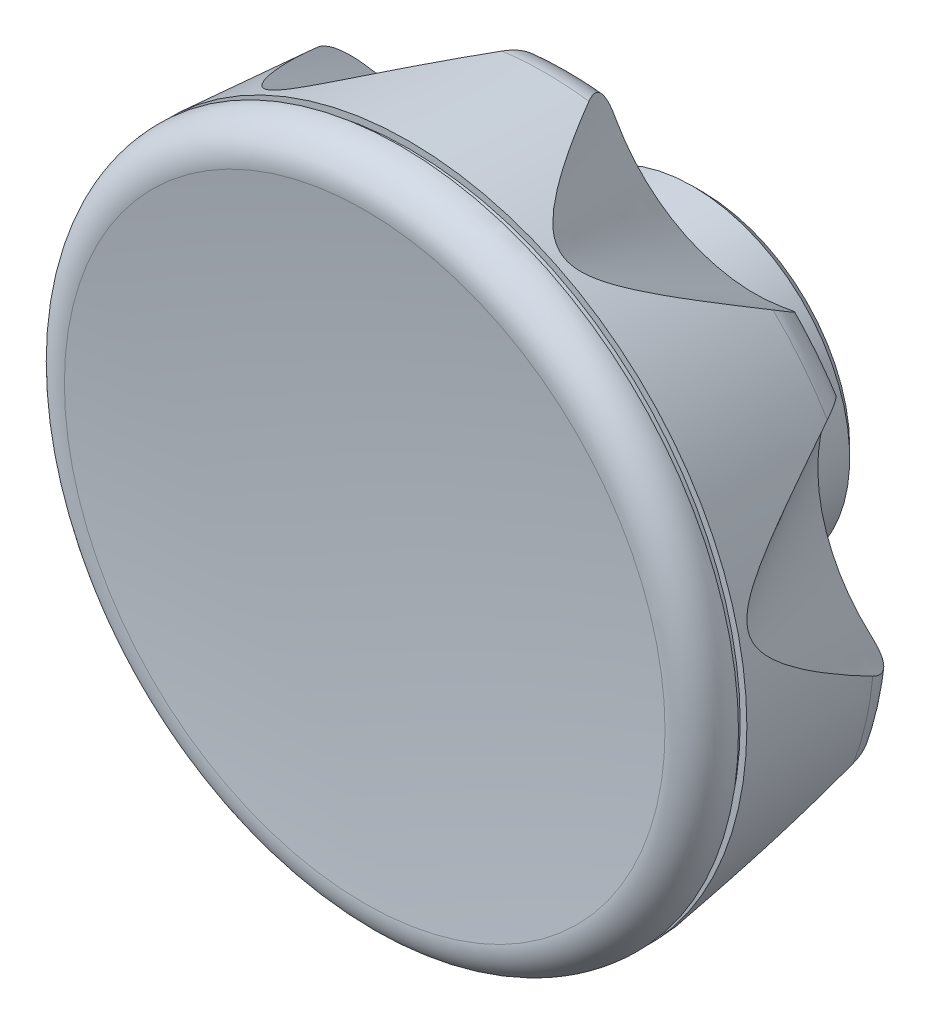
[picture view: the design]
ISO-10303-21;
HEADER;
FILE_DESCRIPTION(('STEP AP214'),'2;1');
FILE_NAME('part.step','',(''),(''),'','','');
FILE_SCHEMA(('AUTOMOTIVE_DESIGN { 1 0 10303 214 1 1 1 1 }'));
ENDSEC;
DATA;
#1=APPLICATION_CONTEXT('core data for automotive mechanical design processes');
#2=APPLICATION_PROTOCOL_DEFINITION('international standard','automotive_design',2000,#1);
#3=PRODUCT_CONTEXT('',#1,'mechanical');
#4=PRODUCT('Part','Part','',(#3));
#5=PRODUCT_RELATED_PRODUCT_CATEGORY('part','',(#4));
#6=PRODUCT_DEFINITION_FORMATION('','',#4);
#7=PRODUCT_DEFINITION_CONTEXT('part definition',#1,'design');
#8=PRODUCT_DEFINITION('design','',#6,#7);
#9=PRODUCT_DEFINITION_SHAPE('','',#8);
#10=(LENGTH_UNIT() NAMED_UNIT(*) SI_UNIT(.MILLI.,.METRE.));
#11=(NAMED_UNIT(*) PLANE_ANGLE_UNIT() SI_UNIT($,.RADIAN.));
#12=(NAMED_UNIT(*) SI_UNIT($,.STERADIAN.) SOLID_ANGLE_UNIT());
#13=UNCERTAINTY_MEASURE_WITH_UNIT(LENGTH_MEASURE(1.E-05),#10,'distance_accuracy_value','');
#14=(GEOMETRIC_REPRESENTATION_CONTEXT(3) GLOBAL_UNCERTAINTY_ASSIGNED_CONTEXT((#13)) GLOBAL_UNIT_ASSIGNED_CONTEXT((#10,
#11,#12)) REPRESENTATION_CONTEXT('',''));
#15=CARTESIAN_POINT('',(0.,0.,0.));
#16=DIRECTION('',(0.,0.,1.));
#17=DIRECTION('',(1.,0.,0.));
#18=AXIS2_PLACEMENT_3D('',#15,#16,#17);
#19=CARTESIAN_POINT('',(0.,0.,16.5));
#20=DIRECTION('',(0.,0.,1.));
#21=DIRECTION('',(0.,1.,0.));
#22=AXIS2_PLACEMENT_3D('',#19,#20,#21);
#23=TOROIDAL_SURFACE('',#22,30.5569827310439,3.49999999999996);
#24=CARTESIAN_POINT('',(-30.4277694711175,-2.80714065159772,12.9999999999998));
#25=CARTESIAN_POINT('',(-30.4922913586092,-2.86477433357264,12.9999995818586));
#26=CARTESIAN_POINT('',(-30.558064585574,-2.92106397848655,13.002073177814));
#27=CARTESIAN_POINT('',(-30.6919823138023,-3.03053883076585,13.010813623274));
#28=CARTESIAN_POINT('',(-30.7601296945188,-3.08372004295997,13.017486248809));
#29=CARTESIAN_POINT('',(-30.8991260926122,-3.18687819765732,13.0359552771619));
#30=CARTESIAN_POINT('',(-30.9699939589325,-3.23682184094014,13.0477974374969));
#31=CARTESIAN_POINT('',(-31.1134463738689,-3.33240092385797,13.0770311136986));
#32=CARTESIAN_POINT('',(-31.1860302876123,-3.378037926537,13.0944206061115));
#33=CARTESIAN_POINT('',(-31.3330374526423,-3.46480885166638,13.1352731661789));
#34=CARTESIAN_POINT('',(-31.4074708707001,-3.50590306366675,13.1587845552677));
#35=CARTESIAN_POINT('',(-31.5569302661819,-3.58258562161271,13.2120638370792));
#36=CARTESIAN_POINT('',(-31.6319561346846,-3.61817495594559,13.2418306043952));
#37=CARTESIAN_POINT('',(-31.7815087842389,-3.68321920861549,13.3075877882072));
#38=CARTESIAN_POINT('',(-31.856036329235,-3.71269963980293,13.34355112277));
#39=CARTESIAN_POINT('',(-32.0040438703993,-3.76533170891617,13.4217135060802));
#40=CARTESIAN_POINT('',(-32.077524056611,-3.78848450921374,13.4639114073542));
#41=CARTESIAN_POINT('',(-32.2127536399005,-3.82555260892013,13.5481801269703));
#42=CARTESIAN_POINT('',(-32.2747476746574,-3.84029295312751,13.5894992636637));
#43=CARTESIAN_POINT('',(-32.3967559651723,-3.8648324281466,13.6763591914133));
#44=CARTESIAN_POINT('',(-32.4567695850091,-3.87462998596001,13.7219013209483));
#45=CARTESIAN_POINT('',(-32.5743242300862,-3.88932568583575,13.8168914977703));
#46=CARTESIAN_POINT('',(-32.6318634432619,-3.89422029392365,13.8663423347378));
#47=CARTESIAN_POINT('',(-32.7439869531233,-3.89923372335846,13.9687276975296));
#48=CARTESIAN_POINT('',(-32.7985700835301,-3.89935067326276,14.0216635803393));
#49=CARTESIAN_POINT('',(-32.9523859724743,-3.89300950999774,14.1800128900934));
#50=CARTESIAN_POINT('',(-33.0472644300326,-3.88049800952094,14.289516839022));
#51=CARTESIAN_POINT('',(-33.2229626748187,-3.84059009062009,14.5165356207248));
#52=CARTESIAN_POINT('',(-33.3037858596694,-3.81319727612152,14.6340485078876));
#53=CARTESIAN_POINT('',(-33.4587694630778,-3.74182305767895,14.8877018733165));
#54=CARTESIAN_POINT('',(-33.5312118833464,-3.69634528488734,15.0244673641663));
#55=CARTESIAN_POINT('',(-33.6577169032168,-3.59210577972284,15.3014973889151));
#56=CARTESIAN_POINT('',(-33.7117580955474,-3.53332870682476,15.4417657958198));
#57=CARTESIAN_POINT('',(-33.7933589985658,-3.41681811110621,15.6966901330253));
#58=CARTESIAN_POINT('',(-33.8239786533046,-3.36093708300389,15.8112404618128));
#59=CARTESIAN_POINT('',(-33.8735900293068,-3.24311939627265,16.0391889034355));
#60=CARTESIAN_POINT('',(-33.8926252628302,-3.18120642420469,16.1525897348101));
#61=CARTESIAN_POINT('',(-33.906149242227,-3.11665429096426,16.2650726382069));
#62=B_SPLINE_CURVE_WITH_KNOTS('',3,(#24,#25,#26,#27,#28,#29,#30,#31,#32,#33,#34,#35,#36,#37,#38,
#39,#40,#41,#42,#43,#44,#45,#46,#47,#48,#49,#50,#51,#52,#53,#54,#55,#56,#57,#58,#59,#60,#61),
.UNSPECIFIED.,.F.,.F.,(4,2,2,2,2,2,2,2,2,2,2,2,2,2,2,2,2,2,4),(0.,0.259555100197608,
0.519436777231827,0.781666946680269,1.04380157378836,1.30807155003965,1.57229402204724,
1.83538972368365,2.09843706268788,2.32597812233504,2.55359154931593,2.78136891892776,
3.00923550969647,3.44356210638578,3.87778356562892,4.35989598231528,4.84256736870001,
5.23515773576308,5.6262642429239),.UNSPECIFIED.);
#63=CARTESIAN_POINT('',(-30.4277694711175,-2.8071406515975,12.9999999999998));
#64=VERTEX_POINT('',#63);
#65=CARTESIAN_POINT('',(-33.906149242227,-3.11665429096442,16.2650726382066));
#66=VERTEX_POINT('',#65);
#67=EDGE_CURVE('E116',#64,#66,#62,.T.);
#68=ORIENTED_EDGE('',*,*,#67,.F.);
#69=CARTESIAN_POINT('',(0.,0.,12.9999999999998));
#70=DIRECTION('',(0.,0.,1.));
#71=DIRECTION('',(0.,1.,0.));
#72=AXIS2_PLACEMENT_3D('',#69,#70,#71);
#73=CIRCLE('',#72,30.5569827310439);
#74=CARTESIAN_POINT('',(-28.632445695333,-10.6729680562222,12.9999999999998));
#75=VERTEX_POINT('',#74);
#76=EDGE_CURVE('E37',#64,#75,#73,.T.);
#77=ORIENTED_EDGE('',*,*,#76,.T.);
#78=CARTESIAN_POINT('',(-31.9006505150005,-11.9033183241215,16.2650726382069));
#79=CARTESIAN_POINT('',(-31.9127655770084,-11.8542285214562,16.1788472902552));
#80=CARTESIAN_POINT('',(-31.9213061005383,-11.8051794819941,16.092150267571));
#81=CARTESIAN_POINT('',(-31.9308592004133,-11.7073324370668,15.9181115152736));
#82=CARTESIAN_POINT('',(-31.9318654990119,-11.6585346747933,15.8307693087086));
#83=CARTESIAN_POINT('',(-31.9229383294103,-11.512015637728,15.5668553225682));
#84=CARTESIAN_POINT('',(-31.9008235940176,-11.4150672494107,15.389974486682));
#85=CARTESIAN_POINT('',(-31.8413429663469,-11.2738330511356,15.1279647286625));
#86=CARTESIAN_POINT('',(-31.8170085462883,-11.2273082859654,15.0409016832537));
#87=CARTESIAN_POINT('',(-31.7592310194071,-11.1363098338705,14.8687696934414));
#88=CARTESIAN_POINT('',(-31.7257939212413,-11.0918348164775,14.7836994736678));
#89=CARTESIAN_POINT('',(-31.6497513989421,-11.0057346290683,14.616681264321));
#90=CARTESIAN_POINT('',(-31.6071781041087,-10.9641001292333,14.53472348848));
#91=CARTESIAN_POINT('',(-31.5127571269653,-10.8842577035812,14.3745637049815));
#92=CARTESIAN_POINT('',(-31.4609118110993,-10.8460489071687,14.296360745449));
#93=CARTESIAN_POINT('',(-31.3560371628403,-10.7789272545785,14.1553613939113));
#94=CARTESIAN_POINT('',(-31.3041952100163,-10.7494623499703,14.0919431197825));
#95=CARTESIAN_POINT('',(-31.1940469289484,-10.6941766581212,13.9692748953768));
#96=CARTESIAN_POINT('',(-31.1357419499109,-10.6683551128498,13.9100240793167));
#97=CARTESIAN_POINT('',(-31.0131130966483,-10.6208593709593,13.7963342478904));
#98=CARTESIAN_POINT('',(-30.9487918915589,-10.599183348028,13.7418931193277));
#99=CARTESIAN_POINT('',(-30.8147052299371,-10.5604026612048,13.6383551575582));
#100=CARTESIAN_POINT('',(-30.7449405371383,-10.5432973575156,13.5892575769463));
#101=CARTESIAN_POINT('',(-30.6117866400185,-10.5162408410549,13.5039379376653));
#102=CARTESIAN_POINT('',(-30.5490604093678,-10.5055947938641,13.4668960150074));
#103=CARTESIAN_POINT('',(-30.4207373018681,-10.4879457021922,13.3971240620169));
#104=CARTESIAN_POINT('',(-30.3551395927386,-10.480943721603,13.3643952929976));
#105=CARTESIAN_POINT('',(-30.2216746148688,-10.4706537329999,13.3033769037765));
#106=CARTESIAN_POINT('',(-30.1538085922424,-10.467363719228,13.2750848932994));
#107=CARTESIAN_POINT('',(-30.0163143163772,-10.4644744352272,13.2229137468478));
#108=CARTESIAN_POINT('',(-29.9466854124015,-10.4648765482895,13.1990362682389));
#109=CARTESIAN_POINT('',(-29.735784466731,-10.4715361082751,13.1338837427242));
#110=CARTESIAN_POINT('',(-29.5926042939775,-10.4832546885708,13.0991362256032));
#111=CARTESIAN_POINT('',(-29.3050619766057,-10.5200545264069,13.0457059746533));
#112=CARTESIAN_POINT('',(-29.1606993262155,-10.5451418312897,13.0270305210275));
#113=CARTESIAN_POINT('',(-28.952520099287,-10.5899735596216,13.0100924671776));
#114=CARTESIAN_POINT('',(-28.8880614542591,-10.6050709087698,13.0062521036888));
#115=CARTESIAN_POINT('',(-28.7597887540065,-10.637430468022,13.0012106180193));
#116=CARTESIAN_POINT('',(-28.6959733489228,-10.6546860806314,13.0000016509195));
#117=CARTESIAN_POINT('',(-28.632445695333,-10.6729680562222,12.9999999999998));
#118=B_SPLINE_CURVE_WITH_KNOTS('',3,(#78,#79,#80,#81,#82,#83,#84,#85,#86,#87,#88,#89,#90,#91,
#92,#93,#94,#95,#96,#97,#98,#99,#100,#101,#102,#103,#104,#105,#106,#107,#108,#109,#110,#111,
#112,#113,#114,#115,#116,#117),.UNSPECIFIED.,.F.,.F.,(4,2,2,2,2,2,2,2,2,2,2,2,2,2,2,2,2,2,2,4),
(0.,0.299698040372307,0.599645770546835,1.20498031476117,1.50964069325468,1.81410045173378,
2.11750656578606,2.4208353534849,2.68159295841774,2.94229623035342,3.20288438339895,
3.46343604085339,3.68403118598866,3.90469069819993,4.12523092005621,4.34585377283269,
4.78744512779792,5.22923640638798,5.42810702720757,5.62638394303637),.UNSPECIFIED.);
#119=CARTESIAN_POINT('',(-31.9006505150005,-11.9033183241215,16.2650726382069));
#120=VERTEX_POINT('',#119);
#121=EDGE_CURVE('E340',#120,#75,#118,.T.);
#122=ORIENTED_EDGE('',*,*,#121,.F.);
#123=CARTESIAN_POINT('',(0.,0.,16.2650726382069));
#124=DIRECTION('',(0.,0.,1.));
#125=DIRECTION('',(0.,1.,0.));
#126=AXIS2_PLACEMENT_3D('',#123,#124,#125);
#127=CIRCLE('',#126,34.0490894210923);
#128=EDGE_CURVE('E123',#66,#120,#127,.T.);
#129=ORIENTED_EDGE('',*,*,#128,.F.);
#130=EDGE_LOOP('',(#68,#77,#122,#129));
#131=FACE_BOUND('',#130,.T.);
#132=ADVANCED_FACE('F14',(#131),#23,.T.);
#133=CARTESIAN_POINT('',(-16.7766930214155,-25.5396116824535,12.9999999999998));
#134=CARTESIAN_POINT('',(-16.7718619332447,-25.6259909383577,12.9999995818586));
#135=CARTESIAN_POINT('',(-16.7688618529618,-25.7125105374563,13.002073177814));
#136=CARTESIAN_POINT('',(-16.7667673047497,-25.8854680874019,13.010813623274));
#137=CARTESIAN_POINT('',(-16.7676777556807,-25.9719057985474,13.017486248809));
#138=CARTESIAN_POINT('',(-16.7736882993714,-26.1448956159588,13.0359552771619));
#139=CARTESIAN_POINT('',(-16.7788261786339,-26.2314416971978,13.0477974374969));
#140=CARTESIAN_POINT('',(-16.7935405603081,-26.4031898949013,13.0770311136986));
#141=CARTESIAN_POINT('',(-16.803115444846,-26.4883924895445,13.0944206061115));
#142=CARTESIAN_POINT('',(-16.8269326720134,-26.6574281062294,13.1352731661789));
#143=CARTESIAN_POINT('',(-16.8412124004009,-26.7412443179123,13.1587845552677));
#144=CARTESIAN_POINT('',(-16.8744459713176,-26.9059071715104,13.2120638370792));
#145=CARTESIAN_POINT('',(-16.893398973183,-26.9867543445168,13.2418306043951));
#146=CARTESIAN_POINT('',(-16.9357898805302,-27.1442337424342,13.3075877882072));
#147=CARTESIAN_POINT('',(-16.9592083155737,-27.220882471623,13.3435511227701));
#148=CARTESIAN_POINT('',(-17.0103400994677,-27.3694149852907,13.4217135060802));
#149=CARTESIAN_POINT('',(-17.0380526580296,-27.4412996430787,13.4639114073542));
#150=CARTESIAN_POINT('',(-17.0933859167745,-27.5701379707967,13.5481801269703));
#151=CARTESIAN_POINT('',(-17.1205141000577,-27.6277973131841,13.5894992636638));
#152=CARTESIAN_POINT('',(-17.1773992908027,-27.738487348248,13.6763591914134));
#153=CARTESIAN_POINT('',(-17.2071571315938,-27.7915165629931,13.7219013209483));
#154=CARTESIAN_POINT('',(-17.2689616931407,-27.8925871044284,13.8168914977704));
#155=CARTESIAN_POINT('',(-17.3010100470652,-27.9406248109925,13.8663423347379));
#156=CARTESIAN_POINT('',(-17.3669982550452,-28.0314123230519,13.9687276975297));
#157=CARTESIAN_POINT('',(-17.4009388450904,-28.0741600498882,14.0216635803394));
#158=CARTESIAN_POINT('',(-17.501799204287,-28.1904645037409,14.1800128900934));
#159=CARTESIAN_POINT('',(-17.5707368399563,-28.2568426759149,14.289516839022));
#160=CARTESIAN_POINT('',(-17.7114841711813,-28.3693269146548,14.5165356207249));
#161=CARTESIAN_POINT('',(-17.7832931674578,-28.4154378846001,14.6340485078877));
#162=CARTESIAN_POINT('',(-17.9357264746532,-28.4921078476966,14.8877018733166));
#163=CARTESIAN_POINT('',(-18.0164495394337,-28.5203906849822,15.0244673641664));
#164=CARTESIAN_POINT('',(-18.1768218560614,-28.5543040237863,15.3014973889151));
#165=CARTESIAN_POINT('',(-18.256469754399,-28.5599082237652,15.4417657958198));
#166=CARTESIAN_POINT('',(-18.3984387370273,-28.5510632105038,15.6966901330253));
#167=CARTESIAN_POINT('',(-18.4612193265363,-28.5401613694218,15.8112404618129));
#168=CARTESIAN_POINT('',(-18.5842650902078,-28.5054909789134,16.0391889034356));
#169=CARTESIAN_POINT('',(-18.6445388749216,-28.4817712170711,16.1525897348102));
#170=CARTESIAN_POINT('',(-18.703439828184,-28.4520970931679,16.2650726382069));
#171=B_SPLINE_CURVE_WITH_KNOTS('',3,(#133,#134,#135,#136,#137,#138,#139,#140,#141,#142,#143,
#144,#145,#146,#147,#148,#149,#150,#151,#152,#153,#154,#155,#156,#157,#158,#159,#160,#161,#162,
#163,#164,#165,#166,#167,#168,#169,#170),.UNSPECIFIED.,.F.,.F.,(4,2,2,2,2,2,2,2,2,2,2,2,2,2,2,2,
2,2,4),(0.,0.259555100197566,0.519436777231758,0.781666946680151,1.04380157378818,
1.30807155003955,1.57229402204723,1.83538972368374,2.09843706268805,2.32597812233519,
2.55359154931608,2.78136891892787,3.00923550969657,3.44356210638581,3.8777835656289,
4.35989598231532,4.84256736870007,5.23515773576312,5.62626424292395),.UNSPECIFIED.);
#172=CARTESIAN_POINT('',(-16.7766930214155,-25.5396116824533,12.9999999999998));
#173=VERTEX_POINT('',#172);
#174=CARTESIAN_POINT('',(-18.7034398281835,-28.4520970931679,16.2650726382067));
#175=VERTEX_POINT('',#174);
#176=EDGE_CURVE('E339',#173,#175,#171,.T.);
#177=ORIENTED_EDGE('',*,*,#176,.F.);
#178=CARTESIAN_POINT('',(-9.50757545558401,-29.040234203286,12.9999999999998));
#179=VERTEX_POINT('',#178);
#180=EDGE_CURVE('E132',#173,#179,#73,.T.);
#181=ORIENTED_EDGE('',*,*,#180,.T.);
#182=CARTESIAN_POINT('',(-10.5833412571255,-32.3625304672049,16.2650726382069));
#183=CARTESIAN_POINT('',(-10.6292748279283,-32.341395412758,16.1788472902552));
#184=CARTESIAN_POINT('',(-10.6729478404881,-32.3174910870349,16.092150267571));
#185=CARTESIAN_POINT('',(-10.755404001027,-32.2639533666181,15.9181115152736));
#186=CARTESIAN_POINT('',(-10.7941830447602,-32.2343152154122,15.8307693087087));
#187=CARTESIAN_POINT('',(-10.9031702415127,-32.1359825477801,15.5668553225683));
#188=CARTESIAN_POINT('',(-10.9651792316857,-32.0582462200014,15.389974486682));
#189=CARTESIAN_POINT('',(-11.0385150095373,-31.9236843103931,15.1279647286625));
#190=CARTESIAN_POINT('',(-11.0597172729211,-31.8756511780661,15.0409016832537));
#191=CARTESIAN_POINT('',(-11.0948390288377,-31.773742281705,14.8687696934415));
#192=CARTESIAN_POINT('',(-11.1087633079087,-31.7198703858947,14.7836994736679));
#193=CARTESIAN_POINT('',(-11.1286674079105,-31.6067353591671,14.616681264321));
#194=CARTESIAN_POINT('',(-11.1346745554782,-31.5474915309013,14.53472348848));
#195=CARTESIAN_POINT('',(-11.1382273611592,-31.4238893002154,14.3745637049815));
#196=CARTESIAN_POINT('',(-11.1357751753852,-31.3595322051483,14.2963607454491));
#197=CARTESIAN_POINT('',(-11.1228647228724,-31.2356882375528,14.1553613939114));
#198=CARTESIAN_POINT('',(-11.1135783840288,-31.1767854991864,14.0919431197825));
#199=CARTESIAN_POINT('',(-11.0881261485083,-31.0561980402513,13.9692748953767));
#200=CARTESIAN_POINT('',(-11.0719616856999,-30.9945139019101,13.9100240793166));
#201=CARTESIAN_POINT('',(-11.0326375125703,-30.86902569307,13.7963342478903));
#202=CARTESIAN_POINT('',(-11.0094808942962,-30.8052225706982,13.7418931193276));
#203=CARTESIAN_POINT('',(-10.9561991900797,-30.67621003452,13.6383551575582));
#204=CARTESIAN_POINT('',(-10.9260750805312,-30.6110008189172,13.5892575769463));
#205=CARTESIAN_POINT('',(-10.8642086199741,-30.4900274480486,13.5039379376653));
#206=CARTESIAN_POINT('',(-10.8334228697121,-30.4343484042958,13.4668960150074));
#207=CARTESIAN_POINT('',(-10.7672133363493,-30.3230173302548,13.3971240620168));
#208=CARTESIAN_POINT('',(-10.731788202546,-30.2673653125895,13.3643952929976));
#209=CARTESIAN_POINT('',(-10.6566191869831,-30.1566024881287,13.3033769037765));
#210=CARTESIAN_POINT('',(-10.6168776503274,-30.1014914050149,13.2750848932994));
#211=CARTESIAN_POINT('',(-10.5334103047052,-29.992192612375,13.2229137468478));
#212=CARTESIAN_POINT('',(-10.4896830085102,-29.9380052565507,13.1990362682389));
#213=CARTESIAN_POINT('',(-10.3529817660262,-29.777268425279,13.1338837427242));
#214=CARTESIAN_POINT('',(-10.2545484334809,-29.6726320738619,13.0991362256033));
#215=CARTESIAN_POINT('',(-10.0464974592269,-29.4707667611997,13.0457059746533));
#216=CARTESIAN_POINT('',(-9.93687477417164,-29.3735411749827,13.0270305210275));
#217=CARTESIAN_POINT('',(-9.77202629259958,-29.2387322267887,13.0100924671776));
#218=CARTESIAN_POINT('',(-9.72003340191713,-29.1977494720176,13.0062521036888));
#219=CARTESIAN_POINT('',(-9.61475695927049,-29.1176376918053,13.0012106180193));
#220=CARTESIAN_POINT('',(-9.56147772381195,-29.0785034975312,13.0000016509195));
#221=CARTESIAN_POINT('',(-9.50757545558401,-29.0402342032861,12.9999999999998));
#222=B_SPLINE_CURVE_WITH_KNOTS('',3,(#182,#183,#184,#185,#186,#187,#188,#189,#190,#191,#192,
#193,#194,#195,#196,#197,#198,#199,#200,#201,#202,#203,#204,#205,#206,#207,#208,#209,#210,#211,
#212,#213,#214,#215,#216,#217,#218,#219,#220,#221),.UNSPECIFIED.,.F.,.F.,(4,2,2,2,2,2,2,2,2,2,2,
2,2,2,2,2,2,2,2,4),(0.,0.299698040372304,0.599645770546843,1.20498031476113,1.50964069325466,
1.81410045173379,2.1175065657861,2.42083535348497,2.68159295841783,2.94229623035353,
3.20288438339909,3.46343604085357,3.6840311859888,3.90469069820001,4.12523092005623,
4.34585377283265,4.78744512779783,5.22923640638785,5.42810702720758,5.62638394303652),.UNSPECIFIED.);
#223=CARTESIAN_POINT('',(-10.5833412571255,-32.3625304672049,16.2650726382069));
#224=VERTEX_POINT('',#223);
#225=EDGE_CURVE('E385',#224,#179,#222,.T.);
#226=ORIENTED_EDGE('',*,*,#225,.F.);
#227=EDGE_CURVE('E654',#175,#224,#127,.T.);
#228=ORIENTED_EDGE('',*,*,#227,.F.);
#229=EDGE_LOOP('',(#177,#181,#226,#228));
#230=FACE_BOUND('',#229,.T.);
#231=ADVANCED_FACE('F172',(#230),#23,.T.);
#232=CARTESIAN_POINT('',(9.50757545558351,-29.0402342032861,12.9999999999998));
#233=CARTESIAN_POINT('',(9.5781216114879,-29.090313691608,12.9999995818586));
#234=CARTESIAN_POINT('',(9.64763587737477,-29.1419122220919,13.002073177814));
#235=CARTESIAN_POINT('',(9.78416546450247,-29.2481119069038,13.010813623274));
#236=CARTESIAN_POINT('',(9.85117753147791,-29.3027167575,13.017486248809));
#237=CARTESIAN_POINT('',(9.98267890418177,-29.4152733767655,13.0359552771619));
#238=CARTESIAN_POINT('',(10.0471399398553,-29.4732509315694,13.0477974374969));
#239=CARTESIAN_POINT('',(10.1722438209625,-29.5918383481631,13.0770311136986));
#240=CARTESIAN_POINT('',(10.2328880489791,-29.6524472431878,13.0944206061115));
#241=CARTESIAN_POINT('',(10.3501956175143,-29.7764602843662,13.1352731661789));
#242=CARTESIAN_POINT('',(10.4068225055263,-29.8398831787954,13.1587845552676));
#243=CARTESIAN_POINT('',(10.5148403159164,-29.9685318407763,13.2120638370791));
#244=CARTESIAN_POINT('',(10.5662321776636,-30.0337572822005,13.2418306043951));
#245=CARTESIAN_POINT('',(10.662924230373,-30.1650866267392,13.3075877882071));
#246=CARTESIAN_POINT('',(10.7082494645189,-30.231185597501,13.3435511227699));
#247=CARTESIAN_POINT('',(10.7924967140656,-30.3637705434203,13.4217135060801));
#248=CARTESIAN_POINT('',(10.8314199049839,-30.4302564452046,13.4639114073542));
#249=CARTESIAN_POINT('',(10.8976500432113,-30.5538471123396,13.5481801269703));
#250=CARTESIAN_POINT('',(10.9258157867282,-30.611006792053,13.5894992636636));
#251=CARTESIAN_POINT('',(10.9768894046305,-30.7244955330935,13.6763591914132));
#252=CARTESIAN_POINT('',(10.9997956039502,-30.7808243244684,13.7219013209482));
#253=CARTESIAN_POINT('',(11.0402812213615,-30.8921615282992,13.8168914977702));
#254=CARTESIAN_POINT('',(11.0578567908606,-30.9471689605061,13.8663423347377));
#255=CARTESIAN_POINT('',(11.0876943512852,-31.0553657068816,13.9687276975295));
#256=CARTESIAN_POINT('',(11.0999542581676,-31.1085543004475,14.0216635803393));
#257=CARTESIAN_POINT('',(11.12799933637,-31.2599247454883,14.1800128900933));
#258=CARTESIAN_POINT('',(11.1369139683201,-31.3552084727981,14.2895168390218));
#259=CARTESIAN_POINT('',(11.1371031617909,-31.5353819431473,14.5165356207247));
#260=CARTESIAN_POINT('',(11.1283819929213,-31.6202741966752,14.6340485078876));
#261=CARTESIAN_POINT('',(11.0932843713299,-31.7872542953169,14.8877018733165));
#262=CARTESIAN_POINT('',(11.0650667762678,-31.868000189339,15.0244673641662));
#263=CARTESIAN_POINT('',(10.9915907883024,-32.0145289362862,15.3014973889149));
#264=CARTESIAN_POINT('',(10.9463126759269,-32.0802943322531,15.4417657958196));
#265=CARTESIAN_POINT('',(10.8508811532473,-32.1857753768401,15.6966901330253));
#266=CARTESIAN_POINT('',(10.8032146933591,-32.2280620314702,15.8112404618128));
#267=CARTESIAN_POINT('',(10.6993905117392,-32.3026464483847,16.0391889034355));
#268=CARTESIAN_POINT('',(10.6432655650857,-32.3349813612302,16.1525897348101));
#269=CARTESIAN_POINT('',(10.5833412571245,-32.362530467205,16.2650726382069));
#270=B_SPLINE_CURVE_WITH_KNOTS('',3,(#232,#233,#234,#235,#236,#237,#238,#239,#240,#241,#242,
#243,#244,#245,#246,#247,#248,#249,#250,#251,#252,#253,#254,#255,#256,#257,#258,#259,#260,#261,
#262,#263,#264,#265,#266,#267,#268,#269),.UNSPECIFIED.,.F.,.F.,(4,2,2,2,2,2,2,2,2,2,2,2,2,2,2,2,
2,2,4),(0.,0.259555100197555,0.51943677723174,0.781666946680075,1.04380157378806,
1.30807155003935,1.57229402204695,1.83538972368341,2.09843706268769,2.32597812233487,
2.55359154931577,2.78136891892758,3.00923550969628,3.44356210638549,3.87778356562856,
4.35989598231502,4.84256736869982,5.23515773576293,5.62626424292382),.UNSPECIFIED.);
#271=CARTESIAN_POINT('',(9.50757545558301,-29.0402342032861,12.9999999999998));
#272=VERTEX_POINT('',#271);
#273=CARTESIAN_POINT('',(10.583341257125,-32.3625304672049,16.2650726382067));
#274=VERTEX_POINT('',#273);
#275=EDGE_CURVE('E390',#272,#274,#270,.T.);
#276=ORIENTED_EDGE('',*,*,#275,.F.);
#277=CARTESIAN_POINT('',(16.7766930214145,-25.5396116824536,12.9999999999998));
#278=VERTEX_POINT('',#277);
#279=EDGE_CURVE('E136',#272,#278,#73,.T.);
#280=ORIENTED_EDGE('',*,*,#279,.T.);
#281=CARTESIAN_POINT('',(18.703439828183,-28.4520970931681,16.2650726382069));
#282=CARTESIAN_POINT('',(18.6582766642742,-28.4748319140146,16.1788472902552));
#283=CARTESIAN_POINT('',(18.6123578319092,-28.4940727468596,16.0921502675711));
#284=CARTESIAN_POINT('',(18.5190897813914,-28.5251593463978,15.9181115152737));
#285=CARTESIAN_POINT('',(18.4717394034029,-28.5369989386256,15.8307693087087));
#286=CARTESIAN_POINT('',(18.3269074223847,-28.5608991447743,15.5668553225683));
#287=CARTESIAN_POINT('',(18.2274687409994,-28.5609119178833,15.3899744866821));
#288=CARTESIAN_POINT('',(18.0765398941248,-28.5343501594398,15.1279647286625));
#289=CARTESIAN_POINT('',(18.0257666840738,-28.5209785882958,15.0409016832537));
#290=CARTESIAN_POINT('',(17.9241930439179,-28.4848987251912,14.8687696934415));
#291=CARTESIAN_POINT('',(17.8733926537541,-28.462196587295,14.7836994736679));
#292=CARTESIAN_POINT('',(17.7725301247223,-28.407219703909,14.616681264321));
#293=CARTESIAN_POINT('',(17.7224660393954,-28.3749783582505,14.53472348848));
#294=CARTESIAN_POINT('',(17.6236147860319,-28.3006913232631,14.3745637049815));
#295=CARTESIAN_POINT('',(17.5748272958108,-28.2586481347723,14.2963607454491));
#296=CARTESIAN_POINT('',(17.4860517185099,-28.1713388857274,14.1553613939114));
#297=CARTESIAN_POINT('',(17.4457896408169,-28.1273532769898,14.0919431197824));
#298=CARTESIAN_POINT('',(17.3673797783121,-28.0322688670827,13.9692748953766));
#299=CARTESIAN_POINT('',(17.3292315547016,-27.9811715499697,13.9100240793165));
#300=CARTESIAN_POINT('',(17.2556391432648,-27.8721860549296,13.7963342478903));
#301=CARTESIAN_POINT('',(17.2201937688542,-27.8143008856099,13.7418931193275));
#302=CARTESIAN_POINT('',(17.1525483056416,-27.6922055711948,13.6383551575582));
#303=CARTESIAN_POINT('',(17.12034776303,-27.6279963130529,13.5892575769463));
#304=CARTESIAN_POINT('',(17.064340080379,-27.5042015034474,13.5039379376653));
#305=CARTESIAN_POINT('',(17.0400030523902,-27.4454169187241,13.4668960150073));
#306=CARTESIAN_POINT('',(16.9942418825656,-27.3242384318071,13.3971240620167));
#307=CARTESIAN_POINT('',(16.9728185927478,-27.2618434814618,13.3643952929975));
#308=CARTESIAN_POINT('',(16.9330878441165,-27.1340144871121,13.3033769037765));
#309=CARTESIAN_POINT('',(16.9147787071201,-27.0685821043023,13.2750848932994));
#310=CARTESIAN_POINT('',(16.8813665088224,-26.9351780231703,13.2229137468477));
#311=CARTESIAN_POINT('',(16.8662646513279,-26.8672053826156,13.1990362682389));
#312=CARTESIAN_POINT('',(16.825827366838,-26.660110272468,13.1338837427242));
#313=CARTESIAN_POINT('',(16.805391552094,-26.5179122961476,13.0991362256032));
#314=CARTESIAN_POINT('',(16.7772845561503,-26.2293905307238,13.0457059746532));
#315=CARTESIAN_POINT('',(16.7696191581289,-26.0830649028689,13.0270305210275));
#316=CARTESIAN_POINT('',(16.7670026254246,-25.8701291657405,13.0100924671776));
#317=CARTESIAN_POINT('',(16.7673780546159,-25.8039271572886,13.0062521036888));
#318=CARTESIAN_POINT('',(16.7703829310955,-25.6716698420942,13.0012106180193));
#319=CARTESIAN_POINT('',(16.7730056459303,-25.605614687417,13.0000016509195));
#320=CARTESIAN_POINT('',(16.776693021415,-25.5396116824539,12.9999999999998));
#321=B_SPLINE_CURVE_WITH_KNOTS('',3,(#281,#282,#283,#284,#285,#286,#287,#288,#289,#290,#291,
#292,#293,#294,#295,#296,#297,#298,#299,#300,#301,#302,#303,#304,#305,#306,#307,#308,#309,#310,
#311,#312,#313,#314,#315,#316,#317,#318,#319,#320),.UNSPECIFIED.,.F.,.F.,(4,2,2,2,2,2,2,2,2,2,2,
2,2,2,2,2,2,2,2,4),(0.,0.299698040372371,0.599645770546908,1.20498031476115,1.50964069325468,
1.81410045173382,2.11750656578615,2.42083535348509,2.68159295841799,2.9422962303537,
3.20288438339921,3.46343604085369,3.68403118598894,3.90469069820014,4.12523092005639,
4.34585377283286,4.7874451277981,5.22923640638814,5.4281070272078,5.62638394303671),.UNSPECIFIED.);
#322=CARTESIAN_POINT('',(18.703439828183,-28.4520970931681,16.2650726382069));
#323=VERTEX_POINT('',#322);
#324=EDGE_CURVE('E397',#323,#278,#321,.T.);
#325=ORIENTED_EDGE('',*,*,#324,.F.);
#326=EDGE_CURVE('E657',#274,#323,#127,.T.);
#327=ORIENTED_EDGE('',*,*,#326,.F.);
#328=EDGE_LOOP('',(#276,#280,#325,#327));
#329=FACE_BOUND('',#328,.T.);
#330=ADVANCED_FACE('F178',(#329),#23,.T.);
#331=CARTESIAN_POINT('',(28.6324456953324,-10.6729680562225,12.9999999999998));
#332=CARTESIAN_POINT('',(28.7155842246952,-10.6490369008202,12.9999995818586));
#333=CARTESIAN_POINT('',(28.7992670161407,-10.6268596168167,13.002073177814));
#334=CARTESIAN_POINT('',(28.9674220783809,-10.5863309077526,13.010813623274));
#335=CARTESIAN_POINT('',(29.0518952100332,-10.5679843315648,13.017486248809));
#336=CARTESIAN_POINT('',(29.2218852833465,-10.5353503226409,13.0359552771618));
#337=CARTESIAN_POINT('',(29.3074047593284,-10.5211010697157,13.0477974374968));
#338=CARTESIAN_POINT('',(29.4781211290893,-10.4972289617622,13.0770311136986));
#339=CARTESIAN_POINT('',(29.5633181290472,-10.4876044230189,13.0944206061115));
#340=CARTESIAN_POINT('',(29.7334155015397,-10.4732105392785,13.1352731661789));
#341=CARTESIAN_POINT('',(29.8183078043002,-10.4684813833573,13.1587845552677));
#342=CARTESIAN_POINT('',(29.9862373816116,-10.4642407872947,13.2120638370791));
#343=CARTESIAN_POINT('',(30.0692749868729,-10.4647284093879,13.2418306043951));
#344=CARTESIAN_POINT('',(30.2322389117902,-10.4710140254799,13.3075877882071));
#345=CARTESIAN_POINT('',(30.3121769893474,-10.4767893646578,13.34355112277));
#346=CARTESIAN_POINT('',(30.4683633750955,-10.4935875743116,13.4217135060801));
#347=CARTESIAN_POINT('',(30.5446123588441,-10.5046094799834,13.4639114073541));
#348=CARTESIAN_POINT('',(30.68253324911,-10.5298861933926,13.5481801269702));
#349=CARTESIAN_POINT('',(30.7447835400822,-10.5435038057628,13.5894992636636));
#350=CARTESIAN_POINT('',(30.8653564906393,-10.5743319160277,13.6763591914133));
#351=CARTESIAN_POINT('',(30.9236778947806,-10.5915435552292,13.7219013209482));
#352=CARTESIAN_POINT('',(31.0359671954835,-10.6293082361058,13.8168914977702));
#353=CARTESIAN_POINT('',(31.0899319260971,-10.6498636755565,13.8663423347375));
#354=CARTESIAN_POINT('',(31.193126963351,-10.6939952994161,13.9687276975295));
#355=CARTESIAN_POINT('',(31.2423554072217,-10.717572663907,14.0216635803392));
#356=CARTESIAN_POINT('',(31.3781874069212,-10.790024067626,14.1800128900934));
#357=CARTESIAN_POINT('',(31.4582414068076,-10.8424627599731,14.2895168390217));
#358=CARTESIAN_POINT('',(31.5992246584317,-10.9546511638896,14.5165356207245));
#359=CARTESIAN_POINT('',(31.6601585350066,-11.0143991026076,14.6340485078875));
#360=CARTESIAN_POINT('',(31.7688258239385,-11.1459499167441,14.8877018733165));
#361=CARTESIAN_POINT('',(31.8143621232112,-11.2183555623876,15.0244673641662));
#362=CARTESIAN_POINT('',(31.8831113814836,-11.3671605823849,15.3014973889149));
#363=CARTESIAN_POINT('',(31.906298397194,-11.4435644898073,15.4417657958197));
#364=CARTESIAN_POINT('',(31.9292662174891,-11.5839422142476,15.6966901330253));
#365=CARTESIAN_POINT('',(31.932607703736,-11.6475746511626,15.8112404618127));
#366=CARTESIAN_POINT('',(31.9261868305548,-11.7752502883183,16.0391889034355));
#367=CARTESIAN_POINT('',(31.9164739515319,-11.839291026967,16.1525897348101));
#368=CARTESIAN_POINT('',(31.9006505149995,-11.9033183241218,16.2650726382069));
#369=B_SPLINE_CURVE_WITH_KNOTS('',3,(#331,#332,#333,#334,#335,#336,#337,#338,#339,#340,#341,
#342,#343,#344,#345,#346,#347,#348,#349,#350,#351,#352,#353,#354,#355,#356,#357,#358,#359,#360,
#361,#362,#363,#364,#365,#366,#367,#368),.UNSPECIFIED.,.F.,.F.,(4,2,2,2,2,2,2,2,2,2,2,2,2,2,2,2,
2,2,4),(0.,0.25955510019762,0.519436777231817,0.781666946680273,1.0438015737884,
1.30807155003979,1.57229402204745,1.83538972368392,2.09843706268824,2.32597812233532,
2.5535915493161,2.78136891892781,3.00923550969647,3.44356210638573,3.87778356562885,
4.35989598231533,4.8425673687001,5.2351577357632,5.62626424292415),.UNSPECIFIED.);
#370=CARTESIAN_POINT('',(28.6324456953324,-10.6729680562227,12.9999999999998));
#371=VERTEX_POINT('',#370);
#372=CARTESIAN_POINT('',(31.9006505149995,-11.9033183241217,16.2650726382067));
#373=VERTEX_POINT('',#372);
#374=EDGE_CURVE('E407',#371,#373,#369,.T.);
#375=ORIENTED_EDGE('',*,*,#374,.F.);
#376=CARTESIAN_POINT('',(30.4277694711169,-2.80714065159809,12.9999999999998));
#377=VERTEX_POINT('',#376);
#378=EDGE_CURVE('E220',#371,#377,#73,.T.);
#379=ORIENTED_EDGE('',*,*,#378,.T.);
#380=CARTESIAN_POINT('',(33.9061492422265,-3.11665429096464,16.2650726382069));
#381=CARTESIAN_POINT('',(33.8957652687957,-3.16613920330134,16.1788472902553));
#382=CARTESIAN_POINT('',(33.88217843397,-3.21403645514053,16.0921502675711));
#383=CARTESIAN_POINT('',(33.8483312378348,-3.30633853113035,15.9181115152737));
#384=CARTESIAN_POINT('',(33.8280653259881,-3.35074041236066,15.8307693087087));
#385=CARTESIAN_POINT('',(33.7564499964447,-3.47887614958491,15.5668553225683));
#386=CARTESIAN_POINT('',(33.6944609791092,-3.55662840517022,15.3899744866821));
#387=CARTESIAN_POINT('',(33.5795915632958,-3.65806834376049,15.1279647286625));
#388=CARTESIAN_POINT('',(33.5374806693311,-3.6894273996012,15.0409016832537));
#389=CARTESIAN_POINT('',(33.445942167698,-3.74634544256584,14.8687696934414));
#390=CARTESIAN_POINT('',(33.3965193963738,-3.77190823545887,14.7836994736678));
#391=CARTESIAN_POINT('',(33.2906499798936,-3.81648820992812,14.616681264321));
#392=CARTESIAN_POINT('',(33.23422823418,-3.83552773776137,14.53472348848));
#393=CARTESIAN_POINT('',(33.1145155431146,-3.86649555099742,14.3745637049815));
#394=CARTESIAN_POINT('',(33.0512263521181,-3.87842564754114,14.2963607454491));
#395=CARTESIAN_POINT('',(32.9276145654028,-3.89339676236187,14.1553613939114));
#396=CARTESIAN_POINT('',(32.8681222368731,-3.89745034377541,14.0919431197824));
#397=CARTESIAN_POINT('',(32.7448945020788,-3.89946948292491,13.9692748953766));
#398=CARTESIAN_POINT('',(32.6811599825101,-3.8974363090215,13.9100240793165));
#399=CARTESIAN_POINT('',(32.5500675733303,-3.88702182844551,13.7963342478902));
#400=CARTESIAN_POINT('',(32.4827112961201,-3.87864332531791,13.7418931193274));
#401=CARTESIAN_POINT('',(32.3450770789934,-3.85540549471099,13.6383551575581));
#402=CARTESIAN_POINT('',(32.2747995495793,-3.84054707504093,13.5892575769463));
#403=CARTESIAN_POINT('',(32.143092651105,-3.80715084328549,13.5039379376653));
#404=CARTESIAN_POINT('',(32.081959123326,-3.78952670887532,13.4668960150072));
#405=CARTESIAN_POINT('',(31.9586863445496,-3.74975068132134,13.3971240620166));
#406=CARTESIAN_POINT('',(31.896546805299,-3.72759746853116,13.3643952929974));
#407=CARTESIAN_POINT('',(31.7718343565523,-3.67896014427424,13.3033769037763));
#408=CARTESIAN_POINT('',(31.7092616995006,-3.65247838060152,13.2750848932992));
#409=CARTESIAN_POINT('',(31.5841300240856,-3.59542500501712,13.2229137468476));
#410=CARTESIAN_POINT('',(31.5215710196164,-3.56485186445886,13.1990362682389));
#411=CARTESIAN_POINT('',(31.3344453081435,-3.46734531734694,13.1338837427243));
#412=CARTESIAN_POINT('',(31.2105289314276,-3.39466369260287,13.0991362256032));
#413=CARTESIAN_POINT('',(30.9674291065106,-3.23674824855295,13.0457059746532));
#414=CARTESIAN_POINT('',(30.8482478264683,-3.15150876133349,13.0270305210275));
#415=CARTESIAN_POINT('',(30.6801365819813,-3.02079118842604,13.0100924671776));
#416=CARTESIAN_POINT('',(30.628611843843,-2.97922138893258,13.0062521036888));
#417=CARTESIAN_POINT('',(30.5270824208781,-2.89441099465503,13.0012106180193));
#418=CARTESIAN_POINT('',(30.4770736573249,-2.85117575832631,13.0000016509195));
#419=CARTESIAN_POINT('',(30.4277694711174,-2.80714065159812,12.9999999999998));
#420=B_SPLINE_CURVE_WITH_KNOTS('',3,(#380,#381,#382,#383,#384,#385,#386,#387,#388,#389,#390,
#391,#392,#393,#394,#395,#396,#397,#398,#399,#400,#401,#402,#403,#404,#405,#406,#407,#408,#409,
#410,#411,#412,#413,#414,#415,#416,#417,#418,#419),.UNSPECIFIED.,.F.,.F.,(4,2,2,2,2,2,2,2,2,2,2,
2,2,2,2,2,2,2,2,4),(0.,0.299698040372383,0.59964577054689,1.20498031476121,1.50964069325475,
1.81410045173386,2.11750656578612,2.42083535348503,2.68159295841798,2.94229623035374,
3.20288438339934,3.46343604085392,3.6840311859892,3.90469069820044,4.1252309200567,
4.34585377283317,4.78744512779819,5.22923640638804,5.42810702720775,5.62638394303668),.UNSPECIFIED.);
#421=CARTESIAN_POINT('',(33.9061492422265,-3.11665429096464,16.2650726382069));
#422=VERTEX_POINT('',#421);
#423=EDGE_CURVE('E411',#422,#377,#420,.T.);
#424=ORIENTED_EDGE('',*,*,#423,.F.);
#425=EDGE_CURVE('E452',#373,#422,#127,.T.);
#426=ORIENTED_EDGE('',*,*,#425,.F.);
#427=EDGE_LOOP('',(#375,#379,#424,#426));
#428=FACE_BOUND('',#427,.T.);
#429=ADVANCED_FACE('F201',(#428),#23,.T.);
#430=CARTESIAN_POINT('',(26.196500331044,15.7312607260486,12.9999999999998));
#431=CARTESIAN_POINT('',(26.2296262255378,15.8111818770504,12.9999995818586));
#432=CARTESIAN_POINT('',(26.2644626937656,15.8904350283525,13.002073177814));
#433=CARTESIAN_POINT('',(26.3376190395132,16.0471731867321,13.010813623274));
#434=CARTESIAN_POINT('',(26.3759432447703,16.1246558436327,13.017486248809));
#435=CARTESIAN_POINT('',(26.4564160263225,16.2779064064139,13.0359552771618));
#436=CARTESIAN_POINT('',(26.4985960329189,16.3536524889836,13.0477974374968));
#437=CARTESIAN_POINT('',(26.5863719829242,16.5020079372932,13.0770311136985));
#438=CARTESIAN_POINT('',(26.631966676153,16.5746184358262,13.0944206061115));
#439=CARTESIAN_POINT('',(26.7267670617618,16.7165803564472,13.1352731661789));
#440=CARTESIAN_POINT('',(26.7759991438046,16.7859004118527,13.1587845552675));
#441=CARTESIAN_POINT('',(26.8773860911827,16.9198370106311,13.212063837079));
#442=CARTESIAN_POINT('',(26.9295404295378,16.9844543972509,13.2418306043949));
#443=CARTESIAN_POINT('',(27.0360610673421,17.1079457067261,13.307587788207));
#444=CARTESIAN_POINT('',(27.0904169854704,17.1668429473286,13.3435511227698));
#445=CARTESIAN_POINT('',(27.2009309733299,17.2784808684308,13.42171350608));
#446=CARTESIAN_POINT('',(27.2570887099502,17.3312226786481,13.4639114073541));
#447=CARTESIAN_POINT('',(27.3628431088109,17.4232937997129,13.5481801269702));
#448=CARTESIAN_POINT('',(27.412302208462,17.4634725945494,13.5894992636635));
#449=CARTESIAN_POINT('',(27.5115806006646,17.5385193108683,13.6763591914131));
#450=CARTESIAN_POINT('',(27.5614000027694,17.5733855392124,13.7219013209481));
#451=CARTESIAN_POINT('',(27.6609368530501,17.6376309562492,13.8168914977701));
#452=CARTESIAN_POINT('',(27.7106542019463,17.6670061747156,13.8663423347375));
#453=CARTESIAN_POINT('',(27.8094987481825,17.7201716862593,13.9687276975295));
#454=CARTESIAN_POINT('',(27.8586257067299,17.7439597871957,14.0216635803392));
#455=CARTESIAN_POINT('',(27.9999603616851,17.8049848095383,14.1800128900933));
#456=CARTESIAN_POINT('',(28.0908714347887,17.8348785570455,14.2895168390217));
#457=CARTESIAN_POINT('',(28.266485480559,17.8751553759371,14.5165356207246));
#458=CARTESIAN_POINT('',(28.3511899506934,17.8855431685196,14.6340485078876));
#459=CARTESIAN_POINT('',(28.5217934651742,17.8884820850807,14.8877018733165));
#460=CARTESIAN_POINT('',(28.6067938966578,17.8789396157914,15.0244673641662));
#461=CARTESIAN_POINT('',(28.7659988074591,17.8399115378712,15.3014973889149));
#462=CARTESIAN_POINT('',(28.8401906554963,17.8104028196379,15.4417657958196));
#463=CARTESIAN_POINT('',(28.9642625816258,17.7408357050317,15.6966901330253));
#464=CARTESIAN_POINT('',(29.0160958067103,17.703774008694,15.8112404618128));
#465=CARTESIAN_POINT('',(29.1119132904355,17.6191495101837,16.0391889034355));
#466=CARTESIAN_POINT('',(29.1559264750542,17.5716269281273,16.15258973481));
#467=CARTESIAN_POINT('',(29.196119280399,17.5193353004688,16.2650726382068));
#468=B_SPLINE_CURVE_WITH_KNOTS('',3,(#430,#431,#432,#433,#434,#435,#436,#437,#438,#439,#440,
#441,#442,#443,#444,#445,#446,#447,#448,#449,#450,#451,#452,#453,#454,#455,#456,#457,#458,#459,
#460,#461,#462,#463,#464,#465,#466,#467),.UNSPECIFIED.,.F.,.F.,(4,2,2,2,2,2,2,2,2,2,2,2,2,2,2,2,
2,2,4),(0.,0.259555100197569,0.519436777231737,0.781666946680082,1.0438015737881,
1.30807155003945,1.57229402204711,1.83538972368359,2.09843706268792,2.32597812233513,
2.55359154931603,2.78136891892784,3.00923550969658,3.44356210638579,3.87778356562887,
4.35989598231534,4.84256736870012,5.23515773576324,5.62626424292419),.UNSPECIFIED.);
#469=CARTESIAN_POINT('',(26.196500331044,15.7312607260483,12.9999999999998));
#470=VERTEX_POINT('',#469);
#471=CARTESIAN_POINT('',(29.1961192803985,17.5193353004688,16.2650726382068));
#472=VERTEX_POINT('',#471);
#473=EDGE_CURVE('E435',#470,#472,#468,.T.);
#474=ORIENTED_EDGE('',*,*,#473,.F.);
#475=CARTESIAN_POINT('',(21.166114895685,22.0391645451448,12.9999999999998));
#476=VERTEX_POINT('',#475);
#477=EDGE_CURVE('E219',#470,#476,#73,.T.);
#478=ORIENTED_EDGE('',*,*,#477,.T.);
#479=CARTESIAN_POINT('',(23.5768367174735,24.5656927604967,16.2650726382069));
#480=CARTESIAN_POINT('',(23.6090512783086,24.5267209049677,16.1788472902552));
#481=CARTESIAN_POINT('',(23.6380276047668,24.486234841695,16.092150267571));
#482=CARTESIAN_POINT('',(23.6890888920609,24.4022226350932,15.9181115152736));
#483=CARTESIAN_POINT('',(23.7111680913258,24.3586939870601,15.8307693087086));
#484=CARTESIAN_POINT('',(23.7666972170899,24.2228115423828,15.5668553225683));
#485=CARTESIAN_POINT('',(23.7888368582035,24.1258688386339,15.389974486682));
#486=CARTESIAN_POINT('',(23.7965258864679,23.9728135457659,15.1279647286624));
#487=CARTESIAN_POINT('',(23.7947876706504,23.9203378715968,15.0409016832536));
#488=CARTESIAN_POINT('',(23.782214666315,23.8132823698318,14.8687696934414));
#489=CARTESIAN_POINT('',(23.7713858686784,23.7587039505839,14.7836994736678));
#490=CARTESIAN_POINT('',(23.7402313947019,23.6481367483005,14.616681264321));
#491=CARTESIAN_POINT('',(23.7199387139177,23.5921534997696,14.5347234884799));
#492=CARTESIAN_POINT('',(23.6695106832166,23.4792502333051,14.3745637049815));
#493=CARTESIAN_POINT('',(23.6393778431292,23.4223304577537,14.2963607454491));
#494=CARTESIAN_POINT('',(23.5740120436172,23.3163525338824,14.1553613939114));
#495=CARTESIAN_POINT('',(23.5400884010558,23.2673121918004,14.0919431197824));
#496=CARTESIAN_POINT('',(23.46483579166,23.1697099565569,13.9692748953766));
#497=CARTESIAN_POINT('',(23.4235083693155,23.1211479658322,13.9100240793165));
#498=CARTESIAN_POINT('',(23.333631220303,23.0251491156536,13.7963342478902));
#499=CARTESIAN_POINT('',(23.2850846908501,22.9777117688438,13.7418931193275));
#500=CARTESIAN_POINT('',(23.1811030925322,22.88459355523,13.6383551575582));
#501=CARTESIAN_POINT('',(23.125668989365,22.83891244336,13.5892575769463));
#502=CARTESIAN_POINT('',(23.0174408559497,22.7567620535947,13.5039379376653));
#503=CARTESIAN_POINT('',(22.9655456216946,22.719954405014,13.4668960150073));
#504=CARTESIAN_POINT('',(22.8575881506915,22.6483758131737,13.3971240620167));
#505=CARTESIAN_POINT('',(22.8015247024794,22.6136054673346,13.3643952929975));
#506=CARTESIAN_POINT('',(22.685741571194,22.5464262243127,13.3033769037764));
#507=CARTESIAN_POINT('',(22.6260238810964,22.5140160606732,13.2750848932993));
#508=CARTESIAN_POINT('',(22.5033994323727,22.4517563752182,13.2229137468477));
#509=CARTESIAN_POINT('',(22.4404914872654,22.4219078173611,13.1990362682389));
#510=CARTESIAN_POINT('',(22.2475868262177,22.3364013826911,13.1338837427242));
#511=CARTESIAN_POINT('',(22.11350144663,22.2848359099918,13.0991362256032));
#512=CARTESIAN_POINT('',(21.8384679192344,22.1932314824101,13.0457059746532));
#513=CARTESIAN_POINT('',(21.697516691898,22.153197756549,13.0270305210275));
#514=CARTESIAN_POINT('',(21.4905019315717,22.1032641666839,13.0100924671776));
#515=CARTESIAN_POINT('',(21.4258762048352,22.088898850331,13.0062521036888));
#516=CARTESIAN_POINT('',(21.2962662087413,22.062398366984,13.0012106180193));
#517=CARTESIAN_POINT('',(21.2312835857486,22.0502566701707,13.0000016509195));
#518=CARTESIAN_POINT('',(21.1661148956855,22.0391645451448,12.9999999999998));
#519=B_SPLINE_CURVE_WITH_KNOTS('',3,(#479,#480,#481,#482,#483,#484,#485,#486,#487,#488,#489,
#490,#491,#492,#493,#494,#495,#496,#497,#498,#499,#500,#501,#502,#503,#504,#505,#506,#507,#508,
#509,#510,#511,#512,#513,#514,#515,#516,#517,#518),.UNSPECIFIED.,.F.,.F.,(4,2,2,2,2,2,2,2,2,2,2,
2,2,2,2,2,2,2,2,4),(0.,0.299698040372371,0.599645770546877,1.20498031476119,1.50964069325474,
1.81410045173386,2.11750656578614,2.42083535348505,2.68159295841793,2.94229623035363,
3.20288438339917,3.46343604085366,3.68403118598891,3.90469069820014,4.12523092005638,
4.34585377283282,4.78744512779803,5.22923640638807,5.42810702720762,5.62638394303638),.UNSPECIFIED.);
#520=CARTESIAN_POINT('',(23.5768367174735,24.5656927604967,16.2650726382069));
#521=VERTEX_POINT('',#520);
#522=EDGE_CURVE('E288',#521,#476,#519,.T.);
#523=ORIENTED_EDGE('',*,*,#522,.F.);
#524=EDGE_CURVE('E444',#472,#521,#127,.T.);
#525=ORIENTED_EDGE('',*,*,#524,.F.);
#526=EDGE_LOOP('',(#474,#478,#523,#525));
#527=FACE_BOUND('',#526,.T.);
#528=ADVANCED_FACE('F194',(#527),#23,.T.);
#529=CARTESIAN_POINT('',(4.034055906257,30.2895293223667,12.9999999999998));
#530=CARTESIAN_POINT('',(3.992224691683,30.3652582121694,12.9999995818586));
#531=CARTESIAN_POINT('',(3.95198226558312,30.4419079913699,13.002073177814));
#532=CARTESIAN_POINT('',(3.87505167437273,30.5968285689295,13.010813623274));
#533=CARTESIAN_POINT('',(3.83836804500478,30.6751012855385,13.017486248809));
#534=CARTESIAN_POINT('',(3.76872588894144,30.8335676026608,13.0359552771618));
#535=CARTESIAN_POINT('',(3.73580402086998,30.9137721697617,13.0477974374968));
#536=CARTESIAN_POINT('',(3.67454247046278,31.0748962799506,13.0770311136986));
#537=CARTESIAN_POINT('',(3.64620112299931,31.1558155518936,13.0944206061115));
#538=CARTESIAN_POINT('',(3.59431789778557,31.3184452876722,13.1352731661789));
#539=CARTESIAN_POINT('',(3.57081699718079,31.4001568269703,13.1587845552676));
#540=CARTESIAN_POINT('',(3.52931487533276,31.5629324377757,13.2120638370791));
#541=CARTESIAN_POINT('',(3.51131266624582,31.6439966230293,13.2418306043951));
#542=CARTESIAN_POINT('',(3.48117780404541,31.8042733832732,13.3075877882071));
#543=CARTESIAN_POINT('',(3.46902044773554,31.8834923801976,13.34355112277));
#544=CARTESIAN_POINT('',(3.45064275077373,32.0395008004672,13.4217135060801));
#545=CARTESIAN_POINT('',(3.44442131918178,32.1162906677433,13.4639114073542));
#546=CARTESIAN_POINT('',(3.43837400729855,32.2563781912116,13.5481801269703));
#547=CARTESIAN_POINT('',(3.43779820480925,32.3200979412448,13.5894992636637));
#548=CARTESIAN_POINT('',(3.44102338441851,32.4445077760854,13.6763591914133));
#549=CARTESIAN_POINT('',(3.44482575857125,32.5051968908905,13.7219013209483));
#550=CARTESIAN_POINT('',(3.45665687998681,32.6230742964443,13.8168914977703));
#551=CARTESIAN_POINT('',(3.46468866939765,32.6802600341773,13.8663423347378));
#552=CARTESIAN_POINT('',(3.48475076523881,32.7906879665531,13.9687276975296));
#553=CARTESIAN_POINT('',(3.4967826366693,32.8439286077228,14.0216635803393));
#554=CARTESIAN_POINT('',(3.53719206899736,32.9924769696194,14.1800128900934));
#555=CARTESIAN_POINT('',(3.5705023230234,33.0821925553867,14.2895168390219));
#556=CARTESIAN_POINT('',(3.6485062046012,33.2446053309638,14.5165356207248));
#557=CARTESIAN_POINT('',(3.69319707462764,33.3173066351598,14.6340485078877));
#558=CARTESIAN_POINT('',(3.79726888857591,33.452522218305,14.8877018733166));
#559=CARTESIAN_POINT('',(3.8577263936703,33.5130285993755,15.0244673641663));
#560=CARTESIAN_POINT('',(3.98750241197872,33.613166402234,15.3014973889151));
#561=CARTESIAN_POINT('',(4.05683111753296,33.6527735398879,15.4417657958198));
#562=CARTESIAN_POINT('',(4.18857845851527,33.7064024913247,15.6966901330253));
#563=CARTESIAN_POINT('',(4.24987194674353,33.7238197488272,15.8112404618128));
#564=CARTESIAN_POINT('',(4.37577526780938,33.7459703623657,16.0391889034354));
#565=CARTESIAN_POINT('',(4.44037169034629,33.750751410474,16.15258973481));
#566=CARTESIAN_POINT('',(4.50631473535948,33.7495721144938,16.2650726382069));
#567=B_SPLINE_CURVE_WITH_KNOTS('',3,(#529,#530,#531,#532,#533,#534,#535,#536,#537,#538,#539,
#540,#541,#542,#543,#544,#545,#546,#547,#548,#549,#550,#551,#552,#553,#554,#555,#556,#557,#558,
#559,#560,#561,#562,#563,#564,#565,#566),.UNSPECIFIED.,.F.,.F.,(4,2,2,2,2,2,2,2,2,2,2,2,2,2,2,2,
2,2,4),(0.,0.25955510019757,0.519436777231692,0.781666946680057,1.04380157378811,
1.3080715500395,1.57229402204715,1.83538972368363,2.09843706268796,2.32597812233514,
2.55359154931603,2.78136891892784,3.00923550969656,3.44356210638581,3.87778356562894,
4.35989598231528,4.84256736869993,5.23515773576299,5.62626424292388),.UNSPECIFIED.);
#568=CARTESIAN_POINT('',(4.0340559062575,30.2895293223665,12.9999999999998));
#569=VERTEX_POINT('',#568);
#570=CARTESIAN_POINT('',(4.50631473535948,33.7495721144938,16.2650726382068));
#571=VERTEX_POINT('',#570);
#572=EDGE_CURVE('E205',#569,#571,#567,.T.);
#573=ORIENTED_EDGE('',*,*,#572,.F.);
#574=CARTESIAN_POINT('',(-4.0340559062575,30.2895293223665,12.9999999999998));
#575=VERTEX_POINT('',#574);
#576=EDGE_CURVE('E135',#569,#575,#73,.T.);
#577=ORIENTED_EDGE('',*,*,#576,.T.);
#578=CARTESIAN_POINT('',(-4.50631473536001,33.7495721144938,16.2650726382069));
#579=CARTESIAN_POINT('',(-4.45575986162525,33.7504599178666,16.1788472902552));
#580=CARTESIAN_POINT('',(-4.40604013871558,33.7478718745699,16.092150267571));
#581=CARTESIAN_POINT('',(-4.30852055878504,33.7354124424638,15.9181115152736));
#582=CARTESIAN_POINT('',(-4.26072233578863,33.7255349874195,15.8307693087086));
#583=CARTESIAN_POINT('',(-4.11986331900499,33.684228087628,15.5668553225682));
#584=CARTESIAN_POINT('',(-4.03026662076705,33.6410947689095,15.389974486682));
#585=CARTESIAN_POINT('',(-3.90580914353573,33.5516778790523,15.1279647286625));
#586=CARTESIAN_POINT('',(-3.86586576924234,33.5176008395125,15.0409016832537));
#587=CARTESIAN_POINT('',(-3.79000554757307,33.4410228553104,14.8687696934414));
#588=CARTESIAN_POINT('',(-3.7540860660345,33.3985274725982,14.7836994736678));
#589=CARTESIAN_POINT('',(-3.68706564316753,33.30523240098,14.616681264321));
#590=CARTESIAN_POINT('',(-3.65594845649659,33.2544619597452,14.5347234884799));
#591=CARTESIAN_POINT('',(-3.599118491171,33.1446417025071,14.3745637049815));
#592=CARTESIAN_POINT('',(-3.57340433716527,33.0855939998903,14.2963607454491));
#593=CARTESIAN_POINT('',(-3.53130236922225,32.9684128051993,14.1553613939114));
#594=CARTESIAN_POINT('',(-3.51411213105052,32.9113140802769,14.0919431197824));
#595=CARTESIAN_POINT('',(-3.48472286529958,32.7916252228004,13.9692748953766));
#596=CARTESIAN_POINT('',(-3.47252279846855,32.7290362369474,13.9100240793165));
#597=CARTESIAN_POINT('',(-3.45350536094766,32.5989131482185,13.7963342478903));
#598=CARTESIAN_POINT('',(-3.44668561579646,32.5313812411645,13.7418931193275));
#599=CARTESIAN_POINT('',(-3.43871433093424,32.3920268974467,13.6383551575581));
#600=CARTESIAN_POINT('',(-3.43756199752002,32.3202050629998,13.5892575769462));
#601=CARTESIAN_POINT('',(-3.44081337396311,32.1843689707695,13.5039379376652));
#602=CARTESIAN_POINT('',(-3.44439214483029,32.1208464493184,13.4668960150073));
#603=CARTESIAN_POINT('',(-3.45574013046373,31.9918133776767,13.3971240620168));
#604=CARTESIAN_POINT('',(-3.46351056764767,31.926302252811,13.3643952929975));
#605=CARTESIAN_POINT('',(-3.48317732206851,31.7938937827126,13.3033769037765));
#606=CARTESIAN_POINT('',(-3.49507140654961,31.7269972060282,13.2750848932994));
#607=CARTESIAN_POINT('',(-3.52284991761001,31.5923072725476,13.2229137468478));
#608=CARTESIAN_POINT('',(-3.53873583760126,31.5245135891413,13.1990362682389));
#609=CARTESIAN_POINT('',(-3.5921583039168,31.3203822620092,13.1338837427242));
#610=CARTESIAN_POINT('',(-3.63544366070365,31.183399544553,13.0991362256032));
#611=CARTESIAN_POINT('',(-3.73530503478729,30.9112552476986,13.0457059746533));
#612=CARTESIAN_POINT('',(-3.79188706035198,30.7760945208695,13.0270305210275));
#613=CARTESIAN_POINT('',(-3.88191899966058,30.5831107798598,13.0100924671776));
#614=CARTESIAN_POINT('',(-3.91098122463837,30.5236277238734,13.0062521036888));
#615=CARTESIAN_POINT('',(-3.97107282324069,30.4057717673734,13.0012106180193));
#616=CARTESIAN_POINT('',(-4.00209606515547,30.347396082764,13.0000016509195));
#617=CARTESIAN_POINT('',(-4.0340559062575,30.2895293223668,12.9999999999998));
#618=B_SPLINE_CURVE_WITH_KNOTS('',3,(#578,#579,#580,#581,#582,#583,#584,#585,#586,#587,#588,
#589,#590,#591,#592,#593,#594,#595,#596,#597,#598,#599,#600,#601,#602,#603,#604,#605,#606,#607,
#608,#609,#610,#611,#612,#613,#614,#615,#616,#617),.UNSPECIFIED.,.F.,.F.,(4,2,2,2,2,2,2,2,2,2,2,
2,2,2,2,2,2,2,2,4),(0.,0.299698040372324,0.599645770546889,1.20498031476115,1.50964069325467,
1.81410045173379,2.11750656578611,2.42083535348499,2.68159295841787,2.94229623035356,
3.20288438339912,3.46343604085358,3.6840311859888,3.90469069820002,4.12523092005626,
4.34585377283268,4.78744512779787,5.2292364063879,5.42810702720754,5.6263839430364),.UNSPECIFIED.);
#619=CARTESIAN_POINT('',(-4.50631473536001,33.7495721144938,16.2650726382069));
#620=VERTEX_POINT('',#619);
#621=EDGE_CURVE('E272',#620,#575,#618,.T.);
#622=ORIENTED_EDGE('',*,*,#621,.F.);
#623=EDGE_CURVE('E134',#571,#620,#127,.T.);
#624=ORIENTED_EDGE('',*,*,#623,.F.);
#625=EDGE_LOOP('',(#573,#577,#622,#624));
#626=FACE_BOUND('',#625,.T.);
#627=ADVANCED_FACE('F186',(#626),#23,.T.);
#628=CARTESIAN_POINT('',(0.,0.,300.557123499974));
#629=DIRECTION('',(0.,1.,0.));
#630=DIRECTION('',(-1.,0.,0.));
#631=AXIS2_PLACEMENT_3D('',#628,#629,#630);
#632=SPHERICAL_SURFACE('',#631,267.395705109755);
#633=CARTESIAN_POINT('',(0.,0.,300.557123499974));
#634=DIRECTION('',(0.,0.,1.));
#635=DIRECTION('',(0.,1.,0.));
#636=AXIS2_PLACEMENT_3D('',#633,#634,#635);
#637=SPHERICAL_SURFACE('',#636,267.395705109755);
#638=CARTESIAN_POINT('',(0.,0.,34.9762453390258));
#639=DIRECTION('',(0.,0.,1.));
#640=DIRECTION('',(0.,1.,0.));
#641=AXIS2_PLACEMENT_3D('',#638,#639,#640);
#642=CIRCLE('',#641,31.1008081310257);
#643=CARTESIAN_POINT('',(0.,31.1008081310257,34.9762453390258));
#644=VERTEX_POINT('',#643);
#645=EDGE_CURVE('E9',#644,#644,#642,.T.);
#646=ORIENTED_EDGE('',*,*,#645,.T.);
#647=EDGE_LOOP('',(#646));
#648=FACE_BOUND('',#647,.T.);
#649=ADVANCED_FACE('F16',(#648),#637,.F.);
#650=CARTESIAN_POINT('',(0.,0.,31.5));
#651=DIRECTION('',(0.,0.,1.));
#652=DIRECTION('',(0.,1.,0.));
#653=AXIS2_PLACEMENT_3D('',#650,#651,#652);
#654=TOROIDAL_SURFACE('',#653,31.5078933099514,3.50000000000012);
#655=CARTESIAN_POINT('',(0.,0.,31.2650726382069));
#656=DIRECTION('',(0.,0.,1.));
#657=DIRECTION('',(0.,1.,0.));
#658=AXIS2_PLACEMENT_3D('',#655,#656,#657);
#659=CIRCLE('',#658,35.);
#660=CARTESIAN_POINT('',(0.,35.,31.2650726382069));
#661=VERTEX_POINT('',#660);
#662=EDGE_CURVE('E22',#661,#661,#659,.T.);
#663=ORIENTED_EDGE('',*,*,#662,.T.);
#664=EDGE_LOOP('',(#663));
#665=FACE_BOUND('',#664,.T.);
#666=ORIENTED_EDGE('',*,*,#645,.F.);
#667=EDGE_LOOP('',(#666));
#668=FACE_BOUND('',#667,.T.);
#669=ADVANCED_FACE('F155',(#665,#668),#654,.T.);
#670=CARTESIAN_POINT('',(35.,0.,31.2650726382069));
#671=DIRECTION('',(0.,0.,-1.));
#672=DIRECTION('',(0.,-1.,0.));
#673=AXIS2_PLACEMENT_3D('',#670,#671,#672);
#674=PLANE('',#673);
#675=CARTESIAN_POINT('',(0.,0.,31.2650726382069));
#676=DIRECTION('',(0.,0.,1.));
#677=DIRECTION('',(0.,1.,0.));
#678=AXIS2_PLACEMENT_3D('',#675,#676,#677);
#679=CIRCLE('',#678,34.3087135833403);
#680=CARTESIAN_POINT('',(0.,34.3087135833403,31.2650726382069));
#681=VERTEX_POINT('',#680);
#682=EDGE_CURVE('E150',#681,#681,#679,.T.);
#683=ORIENTED_EDGE('',*,*,#682,.T.);
#684=EDGE_LOOP('',(#683));
#685=FACE_BOUND('',#684,.T.);
#686=ORIENTED_EDGE('',*,*,#662,.F.);
#687=EDGE_LOOP('',(#686));
#688=FACE_BOUND('',#687,.T.);
#689=ADVANCED_FACE('F158',(#685,#688),#674,.T.);
#690=CARTESIAN_POINT('',(0.,0.,39.4436305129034));
#691=DIRECTION('',(0.,0.,1.));
#692=DIRECTION('',(0.,1.,0.));
#693=AXIS2_PLACEMENT_3D('',#690,#691,#692);
#694=CYLINDRICAL_SURFACE('',#693,34.3087135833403);
#695=CARTESIAN_POINT('',(0.,0.,30.4));
#696=DIRECTION('',(0.,0.,1.));
#697=DIRECTION('',(0.,1.,0.));
#698=AXIS2_PLACEMENT_3D('',#695,#696,#697);
#699=CIRCLE('',#698,34.3087135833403);
#700=CARTESIAN_POINT('',(0.,34.3087135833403,30.4));
#701=VERTEX_POINT('',#700);
#702=EDGE_CURVE('E147',#701,#701,#699,.T.);
#703=ORIENTED_EDGE('',*,*,#702,.T.);
#704=EDGE_LOOP('',(#703));
#705=FACE_BOUND('',#704,.T.);
#706=ORIENTED_EDGE('',*,*,#682,.F.);
#707=EDGE_LOOP('',(#706));
#708=FACE_BOUND('',#707,.T.);
#709=ADVANCED_FACE('F160',(#705,#708),#694,.T.);
#710=CARTESIAN_POINT('',(35.,0.,30.4));
#711=DIRECTION('',(0.,0.,-1.));
#712=DIRECTION('',(0.,-1.,0.));
#713=AXIS2_PLACEMENT_3D('',#710,#711,#712);
#714=PLANE('',#713);
#715=ORIENTED_EDGE('',*,*,#702,.F.);
#716=EDGE_LOOP('',(#715));
#717=FACE_BOUND('',#716,.T.);
#718=CARTESIAN_POINT('',(0.,0.,30.4));
#719=DIRECTION('',(0.,0.,1.));
#720=DIRECTION('',(0.,1.,0.));
#721=AXIS2_PLACEMENT_3D('',#718,#719,#720);
#722=CIRCLE('',#721,35.);
#723=CARTESIAN_POINT('',(0.,35.,30.4));
#724=VERTEX_POINT('',#723);
#725=EDGE_CURVE('E144',#724,#724,#722,.T.);
#726=ORIENTED_EDGE('',*,*,#725,.T.);
#727=EDGE_LOOP('',(#726));
#728=FACE_BOUND('',#727,.T.);
#729=ADVANCED_FACE('F168',(#717,#728),#714,.F.);
#730=CARTESIAN_POINT('',(0.,0.,30.4));
#731=DIRECTION('',(0.,0.,1.));
#732=DIRECTION('',(0.,1.,0.));
#733=AXIS2_PLACEMENT_3D('',#730,#731,#732);
#734=CONICAL_SURFACE('',#733,35.,0.0671726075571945);
#735=CARTESIAN_POINT('',(-33.906149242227,-3.11665429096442,16.2650726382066));
#736=CARTESIAN_POINT('',(-33.9393467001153,-2.95826828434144,16.5409887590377));
#737=CARTESIAN_POINT('',(-33.9714497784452,-2.79918872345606,16.8166398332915));
#738=CARTESIAN_POINT('',(-34.0334250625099,-2.47949565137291,17.3673394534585));
#739=CARTESIAN_POINT('',(-34.0632970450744,-2.31888198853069,17.6423879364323));
#740=CARTESIAN_POINT('',(-34.1207624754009,-1.99599927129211,18.1917653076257));
#741=CARTESIAN_POINT('',(-34.1483558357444,-1.8337301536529,18.4660941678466));
#742=CARTESIAN_POINT('',(-34.2013320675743,-1.50659289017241,19.0152039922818));
#743=CARTESIAN_POINT('',(-34.2267037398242,-1.34171602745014,19.2899808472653));
#744=CARTESIAN_POINT('',(-34.2750170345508,-1.0099200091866,19.8385022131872));
#745=CARTESIAN_POINT('',(-34.2979587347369,-0.843000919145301,20.1122467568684));
#746=CARTESIAN_POINT('',(-34.3413253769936,-0.50685566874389,20.6585050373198));
#747=CARTESIAN_POINT('',(-34.361750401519,-0.337629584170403,20.9310188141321));
#748=CARTESIAN_POINT('',(-34.3999797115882,0.0035079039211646,21.4746325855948));
#749=CARTESIAN_POINT('',(-34.4177834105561,0.175419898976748,21.745732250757));
#750=CARTESIAN_POINT('',(-34.4506258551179,0.522326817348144,22.2861377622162));
#751=CARTESIAN_POINT('',(-34.4656645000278,0.697321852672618,22.5554435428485));
#752=CARTESIAN_POINT('',(-34.4927969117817,1.05097097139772,23.0918561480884));
#753=CARTESIAN_POINT('',(-34.5048902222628,1.2296256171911,23.3589626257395));
#754=CARTESIAN_POINT('',(-34.5258619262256,1.59084035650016,23.8896676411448));
#755=CARTESIAN_POINT('',(-34.5347483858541,1.7733894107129,24.1532733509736));
#756=CARTESIAN_POINT('',(-34.549022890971,2.14377947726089,24.6767996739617));
#757=CARTESIAN_POINT('',(-34.5544113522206,2.33161985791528,24.9367207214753));
#758=CARTESIAN_POINT('',(-34.5612398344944,2.71389556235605,25.4516580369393));
#759=CARTESIAN_POINT('',(-34.5626808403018,2.90832922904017,25.7066755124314));
#760=CARTESIAN_POINT('',(-34.5613217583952,3.22074444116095,26.1023739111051));
#761=CARTESIAN_POINT('',(-34.5600716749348,3.33586665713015,26.2453176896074));
#762=CARTESIAN_POINT('',(-34.5558874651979,3.56938287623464,26.5285004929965));
#763=CARTESIAN_POINT('',(-34.5529532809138,3.68777699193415,26.6687394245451));
#764=CARTESIAN_POINT('',(-34.5451733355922,3.92877927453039,26.9462743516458));
#765=CARTESIAN_POINT('',(-34.5403216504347,4.05139941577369,27.0835598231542));
#766=CARTESIAN_POINT('',(-34.5284236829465,4.30121697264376,27.3538044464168));
#767=CARTESIAN_POINT('',(-34.5213775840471,4.42841400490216,27.4867639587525));
#768=CARTESIAN_POINT('',(-34.504630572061,4.68967078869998,27.7484650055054));
#769=CARTESIAN_POINT('',(-34.4949022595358,4.82378907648,27.8771467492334));
#770=CARTESIAN_POINT('',(-34.4723085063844,5.09883850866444,28.1269528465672));
#771=CARTESIAN_POINT('',(-34.4594414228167,5.23977318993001,28.2480732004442));
#772=CARTESIAN_POINT('',(-34.4299617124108,5.52910245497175,28.4793900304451));
#773=CARTESIAN_POINT('',(-34.4133645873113,5.67746424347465,28.5896290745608));
#774=CARTESIAN_POINT('',(-34.3755527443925,5.98339134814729,28.795534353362));
#775=CARTESIAN_POINT('',(-34.3543446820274,6.14094316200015,28.8912212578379));
#776=CARTESIAN_POINT('',(-34.3189861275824,6.38042663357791,29.017156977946));
#777=CARTESIAN_POINT('',(-34.3069948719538,6.45852149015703,29.0553432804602));
#778=CARTESIAN_POINT('',(-34.2816618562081,6.61691830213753,29.1263522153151));
#779=CARTESIAN_POINT('',(-34.2683201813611,6.69722011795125,29.1591751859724));
#780=CARTESIAN_POINT('',(-34.2402333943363,6.85974086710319,29.218586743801));
#781=CARTESIAN_POINT('',(-34.2254903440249,6.94195685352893,29.2451842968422));
#782=CARTESIAN_POINT('',(-34.1945535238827,7.10806058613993,29.2913802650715));
#783=CARTESIAN_POINT('',(-34.178360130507,7.19194789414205,29.3109804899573));
#784=CARTESIAN_POINT('',(-34.1443516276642,7.36183929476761,29.3426542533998));
#785=CARTESIAN_POINT('',(-34.1265203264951,7.44785658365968,29.3546406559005));
#786=CARTESIAN_POINT('',(-34.089490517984,7.62035820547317,29.3702307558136));
#787=CARTESIAN_POINT('',(-34.0702920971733,7.70684250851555,29.3738349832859));
#788=CARTESIAN_POINT('',(-34.0306846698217,7.87949619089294,29.3725008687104));
#789=CARTESIAN_POINT('',(-34.0102752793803,7.96566546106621,29.3675598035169));
#790=CARTESIAN_POINT('',(-33.9684616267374,8.13687234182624,29.3493497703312));
#791=CARTESIAN_POINT('',(-33.9470572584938,8.2219098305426,29.3360799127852));
#792=CARTESIAN_POINT('',(-33.9014357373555,8.39808145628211,29.3001466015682));
#793=CARTESIAN_POINT('',(-33.8771430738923,8.48903923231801,29.2767187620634));
#794=CARTESIAN_POINT('',(-33.8279129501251,8.66820315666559,29.2215580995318));
#795=CARTESIAN_POINT('',(-33.8029753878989,8.75640886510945,29.1898239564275));
#796=CARTESIAN_POINT('',(-33.7526395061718,8.92989590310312,29.1191196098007));
#797=CARTESIAN_POINT('',(-33.7272404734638,9.01517198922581,29.0801371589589));
#798=CARTESIAN_POINT('',(-33.6761916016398,9.18255650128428,28.9960693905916));
#799=CARTESIAN_POINT('',(-33.6505417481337,9.26466474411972,28.950983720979));
#800=CARTESIAN_POINT('',(-33.578620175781,9.48997374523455,28.817752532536));
#801=CARTESIAN_POINT('',(-33.5321917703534,9.62975782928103,28.7239071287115));
#802=CARTESIAN_POINT('',(-33.4392524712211,9.90048575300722,28.5242616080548));
#803=CARTESIAN_POINT('',(-33.3927415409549,10.0314212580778,28.4184504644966));
#804=CARTESIAN_POINT('',(-33.299625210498,10.2861237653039,28.1977099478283));
#805=CARTESIAN_POINT('',(-33.2530200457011,10.4098642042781,28.0827500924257));
#806=CARTESIAN_POINT('',(-33.1599210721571,10.650824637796,27.8463236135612));
#807=CARTESIAN_POINT('',(-33.1134272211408,10.7680476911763,27.7248600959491));
#808=CARTESIAN_POINT('',(-33.0207407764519,10.9964610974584,27.4775702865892));
#809=CARTESIAN_POINT('',(-32.9745478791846,11.1076798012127,27.3517701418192));
#810=CARTESIAN_POINT('',(-32.8821676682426,11.3255722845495,27.0962769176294));
#811=CARTESIAN_POINT('',(-32.8359803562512,11.4322454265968,26.9665832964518));
#812=CARTESIAN_POINT('',(-32.7435072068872,11.6418312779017,26.7039359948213));
#813=CARTESIAN_POINT('',(-32.6972213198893,11.7447388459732,26.5709782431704));
#814=CARTESIAN_POINT('',(-32.6045627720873,11.9471823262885,26.3025448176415));
#815=CARTESIAN_POINT('',(-32.5581901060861,12.0467180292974,26.1670689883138));
#816=CARTESIAN_POINT('',(-32.418722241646,12.341265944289,25.7571058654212));
#817=CARTESIAN_POINT('',(-32.3254298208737,12.5318754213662,25.4795205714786));
#818=CARTESIAN_POINT('',(-32.1380171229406,12.904016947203,24.9185263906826));
#819=CARTESIAN_POINT('',(-32.043896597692,13.0855461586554,24.6351157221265));
#820=CARTESIAN_POINT('',(-31.8542113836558,13.4420419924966,24.0627757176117));
#821=CARTESIAN_POINT('',(-31.7586421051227,13.616975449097,23.7738273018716));
#822=CARTESIAN_POINT('',(-31.5664436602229,13.9604607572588,23.1930961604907));
#823=CARTESIAN_POINT('',(-31.4698161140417,14.1290209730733,22.9013178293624));
#824=CARTESIAN_POINT('',(-31.2753127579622,14.4608312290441,22.3154416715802));
#825=CARTESIAN_POINT('',(-31.1774377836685,14.6240845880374,22.0213454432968));
#826=CARTESIAN_POINT('',(-30.9802918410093,14.9460742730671,21.4311813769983));
#827=CARTESIAN_POINT('',(-30.8810209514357,15.1048108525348,21.1351136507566));
#828=CARTESIAN_POINT('',(-30.7171654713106,15.3616251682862,20.6487047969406));
#829=CARTESIAN_POINT('',(-30.6530164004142,15.4608845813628,20.458839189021));
#830=CARTESIAN_POINT('',(-30.5240889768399,15.6579085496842,20.0784855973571));
#831=CARTESIAN_POINT('',(-30.4593104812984,15.7556727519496,19.8879974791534));
#832=CARTESIAN_POINT('',(-30.3291158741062,15.9497924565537,19.5064794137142));
#833=CARTESIAN_POINT('',(-30.2636996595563,16.0461477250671,19.315449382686));
#834=CARTESIAN_POINT('',(-30.132223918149,16.2375213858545,18.9329190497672));
#835=CARTESIAN_POINT('',(-30.0661643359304,16.3325396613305,18.7414187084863));
#836=CARTESIAN_POINT('',(-29.9340782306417,16.5203334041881,18.3599760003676));
#837=CARTESIAN_POINT('',(-29.8680582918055,16.6131218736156,18.1700377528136));
#838=CARTESIAN_POINT('',(-29.7353836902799,16.797497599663,17.7898226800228));
#839=CARTESIAN_POINT('',(-29.6687290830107,16.8890849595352,17.5995458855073));
#840=CARTESIAN_POINT('',(-29.534785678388,17.0711002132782,17.2187081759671));
#841=CARTESIAN_POINT('',(-29.4674969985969,17.1615283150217,17.0281473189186));
#842=CARTESIAN_POINT('',(-29.3322877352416,17.341258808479,16.6467913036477));
#843=CARTESIAN_POINT('',(-29.2643673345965,17.4305615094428,16.4559962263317));
#844=CARTESIAN_POINT('',(-29.196119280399,17.5193353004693,16.2650726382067));
#845=B_SPLINE_CURVE_WITH_KNOTS('',3,(#735,#736,#737,#738,#739,#740,#741,#742,#743,#744,#745,
#746,#747,#748,#749,#750,#751,#752,#753,#754,#755,#756,#757,#758,#759,#760,#761,#762,#763,#764,
#765,#766,#767,#768,#769,#770,#771,#772,#773,#774,#775,#776,#777,#778,#779,#780,#781,#782,#783,
#784,#785,#786,#787,#788,#789,#790,#791,#792,#793,#794,#795,#796,#797,#798,#799,#800,#801,#802,
#803,#804,#805,#806,#807,#808,#809,#810,#811,#812,#813,#814,#815,#816,#817,#818,#819,#820,#821,
#822,#823,#824,#825,#826,#827,#828,#829,#830,#831,#832,#833,#834,#835,#836,#837,#838,#839,#840,
#841,#842,#843,#844),.UNSPECIFIED.,.F.,.F.,(4,2,2,2,2,2,2,2,2,2,2,2,2,2,2,2,2,2,2,2,2,2,2,2,2,2,
2,2,2,2,2,2,2,2,2,2,2,2,2,2,2,2,2,2,2,2,2,2,2,2,2,2,2,2,4),(0.,0.959614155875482,
1.9193241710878,2.87907098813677,3.84340641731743,4.80771099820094,5.77198397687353,
6.73647240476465,7.70099594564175,8.6656688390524,9.62789810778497,10.5900129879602,
11.5518878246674,12.1024685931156,12.6530683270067,13.2053826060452,13.7576507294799,
14.3157839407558,14.874209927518,15.4303567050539,15.9857060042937,16.2488048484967,
16.5118870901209,16.7745880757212,17.0372210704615,17.3028080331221,17.5683782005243,
17.8340330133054,18.0997162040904,18.3903212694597,18.6809725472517,18.9721194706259,
19.2632831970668,19.7863019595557,20.3098066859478,20.8351352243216,21.3602150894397,
21.8825481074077,22.4049541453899,22.9280486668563,23.4511755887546,24.499158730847,
25.5474673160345,26.6004879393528,27.652074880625,28.7029910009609,29.7538480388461,
30.4247728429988,31.0958536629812,31.7670446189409,32.4382938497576,33.1026715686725,
33.7669917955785,34.4311911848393,35.0952038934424),.UNSPECIFIED.);
#846=CARTESIAN_POINT('',(-29.196119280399,17.5193353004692,16.2650726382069));
#847=VERTEX_POINT('',#846);
#848=EDGE_CURVE('E125',#66,#847,#845,.T.);
#849=ORIENTED_EDGE('',*,*,#848,.F.);
#850=ORIENTED_EDGE('',*,*,#128,.T.);
#851=CARTESIAN_POINT('',(-18.7034398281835,-28.4520970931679,16.2650726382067));
#852=CARTESIAN_POINT('',(-18.8479692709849,-28.3792998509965,16.5409887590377));
#853=CARTESIAN_POINT('',(-18.9923586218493,-28.3052145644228,16.8166398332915));
#854=CARTESIAN_POINT('',(-19.2809456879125,-28.1543434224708,17.3673394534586));
#855=CARTESIAN_POINT('',(-19.4251433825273,-28.0775572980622,17.6423879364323));
#856=CARTESIAN_POINT('',(-19.7134123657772,-27.9211714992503,18.1917653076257));
#857=CARTESIAN_POINT('',(-19.857483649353,-27.8415717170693,18.4660941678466));
#858=CARTESIAN_POINT('',(-20.1462800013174,-27.6790234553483,19.0152039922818));
#859=CARTESIAN_POINT('',(-20.2910049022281,-27.5960607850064,19.2899808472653));
#860=CARTESIAN_POINT('',(-20.5805363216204,-27.4269622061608,19.8385022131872));
#861=CARTESIAN_POINT('',(-20.7253428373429,-27.3408263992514,20.1122467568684));
#862=CARTESIAN_POINT('',(-21.0151904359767,-27.1651486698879,20.6585050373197));
#863=CARTESIAN_POINT('',(-21.1602315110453,-27.0756068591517,20.931018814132));
#864=CARTESIAN_POINT('',(-21.4507791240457,-26.8927999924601,21.4746325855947));
#865=CARTESIAN_POINT('',(-21.5962857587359,-26.7995341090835,21.745732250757));
#866=CARTESIAN_POINT('',(-21.887985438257,-26.6089184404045,22.2861377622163));
#867=CARTESIAN_POINT('',(-22.0341785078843,-26.5115685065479,22.5554435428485));
#868=CARTESIAN_POINT('',(-22.3275893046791,-26.3122848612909,23.0918561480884));
#869=CARTESIAN_POINT('',(-22.4748071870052,-26.2103504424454,23.3589626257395));
#870=CARTESIAN_POINT('',(-22.7702918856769,-26.0015330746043,23.8896676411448));
#871=CARTESIAN_POINT('',(-22.9185551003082,-25.894663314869,24.1532733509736));
#872=CARTESIAN_POINT('',(-23.2170377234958,-25.6748891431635,24.6767996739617));
#873=CARTESIAN_POINT('',(-23.367256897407,-25.5619854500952,24.9367207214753));
#874=CARTESIAN_POINT('',(-23.6703895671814,-25.3289791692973,25.4516580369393));
#875=CARTESIAN_POINT('',(-23.8233023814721,-25.2088783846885,25.7066755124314));
#876=CARTESIAN_POINT('',(-24.0667110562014,-25.0130281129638,26.1023739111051));
#877=CARTESIAN_POINT('',(-24.1559378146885,-24.9402732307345,26.2453176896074));
#878=CARTESIAN_POINT('',(-24.3358993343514,-24.7914069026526,26.5285004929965));
#879=CARTESIAN_POINT('',(-24.4266341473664,-24.7152953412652,26.6687394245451));
#880=CARTESIAN_POINT('',(-24.6102066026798,-24.5589502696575,26.9462743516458));
#881=CARTESIAN_POINT('',(-24.7030499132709,-24.4787046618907,27.0835598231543));
#882=CARTESIAN_POINT('',(-24.8909468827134,-24.3136437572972,27.3538044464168));
#883=CARTESIAN_POINT('',(-24.9860003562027,-24.228828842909,27.4867639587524));
#884=CARTESIAN_POINT('',(-25.1798175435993,-24.0528445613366,27.7484650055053));
#885=CARTESIAN_POINT('',(-25.2786099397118,-23.9616172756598,27.8771467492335));
#886=CARTESIAN_POINT('',(-25.479565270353,-23.772462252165,28.1269528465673));
#887=CARTESIAN_POINT('',(-25.5817299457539,-23.6745310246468,28.2480732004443));
#888=CARTESIAN_POINT('',(-25.789556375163,-23.4710890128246,28.4793900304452));
#889=CARTESIAN_POINT('',(-25.8952021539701,-23.3656107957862,28.589629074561));
#890=CARTESIAN_POINT('',(-26.1108102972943,-23.1453058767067,28.795534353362));
#891=CARTESIAN_POINT('',(-26.2207662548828,-23.0304927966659,28.8912212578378));
#892=CARTESIAN_POINT('',(-26.385956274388,-22.8535328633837,29.0171569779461));
#893=CARTESIAN_POINT('',(-26.4395368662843,-22.7954663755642,29.0553432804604));
#894=CARTESIAN_POINT('',(-26.5475816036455,-22.6769014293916,29.1263522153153));
#895=CARTESIAN_POINT('',(-26.6020456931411,-22.6164031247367,29.1591751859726));
#896=CARTESIAN_POINT('',(-26.7115977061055,-22.4931139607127,29.2185867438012));
#897=CARTESIAN_POINT('',(-26.7666846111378,-22.4303265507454,29.2451842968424));
#898=CARTESIAN_POINT('',(-26.877260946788,-22.3025751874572,29.2913802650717));
#899=CARTESIAN_POINT('',(-26.9327502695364,-22.2376118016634,29.3109804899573));
#900=CARTESIAN_POINT('',(-27.0443727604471,-22.1050973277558,29.3426542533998));
#901=CARTESIAN_POINT('',(-27.1005061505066,-22.0375253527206,29.3546406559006));
#902=CARTESIAN_POINT('',(-27.2122856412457,-21.901021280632,29.3702307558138));
#903=CARTESIAN_POINT('',(-27.2679317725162,-21.8320892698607,29.3738349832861));
#904=CARTESIAN_POINT('',(-27.3782230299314,-21.693475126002,29.3725008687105));
#905=CARTESIAN_POINT('',(-27.4328678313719,-21.6237927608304,29.3675598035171));
#906=CARTESIAN_POINT('',(-27.5406523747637,-21.4843557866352,29.3493497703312));
#907=CARTESIAN_POINT('',(-27.5937919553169,-21.4146011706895,29.336079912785));
#908=CARTESIAN_POINT('',(-27.7030839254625,-21.2690916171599,29.3001466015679));
#909=CARTESIAN_POINT('',(-27.7590513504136,-21.1933876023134,29.2767187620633));
#910=CARTESIAN_POINT('',(-27.8684328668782,-21.0431910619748,29.2215580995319));
#911=CARTESIAN_POINT('',(-27.9218465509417,-20.9686987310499,29.1898239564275));
#912=CARTESIAN_POINT('',(-28.0261002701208,-20.8211771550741,29.1191196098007));
#913=CARTESIAN_POINT('',(-28.0769357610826,-20.7481506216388,29.0801371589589));
#914=CARTESIAN_POINT('',(-28.1759737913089,-20.6038764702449,28.9960693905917));
#915=CARTESIAN_POINT('',(-28.2241761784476,-20.5326289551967,28.9509837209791));
#916=CARTESIAN_POINT('',(-28.3554874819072,-20.3359205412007,28.8177525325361));
#917=CARTESIAN_POINT('',(-28.4358274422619,-20.2124674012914,28.7239071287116));
#918=CARTESIAN_POINT('',(-28.5895443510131,-19.9710084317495,28.5242616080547));
#919=CARTESIAN_POINT('',(-28.6629147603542,-19.8530077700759,28.4184504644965));
#920=CARTESIAN_POINT('',(-28.8039921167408,-19.6214020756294,28.1977099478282));
#921=CARTESIAN_POINT('',(-28.8716784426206,-19.5078137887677,28.0827500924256));
#922=CARTESIAN_POINT('',(-29.0020226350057,-19.2847897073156,27.8463236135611));
#923=CARTESIAN_POINT('',(-29.0646828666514,-19.1753519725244,27.7248600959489));
#924=CARTESIAN_POINT('',(-29.1854746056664,-18.9604733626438,27.4775702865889));
#925=CARTESIAN_POINT('',(-29.2436280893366,-18.8550145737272,27.3517701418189));
#926=CARTESIAN_POINT('',(-29.3563851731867,-18.6469350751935,27.0962769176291));
#927=CARTESIAN_POINT('',(-29.4109882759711,-18.5443147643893,26.9665832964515));
#928=CARTESIAN_POINT('',(-29.5171930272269,-18.3413417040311,26.7039359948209));
#929=CARTESIAN_POINT('',(-29.5687906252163,-18.2409921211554,26.5709782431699));
#930=CARTESIAN_POINT('',(-29.6692956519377,-18.0423273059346,26.302544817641));
#931=CARTESIAN_POINT('',(-29.7182029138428,-17.944012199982,26.1670689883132));
#932=CARTESIAN_POINT('',(-29.8615329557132,-17.6513242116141,25.7571058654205));
#933=CARTESIAN_POINT('',(-29.9523905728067,-17.4595421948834,25.4795205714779));
#934=CARTESIAN_POINT('',(-30.1264926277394,-17.0809906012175,24.9185263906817));
#935=CARTESIAN_POINT('',(-30.2097346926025,-16.8942225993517,24.6351157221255));
#936=CARTESIAN_POINT('',(-30.3701875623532,-16.5236492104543,24.0627757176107));
#937=CARTESIAN_POINT('',(-30.447369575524,-16.3398609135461,23.7738273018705));
#938=CARTESIAN_POINT('',(-30.596083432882,-15.9754345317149,23.1930961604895));
#939=CARTESIAN_POINT('',(-30.6676228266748,-15.7947924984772,22.9013178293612));
#940=CARTESIAN_POINT('',(-30.8057716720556,-15.4358433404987,22.3154416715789));
#941=CARTESIAN_POINT('',(-30.872384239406,-15.2575347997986,22.0213454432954));
#942=CARTESIAN_POINT('',(-31.0012074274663,-14.902642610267,21.4311813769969));
#943=CARTESIAN_POINT('',(-31.0634182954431,-14.7260588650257,21.1351136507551));
#944=CARTESIAN_POINT('',(-31.1620415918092,-14.4378303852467,20.6487047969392));
#945=CARTESIAN_POINT('',(-31.1996494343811,-14.3257893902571,20.4588391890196));
#946=CARTESIAN_POINT('',(-31.2733040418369,-14.1021474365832,20.0784855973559));
#947=CARTESIAN_POINT('',(-31.3093504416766,-13.9905465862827,19.8879974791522));
#948=CARTESIAN_POINT('',(-31.3799443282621,-13.7677246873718,19.5064794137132));
#949=CARTESIAN_POINT('',(-31.4144915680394,-13.6565037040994,19.3154493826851));
#950=CARTESIAN_POINT('',(-31.4821397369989,-13.4343923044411,18.9329190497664));
#951=CARTESIAN_POINT('',(-31.5152405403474,-13.3235019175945,18.7414187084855));
#952=CARTESIAN_POINT('',(-31.5797092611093,-13.1031453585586,18.359976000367));
#953=CARTESIAN_POINT('',(-31.611091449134,-12.9936762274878,18.170037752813));
#954=CARTESIAN_POINT('',(-31.6725209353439,-12.7749906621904,17.7898226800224));
#955=CARTESIAN_POINT('',(-31.7025683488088,-12.6657742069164,17.5995458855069));
#956=CARTESIAN_POINT('',(-31.761361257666,-12.447568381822,17.2187081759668));
#957=CARTESIAN_POINT('',(-31.7901069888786,-12.3385789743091,17.0281473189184));
#958=CARTESIAN_POINT('',(-31.8463243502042,-12.120807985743,16.6467913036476));
#959=CARTESIAN_POINT('',(-31.8737963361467,-12.0120263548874,16.4559962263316));
#960=CARTESIAN_POINT('',(-31.9006505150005,-11.9033183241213,16.2650726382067));
#961=B_SPLINE_CURVE_WITH_KNOTS('',3,(#851,#852,#853,#854,#855,#856,#857,#858,#859,#860,#861,
#862,#863,#864,#865,#866,#867,#868,#869,#870,#871,#872,#873,#874,#875,#876,#877,#878,#879,#880,
#881,#882,#883,#884,#885,#886,#887,#888,#889,#890,#891,#892,#893,#894,#895,#896,#897,#898,#899,
#900,#901,#902,#903,#904,#905,#906,#907,#908,#909,#910,#911,#912,#913,#914,#915,#916,#917,#918,
#919,#920,#921,#922,#923,#924,#925,#926,#927,#928,#929,#930,#931,#932,#933,#934,#935,#936,#937,
#938,#939,#940,#941,#942,#943,#944,#945,#946,#947,#948,#949,#950,#951,#952,#953,#954,#955,#956,
#957,#958,#959,#960),.UNSPECIFIED.,.F.,.F.,(4,2,2,2,2,2,2,2,2,2,2,2,2,2,2,2,2,2,2,2,2,2,2,2,2,2,
2,2,2,2,2,2,2,2,2,2,2,2,2,2,2,2,2,2,2,2,2,2,2,2,2,2,2,2,4),(0.,0.959614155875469,
1.91932417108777,2.87907098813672,3.84340641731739,4.8077109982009,5.77198397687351,
6.73647240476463,7.70099594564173,8.66566883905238,9.62789810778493,10.5900129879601,
11.5518878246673,12.1024685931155,12.6530683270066,13.2053826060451,13.7576507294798,
14.3157839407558,14.8742099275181,15.430356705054,15.9857060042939,16.2488048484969,
16.5118870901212,16.7745880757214,17.0372210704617,17.3028080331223,17.5683782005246,
17.8340330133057,18.0997162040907,18.3903212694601,18.6809725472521,18.9721194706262,
19.2632831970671,19.786301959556,20.3098066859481,20.835135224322,21.3602150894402,
21.8825481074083,22.4049541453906,22.9280486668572,23.4511755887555,24.4991587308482,
25.5474673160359,26.6004879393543,27.6520748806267,28.7029910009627,29.753848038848,
30.4247728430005,31.0958536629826,31.7670446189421,32.4382938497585,33.1026715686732,
33.7669917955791,34.4311911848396,35.0952038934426),.UNSPECIFIED.);
#962=EDGE_CURVE('E330',#175,#120,#961,.T.);
#963=ORIENTED_EDGE('',*,*,#962,.F.);
#964=ORIENTED_EDGE('',*,*,#227,.T.);
#965=CARTESIAN_POINT('',(10.583341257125,-32.3625304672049,16.2650726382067));
#966=CARTESIAN_POINT('',(10.4363134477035,-32.4301397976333,16.5409887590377));
#967=CARTESIAN_POINT('',(10.2883659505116,-32.4968365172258,16.8166398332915));
#968=CARTESIAN_POINT('',(9.99047904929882,-32.6283963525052,17.3673394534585));
#969=CARTESIAN_POINT('',(9.84053944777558,-32.6932592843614,17.6423879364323));
#970=CARTESIAN_POINT('',(9.53853933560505,-32.8211321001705,18.1917653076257));
#971=CARTESIAN_POINT('',(9.3864787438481,-32.8841419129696,18.4660941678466));
#972=CARTESIAN_POINT('',(9.07933181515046,-33.0085848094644,19.0152039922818));
#973=CARTESIAN_POINT('',(8.92423448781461,-33.0700089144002,19.2899808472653));
#974=CARTESIAN_POINT('',(8.61150800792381,-33.1909424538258,19.8385022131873));
#975=CARTESIAN_POINT('',(8.45387893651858,-33.2504519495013,20.1122467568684));
#976=CARTESIAN_POINT('',(8.13581153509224,-33.367530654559,20.6585050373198));
#977=CARTESIAN_POINT('',(7.97537329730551,-33.4250999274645,20.931018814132));
#978=CARTESIAN_POINT('',(7.65129566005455,-33.5382809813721,21.4746325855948));
#979=CARTESIAN_POINT('',(7.48765555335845,-33.5938923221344,21.7457322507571));
#980=CARTESIAN_POINT('',(7.15675444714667,-33.7031053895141,22.2861377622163));
#981=CARTESIAN_POINT('',(6.98949331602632,-33.7567070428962,22.5554435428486));
#982=CARTESIAN_POINT('',(6.65074844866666,-33.8618535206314,23.0918561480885));
#983=CARTESIAN_POINT('',(6.47926406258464,-33.9133980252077,23.3589626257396));
#984=CARTESIAN_POINT('',(6.13177237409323,-34.0142217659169,23.8896676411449));
#985=CARTESIAN_POINT('',(5.95577762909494,-34.0635064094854,24.1532733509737));
#986=CARTESIAN_POINT('',(5.59785039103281,-34.1598425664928,24.6767996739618));
#987=CARTESIAN_POINT('',(5.41591860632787,-34.2068943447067,24.9367207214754));
#988=CARTESIAN_POINT('',(5.0447468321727,-34.2986159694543,25.4516580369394));
#989=CARTESIAN_POINT('',(4.8555086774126,-34.3432864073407,25.7066755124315));
#990=CARTESIAN_POINT('',(4.55062394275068,-34.4114803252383,26.1023739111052));
#991=CARTESIAN_POINT('',(4.43810991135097,-34.4358786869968,26.2453176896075));
#992=CARTESIAN_POINT('',(4.20951735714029,-34.4837616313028,26.5285004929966));
#993=CARTESIAN_POINT('',(4.09343871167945,-34.5072461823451,26.6687394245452));
#994=CARTESIAN_POINT('',(3.85674765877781,-34.5532893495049,26.9462743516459));
#995=CARTESIAN_POINT('',(3.73612225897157,-34.575844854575,27.0835598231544));
#996=CARTESIAN_POINT('',(3.48992060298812,-34.6198348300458,27.3538044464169));
#997=CARTESIAN_POINT('',(3.36434476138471,-34.6412693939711,27.4867639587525));
#998=CARTESIAN_POINT('',(3.10591166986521,-34.6830773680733,27.7484650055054));
#999=CARTESIAN_POINT('',(2.97299125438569,-34.7034370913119,27.8771467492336));
#1000=CARTESIAN_POINT('',(2.69981030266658,-34.7426140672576,28.1269528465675));
#1001=CARTESIAN_POINT('',(2.55954595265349,-34.761430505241,28.2480732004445));
#1002=CARTESIAN_POINT('',(2.270910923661,-34.7970717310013,28.4793900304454));
#1003=CARTESIAN_POINT('',(2.12257566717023,-34.8139043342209,28.5896290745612));
#1004=CARTESIAN_POINT('',(1.81590486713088,-34.8451156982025,28.7955343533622));
#1005=CARTESIAN_POINT('',(1.65758396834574,-34.8594979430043,28.8912212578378));
#1006=CARTESIAN_POINT('',(1.41623682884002,-34.8783159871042,29.0171569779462));
#1007=CARTESIAN_POINT('',(1.33743166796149,-34.8840031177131,29.0553432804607));
#1008=CARTESIAN_POINT('',(1.17736906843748,-34.8945518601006,29.1263522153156));
#1009=CARTESIAN_POINT('',(1.09611178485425,-34.8994135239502,29.1591751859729));
#1010=CARTESIAN_POINT('',(0.931415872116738,-34.9081952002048,29.2185867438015));
#1011=CARTESIAN_POINT('',(0.847980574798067,-34.9121165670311,29.2451842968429));
#1012=CARTESIAN_POINT('',(0.679157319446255,-34.9189169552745,29.2913802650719));
#1013=CARTESIAN_POINT('',(0.5937698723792,-34.9217962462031,29.3109804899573));
#1014=CARTESIAN_POINT('',(0.420570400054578,-34.9264448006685,29.3426542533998));
#1015=CARTESIAN_POINT('',(0.332741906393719,-34.928201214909,29.3546406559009));
#1016=CARTESIAN_POINT('',(0.15632535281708,-34.9304850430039,29.3702307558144));
#1017=CARTESIAN_POINT('',(0.0677373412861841,-34.9310125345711,29.3738349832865));
#1018=CARTESIAN_POINT('',(-0.109401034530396,-34.93081720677,29.372500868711));
#1019=CARTESIAN_POINT('',(-0.197951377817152,-34.9300939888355,29.3675598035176));
#1020=CARTESIAN_POINT('',(-0.374170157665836,-34.9274258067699,29.3493497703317));
#1021=CARTESIAN_POINT('',(-0.461838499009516,-34.9254807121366,29.3360799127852));
#1022=CARTESIAN_POINT('',(-0.643744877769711,-34.9202048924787,29.3001466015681));
#1023=CARTESIAN_POINT('',(-0.737827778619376,-34.9167613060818,29.2767187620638));
#1024=CARTESIAN_POINT('',(-0.923454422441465,-34.9086332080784,29.2215580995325));
#1025=CARTESIAN_POINT('',(-1.01499775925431,-34.9039484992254,29.189823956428));
#1026=CARTESIAN_POINT('',(-1.19533590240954,-34.893479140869,29.1191196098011));
#1027=CARTESIAN_POINT('',(-1.28412575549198,-34.8876926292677,29.0801371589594));
#1028=CARTESIAN_POINT('',(-1.45867303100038,-34.8751702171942,28.996069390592));
#1029=CARTESIAN_POINT('',(-1.54443027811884,-34.8684342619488,28.9509837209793));
#1030=CARTESIAN_POINT('',(-1.78009436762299,-34.8484518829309,28.8177525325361));
#1031=CARTESIAN_POINT('',(-1.92670506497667,-34.8342924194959,28.7239071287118));
#1032=CARTESIAN_POINT('',(-2.21132621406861,-34.8039259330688,28.5242616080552));
#1033=CARTESIAN_POINT('',(-2.34932854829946,-34.7877170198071,28.4184504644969));
#1034=CARTESIAN_POINT('',(-2.61836546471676,-34.7536119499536,28.1977099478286));
#1035=CARTESIAN_POINT('',(-2.74937409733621,-34.7357101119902,28.082750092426));
#1036=CARTESIAN_POINT('',(-3.0050096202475,-34.6985640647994,27.8463236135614));
#1037=CARTESIAN_POINT('',(-3.12963950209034,-34.6793204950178,27.7248600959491));
#1038=CARTESIAN_POINT('',(-3.37295078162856,-34.6397846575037,27.4775702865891));
#1039=CARTESIAN_POINT('',(-3.49165988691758,-34.6194984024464,27.3517701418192));
#1040=CARTESIAN_POINT('',(-3.7246458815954,-34.5779199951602,27.0962769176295));
#1041=CARTESIAN_POINT('',(-3.83892214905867,-34.5566277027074,26.9665832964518));
#1042=CARTESIAN_POINT('',(-4.06383045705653,-34.5131102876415,26.7039359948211));
#1043=CARTESIAN_POINT('',(-4.17445749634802,-34.4908839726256,26.5709782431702));
#1044=CARTESIAN_POINT('',(-4.39244376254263,-34.4455964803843,26.3025448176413));
#1045=CARTESIAN_POINT('',(-4.49980278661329,-34.4225352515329,26.1670689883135));
#1046=CARTESIAN_POINT('',(-4.81800028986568,-34.3521072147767,25.7571058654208));
#1047=CARTESIAN_POINT('',(-5.0245903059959,-34.3035684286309,25.4795205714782));
#1048=CARTESIAN_POINT('',(-5.4291047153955,-34.2036638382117,24.9185263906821));
#1049=CARTESIAN_POINT('',(-5.6270263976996,-34.1522971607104,24.6351157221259));
#1050=CARTESIAN_POINT('',(-6.01679306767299,-34.0466955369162,24.0627757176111));
#1051=CARTESIAN_POINT('',(-6.2086067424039,-33.9924487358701,23.7738273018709));
#1052=CARTESIAN_POINT('',(-6.58624833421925,-33.8815017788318,23.1930961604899));
#1053=CARTESIAN_POINT('',(-6.77208404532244,-33.8248050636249,22.9013178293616));
#1054=CARTESIAN_POINT('',(-7.13885619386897,-33.7090130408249,22.3154416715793));
#1055=CARTESIAN_POINT('',(-7.31979568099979,-33.6499192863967,22.0213454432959));
#1056=CARTESIAN_POINT('',(-7.67758151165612,-33.5293656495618,21.4311813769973));
#1057=CARTESIAN_POINT('',(-7.85442808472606,-33.4679059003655,21.1351136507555));
#1058=CARTESIAN_POINT('',(-8.14126480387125,-33.3653051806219,20.6487047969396));
#1059=CARTESIAN_POINT('',(-8.25231008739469,-33.3248517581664,20.45883918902));
#1060=CARTESIAN_POINT('',(-8.4730833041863,-33.2429987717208,20.0784855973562));
#1061=CARTESIAN_POINT('',(-8.58281092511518,-33.2015989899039,19.8879974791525));
#1062=CARTESIAN_POINT('',(-8.80103466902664,-33.1178643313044,19.5064794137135));
#1063=CARTESIAN_POINT('',(-8.90953058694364,-33.0755293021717,19.3154493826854));
#1064=CARTESIAN_POINT('',(-9.12536221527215,-32.989934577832,18.9329190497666));
#1065=CARTESIAN_POINT('',(-9.23269782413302,-32.9466748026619,18.7414187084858));
#1066=CARTESIAN_POINT('',(-9.4451751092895,-32.8596884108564,18.3599760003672));
#1067=CARTESIAN_POINT('',(-9.55032799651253,-32.8159711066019,18.1700377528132));
#1068=CARTESIAN_POINT('',(-9.75960391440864,-32.7276503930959,17.7898226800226));
#1069=CARTESIAN_POINT('',(-9.86372703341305,-32.683047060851,17.599545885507));
#1070=CARTESIAN_POINT('',(-10.0709839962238,-32.5929641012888,17.218708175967));
#1071=CARTESIAN_POINT('',(-10.174118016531,-32.5474846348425,17.0281473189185));
#1072=CARTESIAN_POINT('',(-10.379429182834,-32.4556591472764,16.6467913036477));
#1073=CARTESIAN_POINT('',(-10.481606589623,-32.4093133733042,16.4559962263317));
#1074=CARTESIAN_POINT('',(-10.5833412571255,-32.3625304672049,16.2650726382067));
#1075=B_SPLINE_CURVE_WITH_KNOTS('',3,(#965,#966,#967,#968,#969,#970,#971,#972,#973,#974,#975,
#976,#977,#978,#979,#980,#981,#982,#983,#984,#985,#986,#987,#988,#989,#990,#991,#992,#993,#994,
#995,#996,#997,#998,#999,#1000,#1001,#1002,#1003,#1004,#1005,#1006,#1007,#1008,#1009,#1010,
#1011,#1012,#1013,#1014,#1015,#1016,#1017,#1018,#1019,#1020,#1021,#1022,#1023,#1024,#1025,#1026,
#1027,#1028,#1029,#1030,#1031,#1032,#1033,#1034,#1035,#1036,#1037,#1038,#1039,#1040,#1041,#1042,
#1043,#1044,#1045,#1046,#1047,#1048,#1049,#1050,#1051,#1052,#1053,#1054,#1055,#1056,#1057,#1058,
#1059,#1060,#1061,#1062,#1063,#1064,#1065,#1066,#1067,#1068,#1069,#1070,#1071,#1072,#1073,
#1074),.UNSPECIFIED.,.F.,.F.,(4,2,2,2,2,2,2,2,2,2,2,2,2,2,2,2,2,2,2,2,2,2,2,2,2,2,2,2,2,2,2,2,2,
2,2,2,2,2,2,2,2,2,2,2,2,2,2,2,2,2,2,2,2,2,4),(0.,0.959614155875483,1.91932417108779,
2.87907098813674,3.84340641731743,4.80771099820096,5.77198397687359,6.73647240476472,
7.70099594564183,8.66566883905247,9.62789810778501,10.5900129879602,11.5518878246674,
12.1024685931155,12.6530683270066,13.2053826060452,13.7576507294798,14.3157839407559,
14.8742099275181,15.4303567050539,15.9857060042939,16.2488048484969,16.5118870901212,
16.7745880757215,17.0372210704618,17.3028080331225,17.5683782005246,17.8340330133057,
18.0997162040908,18.3903212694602,18.6809725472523,18.9721194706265,19.2632831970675,
19.7863019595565,20.3098066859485,20.8351352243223,21.3602150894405,21.8825481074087,
22.404954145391,22.9280486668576,23.4511755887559,24.4991587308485,25.5474673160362,
26.6004879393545,27.6520748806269,28.7029910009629,29.7538480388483,30.4247728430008,
31.095853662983,31.7670446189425,32.438293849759,33.1026715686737,33.7669917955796,
34.4311911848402,35.0952038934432),.UNSPECIFIED.);
#1076=EDGE_CURVE('E321',#274,#224,#1075,.T.);
#1077=ORIENTED_EDGE('',*,*,#1076,.F.);
#1078=ORIENTED_EDGE('',*,*,#326,.T.);
#1079=CARTESIAN_POINT('',(31.9006505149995,-11.9033183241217,16.2650726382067));
#1080=CARTESIAN_POINT('',(31.8618392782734,-12.0604230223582,16.5409887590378));
#1081=CARTESIAN_POINT('',(31.8217411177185,-12.2176777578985,16.8166398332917));
#1082=CARTESIAN_POINT('',(31.7388692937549,-12.5326013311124,17.3673394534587));
#1083=CARTESIAN_POINT('',(31.6960953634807,-12.6902702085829,17.6423879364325));
#1084=CARTESIAN_POINT('',(31.6077763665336,-13.0061108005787,18.1917653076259));
#1085=CARTESIAN_POINT('',(31.5622311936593,-13.1642825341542,18.4660941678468));
#1086=CARTESIAN_POINT('',(31.4680215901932,-13.4820085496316,19.015203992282));
#1087=CARTESIAN_POINT('',(31.419343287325,-13.6415658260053,19.2899808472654));
#1088=CARTESIAN_POINT('',(31.3189111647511,-13.9614660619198,19.8385022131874));
#1089=CARTESIAN_POINT('',(31.2671574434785,-14.1218089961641,20.1122467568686));
#1090=CARTESIAN_POINT('',(31.160381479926,-14.4434814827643,20.6585050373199));
#1091=CARTESIAN_POINT('',(31.1053593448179,-14.6048110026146,20.9310188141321));
#1092=CARTESIAN_POINT('',(30.9917887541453,-14.9287523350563,21.4746325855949));
#1093=CARTESIAN_POINT('',(30.9332395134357,-15.0913644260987,21.7457322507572));
#1094=CARTESIAN_POINT('',(30.8123122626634,-15.4181665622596,22.2861377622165));
#1095=CARTESIAN_POINT('',(30.7499341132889,-15.5823566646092,22.5554435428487));
#1096=CARTESIAN_POINT('',(30.6209369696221,-15.9127558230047,23.0918561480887));
#1097=CARTESIAN_POINT('',(30.5543173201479,-16.0789651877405,23.3589626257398));
#1098=CARTESIAN_POINT('',(30.4164869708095,-16.4135077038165,23.8896676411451));
#1099=CARTESIAN_POINT('',(30.3452883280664,-16.5818344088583,24.1532733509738));
#1100=CARTESIAN_POINT('',(30.1974429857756,-16.9217378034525,24.676799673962));
#1101=CARTESIAN_POINT('',(30.120796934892,-17.093314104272,24.9367207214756));
#1102=CARTESIAN_POINT('',(29.961085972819,-17.4406953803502,25.4516580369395));
#1103=CARTESIAN_POINT('',(29.8780226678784,-17.6164992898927,25.7066755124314));
#1104=CARTESIAN_POINT('',(29.7412462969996,-17.8973859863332,26.1023739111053));
#1105=CARTESIAN_POINT('',(29.6901703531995,-18.0005651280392,26.2453176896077));
#1106=CARTESIAN_POINT('',(29.5850816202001,-18.2091405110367,26.5285004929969));
#1107=CARTESIAN_POINT('',(29.5310687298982,-18.3145368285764,26.6687394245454));
#1108=CARTESIAN_POINT('',(29.4194922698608,-18.5282967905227,26.9462743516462));
#1109=CARTESIAN_POINT('',(29.3619181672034,-18.6366686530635,27.0835598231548));
#1110=CARTESIAN_POINT('',(29.2428066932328,-18.8565841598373,27.3538044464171));
#1111=CARTESIAN_POINT('',(29.1812696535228,-18.9681275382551,27.4867639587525));
#1112=CARTESIAN_POINT('',(29.0528260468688,-19.1962455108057,27.7484650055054));
#1113=CARTESIAN_POINT('',(28.985869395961,-19.3128609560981,27.8771467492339));
#1114=CARTESIAN_POINT('',(28.8461736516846,-19.5508688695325,28.1269528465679));
#1115=CARTESIAN_POINT('',(28.7734315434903,-19.6722638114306,28.2480732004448));
#1116=CARTESIAN_POINT('',(28.6213359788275,-19.9201497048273,28.4793900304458));
#1117=CARTESIAN_POINT('',(28.5420107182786,-20.0466178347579,28.5896290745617));
#1118=CARTESIAN_POINT('',(28.3752066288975,-20.3058426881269,28.7955343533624));
#1119=CARTESIAN_POINT('',(28.2877396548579,-20.4385901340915,28.8912212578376));
#1120=CARTESIAN_POINT('',(28.1519747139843,-20.639015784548,29.0171569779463));
#1121=CARTESIAN_POINT('',(28.1072868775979,-20.7041740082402,29.055343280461));
#1122=CARTESIAN_POINT('',(28.0157368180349,-20.8358930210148,29.1263522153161));
#1123=CARTESIAN_POINT('',(27.9688747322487,-20.9024537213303,29.1591751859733));
#1124=CARTESIAN_POINT('',(27.8730543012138,-21.0366934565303,29.218586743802));
#1125=CARTESIAN_POINT('',(27.8240990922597,-21.1043707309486,29.2451842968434));
#1126=CARTESIAN_POINT('',(27.7241562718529,-21.2406020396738,29.2913802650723));
#1127=CARTESIAN_POINT('',(27.6731691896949,-21.309155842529,29.3109804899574));
#1128=CARTESIAN_POINT('',(27.5688154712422,-21.4474669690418,29.3426542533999));
#1129=CARTESIAN_POINT('',(27.5154285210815,-21.5172291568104,29.3546406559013));
#1130=CARTESIAN_POINT('',(27.4072201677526,-21.6565811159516,29.3702307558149));
#1131=CARTESIAN_POINT('',(27.3523988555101,-21.7261708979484,29.373834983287));
#1132=CARTESIAN_POINT('',(27.2418021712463,-21.8645414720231,29.3725008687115));
#1133=CARTESIAN_POINT('',(27.1860265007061,-21.9333219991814,29.3675598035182));
#1134=CARTESIAN_POINT('',(27.0740698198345,-22.0694318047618,29.349349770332));
#1135=CARTESIAN_POINT('',(27.0178887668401,-22.1367609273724,29.3360799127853));
#1136=CARTESIAN_POINT('',(26.9003471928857,-22.2756916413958,29.3001466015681));
#1137=CARTESIAN_POINT('',(26.8389951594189,-22.3471015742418,29.2767187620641));
#1138=CARTESIAN_POINT('',(26.716904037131,-22.4871625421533,29.2215580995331));
#1139=CARTESIAN_POINT('',(26.6561650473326,-22.5558131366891,29.1898239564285));
#1140=CARTESIAN_POINT('',(26.5355407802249,-22.6902796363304,29.1191196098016));
#1141=CARTESIAN_POINT('',(26.4756571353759,-22.7560905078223,29.08013715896));
#1142=CARTESIAN_POINT('',(26.3570382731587,-22.8847494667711,28.9960693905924));
#1143=CARTESIAN_POINT('',(26.2983031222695,-22.9475973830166,28.9509837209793));
#1144=CARTESIAN_POINT('',(26.1357461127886,-23.1193881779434,28.8177525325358));
#1145=CARTESIAN_POINT('',(26.0332655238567,-23.22518475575,28.723907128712));
#1146=CARTESIAN_POINT('',(25.8320656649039,-23.4287773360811,28.5242616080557));
#1147=CARTESIAN_POINT('',(25.7333499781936,-23.5265658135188,28.4184504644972));
#1148=CARTESIAN_POINT('',(25.5389437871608,-23.7156431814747,28.1977099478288));
#1149=CARTESIAN_POINT('',(25.4432650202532,-23.806908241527,28.0827500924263));
#1150=CARTESIAN_POINT('',(25.2548369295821,-23.9836119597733,27.8463236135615));
#1151=CARTESIAN_POINT('',(25.162086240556,-24.0690533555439,27.7248600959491));
#1152=CARTESIAN_POINT('',(24.9794737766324,-24.2346315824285,27.477570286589));
#1153=CARTESIAN_POINT('',(24.8895994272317,-24.3147938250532,27.3517701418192));
#1154=CARTESIAN_POINT('',(24.7118277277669,-24.4710258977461,27.0962769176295));
#1155=CARTESIAN_POINT('',(24.6239306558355,-24.5470951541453,26.9665832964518));
#1156=CARTESIAN_POINT('',(24.4496793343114,-24.6958028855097,26.703935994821));
#1157=CARTESIAN_POINT('',(24.3633272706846,-24.7684367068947,26.5709782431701));
#1158=CARTESIAN_POINT('',(24.1920078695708,-24.9106289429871,26.3025448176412));
#1159=CARTESIAN_POINT('',(24.1070406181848,-24.9801871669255,26.1670689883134));
#1160=CARTESIAN_POINT('',(23.8535848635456,-25.1850528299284,25.7571058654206));
#1161=CARTESIAN_POINT('',(23.686828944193,-25.3163079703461,25.4795205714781));
#1162=CARTESIAN_POINT('',(23.3565097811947,-25.5702805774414,24.9185263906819));
#1163=CARTESIAN_POINT('',(23.192947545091,-25.6929953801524,24.6351157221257));
#1164=CARTESIAN_POINT('',(22.8673693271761,-25.9318856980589,24.0627757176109));
#1165=CARTESIAN_POINT('',(22.7053636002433,-26.0480293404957,23.7738273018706));
#1166=CARTESIAN_POINT('',(22.3831660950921,-26.2741071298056,23.1930961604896));
#1167=CARTESIAN_POINT('',(22.2229721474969,-26.3840495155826,22.9013178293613));
#1168=CARTESIAN_POINT('',(21.9037636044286,-26.5986083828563,22.3154416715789));
#1169=CARTESIAN_POINT('',(21.7447483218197,-26.7032282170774,22.0213454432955));
#1170=CARTESIAN_POINT('',(21.4274198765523,-26.9077924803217,21.4311813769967));
#1171=CARTESIAN_POINT('',(21.2691066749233,-27.0077371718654,21.1351136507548));
#1172=CARTESIAN_POINT('',(21.0100504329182,-27.1680246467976,20.6487047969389));
#1173=CARTESIAN_POINT('',(20.9091870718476,-27.2296210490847,20.4588391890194));
#1174=CARTESIAN_POINT('',(20.7075419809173,-27.3511939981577,20.0784855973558));
#1175=CARTESIAN_POINT('',(20.6067602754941,-27.4111701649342,19.8879974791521));
#1176=CARTESIAN_POINT('',(20.4052336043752,-27.5295766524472,19.5064794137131));
#1177=CARTESIAN_POINT('',(20.3044886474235,-27.5880067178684,19.315449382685));
#1178=CARTESIAN_POINT('',(20.1029991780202,-27.7033832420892,18.9329190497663));
#1179=CARTESIAN_POINT('',(20.0022546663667,-27.7603295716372,18.7414187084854));
#1180=CARTESIAN_POINT('',(19.8017685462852,-27.8722158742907,18.3599760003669));
#1181=CARTESIAN_POINT('',(19.7020272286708,-27.9271704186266,18.170037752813));
#1182=CARTESIAN_POINT('',(19.502493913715,-28.0357218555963,17.7898226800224));
#1183=CARTESIAN_POINT('',(19.402701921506,-28.089318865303,17.599545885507));
#1184=CARTESIAN_POINT('',(19.2030496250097,-28.195193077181,17.2187081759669));
#1185=CARTESIAN_POINT('',(19.10318933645,-28.2474705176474,17.0281473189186));
#1186=CARTESIAN_POINT('',(18.9033878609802,-28.3507369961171,16.6467913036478));
#1187=CARTESIAN_POINT('',(18.803446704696,-28.4017263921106,16.4559962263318));
#1188=CARTESIAN_POINT('',(18.703439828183,-28.4520970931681,16.2650726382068));
#1189=B_SPLINE_CURVE_WITH_KNOTS('',3,(#1079,#1080,#1081,#1082,#1083,#1084,#1085,#1086,#1087,
#1088,#1089,#1090,#1091,#1092,#1093,#1094,#1095,#1096,#1097,#1098,#1099,#1100,#1101,#1102,#1103,
#1104,#1105,#1106,#1107,#1108,#1109,#1110,#1111,#1112,#1113,#1114,#1115,#1116,#1117,#1118,#1119,
#1120,#1121,#1122,#1123,#1124,#1125,#1126,#1127,#1128,#1129,#1130,#1131,#1132,#1133,#1134,#1135,
#1136,#1137,#1138,#1139,#1140,#1141,#1142,#1143,#1144,#1145,#1146,#1147,#1148,#1149,#1150,#1151,
#1152,#1153,#1154,#1155,#1156,#1157,#1158,#1159,#1160,#1161,#1162,#1163,#1164,#1165,#1166,#1167,
#1168,#1169,#1170,#1171,#1172,#1173,#1174,#1175,#1176,#1177,#1178,#1179,#1180,#1181,#1182,#1183,
#1184,#1185,#1186,#1187,#1188),.UNSPECIFIED.,.F.,.F.,(4,2,2,2,2,2,2,2,2,2,2,2,2,2,2,2,2,2,2,2,2,
2,2,2,2,2,2,2,2,2,2,2,2,2,2,2,2,2,2,2,2,2,2,2,2,2,2,2,2,2,2,2,2,2,4),(0.,0.959614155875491,
1.91932417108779,2.87907098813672,3.84340641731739,4.80771099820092,5.77198397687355,
6.7364724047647,7.70099594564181,8.66566883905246,9.62789810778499,10.5900129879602,
11.5518878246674,12.1024685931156,12.6530683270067,13.2053826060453,13.75765072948,
14.3157839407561,14.8742099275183,15.430356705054,15.9857060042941,16.2488048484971,
16.5118870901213,16.7745880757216,17.0372210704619,17.3028080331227,17.5683782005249,
17.834033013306,18.0997162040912,18.3903212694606,18.6809725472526,18.9721194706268,
19.2632831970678,19.7863019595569,20.309806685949,20.8351352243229,21.3602150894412,
21.8825481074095,22.4049541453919,22.9280486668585,23.4511755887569,24.4991587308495,
25.5474673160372,26.6004879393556,27.6520748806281,28.7029910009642,29.7538480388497,
30.4247728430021,31.0958536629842,31.7670446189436,32.43829384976,33.1026715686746,
33.7669917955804,34.4311911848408,35.0952038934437),.UNSPECIFIED.);
#1190=EDGE_CURVE('E312',#373,#323,#1189,.T.);
#1191=ORIENTED_EDGE('',*,*,#1190,.F.);
#1192=ORIENTED_EDGE('',*,*,#425,.T.);
#1193=CARTESIAN_POINT('',(29.1961192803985,17.5193353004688,16.2650726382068));
#1194=CARTESIAN_POINT('',(29.2947502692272,17.3910382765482,16.5409887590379));
#1195=CARTESIAN_POINT('',(29.3926961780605,17.261641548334,16.8166398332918));
#1196=CARTESIAN_POINT('',(29.5872436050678,17.0004981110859,17.3673394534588));
#1197=CARTESIAN_POINT('',(29.6838449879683,16.8687511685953,17.6423879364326));
#1198=CARTESIAN_POINT('',(29.8757131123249,16.6027772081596,18.191765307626));
#1199=CARTESIAN_POINT('',(29.9709798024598,16.4685500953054,18.4660941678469));
#1200=CARTESIAN_POINT('',(30.1606492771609,16.1967951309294,19.0152039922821));
#1201=CARTESIAN_POINT('',(30.2550457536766,16.0592545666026,19.2899808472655));
#1202=CARTESIAN_POINT('',(30.4425354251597,15.7812790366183,19.8385022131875));
#1203=CARTESIAN_POINT('',(30.5356286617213,15.6408441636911,20.1122467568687));
#1204=CARTESIAN_POINT('',(30.7205486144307,15.3568038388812,20.65850503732));
#1205=CARTESIAN_POINT('',(30.812375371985,15.2131984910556,20.9310188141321));
#1206=CARTESIAN_POINT('',(30.9948327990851,14.9224313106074,21.4746325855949));
#1207=CARTESIAN_POINT('',(31.0854631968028,14.7752686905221,21.7457322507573));
#1208=CARTESIAN_POINT('',(31.2655704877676,14.476966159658,22.2861377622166));
#1209=CARTESIAN_POINT('',(31.3550473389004,14.3258261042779,22.5554435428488));
#1210=CARTESIAN_POINT('',(31.5329353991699,14.0189715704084,23.0918561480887));
#1211=CARTESIAN_POINT('',(31.6213464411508,13.8632563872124,23.3589626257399));
#1212=CARTESIAN_POINT('',(31.7969664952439,13.5469124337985,23.8896676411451));
#1213=CARTESIAN_POINT('',(31.8841779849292,13.3862971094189,24.1532733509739));
#1214=CARTESIAN_POINT('',(32.0577450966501,13.0587806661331,24.6767996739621));
#1215=CARTESIAN_POINT('',(32.1441008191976,12.8918802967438,24.9367207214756));
#1216=CARTESIAN_POINT('',(32.3161162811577,12.5504245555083,25.4516580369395));
#1217=CARTESIAN_POINT('',(32.4017761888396,12.3758711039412,25.7066755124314));
#1218=CARTESIAN_POINT('',(32.5361035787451,12.093805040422,26.1023739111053));
#1219=CARTESIAN_POINT('',(32.5849269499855,11.9895411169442,26.2453176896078));
#1220=CARTESIAN_POINT('',(32.6824759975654,11.777334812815,26.528500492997));
#1221=CARTESIAN_POINT('',(32.7312016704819,11.6693923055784,26.6687394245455));
#1222=CARTESIAN_POINT('',(32.828759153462,11.4488811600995,26.9462743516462));
#1223=CARTESIAN_POINT('',(32.877590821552,11.3362991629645,27.0835598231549));
#1224=CARTESIAN_POINT('',(32.9752628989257,11.1060589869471,27.3538044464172));
#1225=CARTESIAN_POINT('',(33.0241033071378,10.9884012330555,27.4867639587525));
#1226=CARTESIAN_POINT('',(33.122369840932,10.7457507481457,27.7484650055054));
#1227=CARTESIAN_POINT('',(33.1717966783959,10.6206933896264,27.877146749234));
#1228=CARTESIAN_POINT('',(33.2707798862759,10.3630793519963,28.126952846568));
#1229=CARTESIAN_POINT('',(33.3203363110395,10.2305187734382,28.2480732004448));
#1230=CARTESIAN_POINT('',(33.4193112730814,9.95705134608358,28.4793900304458));
#1231=CARTESIAN_POINT('',(33.4687295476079,9.8161807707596,28.5896290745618));
#1232=CARTESIAN_POINT('',(33.5673990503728,9.52414402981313,28.7955343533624));
#1233=CARTESIAN_POINT('',(33.6166504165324,9.37299291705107,28.8912212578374));
#1234=CARTESIAN_POINT('',(33.6887014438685,9.1418842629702,29.0171569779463));
#1235=CARTESIAN_POINT('',(33.7117817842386,9.06632041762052,29.0553432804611));
#1236=CARTESIAN_POINT('',(33.7576833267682,8.91261823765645,29.1263522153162));
#1237=CARTESIAN_POINT('',(33.7805045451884,8.83448006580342,29.1591751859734));
#1238=CARTESIAN_POINT('',(33.825714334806,8.67586753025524,29.2185867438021));
#1239=CARTESIAN_POINT('',(33.8481034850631,8.59539671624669,29.2451842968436));
#1240=CARTESIAN_POINT('',(33.8923000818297,8.43231944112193,29.2913802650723));
#1241=CARTESIAN_POINT('',(33.9141076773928,8.34971353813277,29.3109804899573));
#1242=CARTESIAN_POINT('',(33.9571801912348,8.18189093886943,29.3426542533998));
#1243=CARTESIAN_POINT('',(33.9784362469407,8.09665532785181,29.3546406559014));
#1244=CARTESIAN_POINT('',(34.0199191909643,7.92517010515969,29.3702307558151));
#1245=CARTESIAN_POINT('',(34.0401461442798,7.83892055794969,29.3738349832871));
#1246=CARTESIAN_POINT('',(34.0793727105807,7.66617994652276,29.3725008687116));
#1247=CARTESIAN_POINT('',(34.0983719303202,7.57968881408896,29.3675598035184));
#1248=CARTESIAN_POINT('',(34.134983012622,7.4072944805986,29.3493497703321));
#1249=CARTESIAN_POINT('',(34.1525947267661,7.32139134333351,29.3360799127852));
#1250=CARTESIAN_POINT('',(34.1879291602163,7.14287175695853,29.300146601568));
#1251=CARTESIAN_POINT('',(34.2055073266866,7.05038144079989,29.2767187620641));
#1252=CARTESIAN_POINT('',(34.2388888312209,6.86760017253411,29.2215580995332));
#1253=CARTESIAN_POINT('',(34.2546918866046,6.77730957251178,29.1898239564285));
#1254=CARTESIAN_POINT('',(34.2846140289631,6.59916323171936,29.1191196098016));
#1255=CARTESIAN_POINT('',(34.2987301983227,6.51131190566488,29.0801371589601));
#1256=CARTESIAN_POINT('',(34.3253621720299,6.33835439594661,28.9960693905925));
#1257=CARTESIAN_POINT('',(34.337877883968,6.25324837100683,28.9509837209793));
#1258=CARTESIAN_POINT('',(34.3708366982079,6.01904637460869,28.8177525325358));
#1259=CARTESIAN_POINT('',(34.3896561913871,5.87296073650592,28.723907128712));
#1260=CARTESIAN_POINT('',(34.4233852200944,5.58871845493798,28.5242616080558));
#1261=CARTESIAN_POINT('',(34.4382911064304,5.45056930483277,28.4184504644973));
#1262=CARTESIAN_POINT('',(34.4649074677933,5.18068861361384,28.1977099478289));
#1263=CARTESIAN_POINT('',(34.4766066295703,5.04898110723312,28.0827500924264));
#1264=CARTESIAN_POINT('',(34.4972761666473,4.79148912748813,27.8463236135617));
#1265=CARTESIAN_POINT('',(34.5062478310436,4.66570187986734,27.7248600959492));
#1266=CARTESIAN_POINT('',(34.5218450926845,4.41969337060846,27.4775702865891));
#1267=CARTESIAN_POINT('',(34.5284827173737,4.29944643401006,27.3517701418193));
#1268=CARTESIAN_POINT('',(34.5397910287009,4.06304981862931,27.0962769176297));
#1269=CARTESIAN_POINT('',(34.5444614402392,3.94690071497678,26.966583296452));
#1270=CARTESIAN_POINT('',(34.5520819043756,3.71794779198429,26.7039359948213));
#1271=CARTESIAN_POINT('',(34.5550296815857,3.60514858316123,26.5709782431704));
#1272=CARTESIAN_POINT('',(34.5593841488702,3.38255027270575,26.3025448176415));
#1273=CARTESIAN_POINT('',(34.5607907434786,3.2727513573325,26.1670689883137));
#1274=CARTESIAN_POINT('',(34.5629340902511,2.94686001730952,25.757105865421));
#1275=CARTESIAN_POINT('',(34.5615828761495,2.73464874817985,25.4795205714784));
#1276=CARTESIAN_POINT('',(34.5541960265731,2.31804549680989,24.9185263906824));
#1277=CARTESIAN_POINT('',(34.5481589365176,2.11365596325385,24.6351157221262));
#1278=CARTESIAN_POINT('',(34.5319362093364,1.71016298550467,24.0627757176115));
#1279=CARTESIAN_POINT('',(34.5217320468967,1.51108743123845,23.7738273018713));
#1280=CARTESIAN_POINT('',(34.4975999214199,1.11822608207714,23.1930961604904));
#1281=CARTESIAN_POINT('',(34.4836770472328,0.924433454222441,22.901317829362));
#1282=CARTESIAN_POINT('',(34.4524026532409,0.541090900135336,22.3154416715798));
#1283=CARTESIAN_POINT('',(34.4350533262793,0.351538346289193,22.0213454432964));
#1284=CARTESIAN_POINT('',(34.3971370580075,-0.0241027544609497,21.4311813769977));
#1285=CARTESIAN_POINT('',(34.3765702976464,-0.210191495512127,21.1351136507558));
#1286=CARTESIAN_POINT('',(34.3403691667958,-0.512667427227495,20.6487047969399));
#1287=CARTESIAN_POINT('',(34.325639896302,-0.629930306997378,20.4588391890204));
#1288=CARTESIAN_POINT('',(34.294965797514,-0.863382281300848,20.0784855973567));
#1289=CARTESIAN_POINT('',(34.2790206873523,-0.979571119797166,19.8879974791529));
#1290=CARTESIAN_POINT('',(34.2459447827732,-1.21095625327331,19.5064794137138));
#1291=CARTESIAN_POINT('',(34.228813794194,-1.32615238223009,19.3154493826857));
#1292=CARTESIAN_POINT('',(34.1933921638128,-1.55561927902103,18.9329190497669));
#1293=CARTESIAN_POINT('',(34.1751014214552,-1.66988996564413,18.741418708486));
#1294=CARTESIAN_POINT('',(34.1375766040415,-1.89639629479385,18.3599760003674));
#1295=CARTESIAN_POINT('',(34.1183541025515,-2.00864079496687,18.1700377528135));
#1296=CARTESIAN_POINT('',(34.0788160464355,-2.2323229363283,17.7898226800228));
#1297=CARTESIAN_POINT('',(34.058500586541,-2.34376064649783,17.5995458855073));
#1298=CARTESIAN_POINT('',(34.0167952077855,-2.56586658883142,17.2187081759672));
#1299=CARTESIAN_POINT('',(33.9954054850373,-2.6765349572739,17.0281473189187));
#1300=CARTESIAN_POINT('',(33.9515682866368,-2.89713163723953,16.6467913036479));
#1301=CARTESIAN_POINT('',(33.9291211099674,-3.00706014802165,16.4559962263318));
#1302=CARTESIAN_POINT('',(33.9061492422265,-3.11665429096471,16.2650726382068));
#1303=B_SPLINE_CURVE_WITH_KNOTS('',3,(#1193,#1194,#1195,#1196,#1197,#1198,#1199,#1200,#1201,
#1202,#1203,#1204,#1205,#1206,#1207,#1208,#1209,#1210,#1211,#1212,#1213,#1214,#1215,#1216,#1217,
#1218,#1219,#1220,#1221,#1222,#1223,#1224,#1225,#1226,#1227,#1228,#1229,#1230,#1231,#1232,#1233,
#1234,#1235,#1236,#1237,#1238,#1239,#1240,#1241,#1242,#1243,#1244,#1245,#1246,#1247,#1248,#1249,
#1250,#1251,#1252,#1253,#1254,#1255,#1256,#1257,#1258,#1259,#1260,#1261,#1262,#1263,#1264,#1265,
#1266,#1267,#1268,#1269,#1270,#1271,#1272,#1273,#1274,#1275,#1276,#1277,#1278,#1279,#1280,#1281,
#1282,#1283,#1284,#1285,#1286,#1287,#1288,#1289,#1290,#1291,#1292,#1293,#1294,#1295,#1296,#1297,
#1298,#1299,#1300,#1301,#1302),.UNSPECIFIED.,.F.,.F.,(4,2,2,2,2,2,2,2,2,2,2,2,2,2,2,2,2,2,2,2,2,
2,2,2,2,2,2,2,2,2,2,2,2,2,2,2,2,2,2,2,2,2,2,2,2,2,2,2,2,2,2,2,2,2,4),(0.,0.959614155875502,
1.91932417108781,2.87907098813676,3.84340641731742,4.80771099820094,5.77198397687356,
6.7364724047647,7.7009959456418,8.66566883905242,9.62789810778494,10.5900129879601,
11.5518878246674,12.1024685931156,12.6530683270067,13.2053826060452,13.75765072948,
14.3157839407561,14.8742099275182,15.4303567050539,15.9857060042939,16.248804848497,
16.5118870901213,16.7745880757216,17.0372210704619,17.3028080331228,17.568378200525,
17.8340330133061,18.0997162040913,18.3903212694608,18.6809725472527,18.9721194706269,
19.2632831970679,19.786301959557,20.309806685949,20.8351352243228,21.3602150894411,
21.8825481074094,22.4049541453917,22.9280486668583,23.4511755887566,24.499158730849,
25.5474673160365,26.6004879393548,27.6520748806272,28.7029910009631,29.7538480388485,
30.4247728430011,31.0958536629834,31.7670446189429,32.4382938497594,33.1026715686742,
33.7669917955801,34.4311911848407,35.0952038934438),.UNSPECIFIED.);
#1304=EDGE_CURVE('E303',#472,#422,#1303,.T.);
#1305=ORIENTED_EDGE('',*,*,#1304,.F.);
#1306=ORIENTED_EDGE('',*,*,#524,.T.);
#1307=CARTESIAN_POINT('',(4.50631473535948,33.7495721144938,16.2650726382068));
#1308=CARTESIAN_POINT('',(4.66811680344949,33.7466930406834,16.5409887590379));
#1309=CARTESIAN_POINT('',(4.83035151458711,33.7425926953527,16.8166398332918));
#1310=CARTESIAN_POINT('',(5.15582001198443,33.7318757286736,17.3673394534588));
#1311=CARTESIAN_POINT('',(5.31905389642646,33.7252588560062,17.6423879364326));
#1312=CARTESIAN_POINT('',(5.64662853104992,33.7094353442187,18.191765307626));
#1313=CARTESIAN_POINT('',(5.81096932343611,33.7002286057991,18.4660941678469));
#1314=CARTESIAN_POINT('',(6.14169289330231,33.6790817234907,19.0152039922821));
#1315=CARTESIAN_POINT('',(6.30808167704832,33.6671287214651,19.2899808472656));
#1316=CARTESIAN_POINT('',(6.6423095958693,33.6403991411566,19.8385022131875));
#1317=CARTESIAN_POINT('',(6.81014868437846,33.6256226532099,20.1122467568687));
#1318=CARTESIAN_POINT('',(7.14751605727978,33.593102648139,20.6585050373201));
#1319=CARTESIAN_POINT('',(7.31704428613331,33.5753592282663,20.9310188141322));
#1320=CARTESIAN_POINT('',(7.6581355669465,33.5367198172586,21.474632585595));
#1321=CARTESIAN_POINT('',(7.82969906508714,33.5158231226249,21.7457322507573));
#1322=CARTESIAN_POINT('',(8.17521643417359,33.4706480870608,22.2861377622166));
#1323=CARTESIAN_POINT('',(8.34917039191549,33.4463696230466,22.5554435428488));
#1324=CARTESIAN_POINT('',(8.69999031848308,33.3941274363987,23.0918561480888));
#1325=CARTESIAN_POINT('',(8.87685673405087,33.3661631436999,23.3589626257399));
#1326=CARTESIAN_POINT('',(9.2336817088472,33.3062312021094,23.8896676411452));
#1327=CARTESIAN_POINT('',(9.41363130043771,33.2742738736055,24.1532733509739));
#1328=CARTESIAN_POINT('',(9.77791129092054,33.2057709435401,24.6767996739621));
#1329=CARTESIAN_POINT('',(9.96224116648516,33.1692258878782,24.9367207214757));
#1330=CARTESIAN_POINT('',(10.3364519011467,33.0908188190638,25.4516580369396));
#1331=CARTESIAN_POINT('',(10.5263313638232,33.0489581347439,25.7066755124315));
#1332=CARTESIAN_POINT('',(10.8306112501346,32.9781142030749,26.1023739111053));
#1333=CARTESIAN_POINT('',(10.9425689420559,32.9512783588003,26.2453176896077));
#1334=CARTESIAN_POINT('',(11.1692993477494,32.8952368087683,26.5285004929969));
#1335=CARTESIAN_POINT('',(11.2840721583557,32.8660310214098,26.6687394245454));
#1336=CARTESIAN_POINT('',(11.5173008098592,32.8048180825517,26.9462743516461));
#1337=CARTESIAN_POINT('',(11.6357670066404,32.7728024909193,27.0835598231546));
#1338=CARTESIAN_POINT('',(11.8766735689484,32.7056131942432,27.353804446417));
#1339=CARTESIAN_POINT('',(11.999113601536,32.6704397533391,27.4867639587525));
#1340=CARTESIAN_POINT('',(12.2500935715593,32.5959775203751,27.7484650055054));
#1341=CARTESIAN_POINT('',(12.3786844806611,32.5566489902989,27.8771467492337));
#1342=CARTESIAN_POINT('',(12.6418102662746,32.4734174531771,28.1269528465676));
#1343=CARTESIAN_POINT('',(12.7763482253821,32.4295120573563,28.2480732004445));
#1344=CARTESIAN_POINT('',(13.05186354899,32.3363896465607,28.4793900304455));
#1345=CARTESIAN_POINT('',(13.1928123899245,32.2871950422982,28.5896290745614));
#1346=CARTESIAN_POINT('',(13.4826553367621,32.1822560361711,28.7955343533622));
#1347=CARTESIAN_POINT('',(13.6315377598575,32.1265211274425,28.8912212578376));
#1348=CARTESIAN_POINT('',(13.8571488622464,32.0387590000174,29.0171569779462));
#1349=CARTESIAN_POINT('',(13.9306174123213,32.00969064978,29.0553432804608));
#1350=CARTESIAN_POINT('',(14.079405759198,31.9497461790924,29.1263522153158));
#1351=CARTESIAN_POINT('',(14.1547254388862,31.9188701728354,29.159175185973));
#1352=CARTESIAN_POINT('',(14.3069215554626,31.8553233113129,29.2185867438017));
#1353=CARTESIAN_POINT('',(14.3837955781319,31.822655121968,29.2451842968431));
#1354=CARTESIAN_POINT('',(14.5388506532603,31.7555323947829,29.291380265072));
#1355=CARTESIAN_POINT('',(14.6170313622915,31.721078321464,29.3109804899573));
#1356=CARTESIAN_POINT('',(14.7750956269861,31.6501180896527,29.3426542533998));
#1357=CARTESIAN_POINT('',(14.8549884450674,31.6135932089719,29.354640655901));
#1358=CARTESIAN_POINT('',(15.014925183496,31.539106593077,29.3702307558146));
#1359=CARTESIAN_POINT('',(15.0949690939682,31.5011449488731,29.3738349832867));
#1360=CARTESIAN_POINT('',(15.2544805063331,31.4241115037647,29.3725008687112));
#1361=CARTESIAN_POINT('',(15.333947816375,31.3850393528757,29.3675598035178));
#1362=CARTESIAN_POINT('',(15.4915577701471,31.3061769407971,29.3493497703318));
#1363=CARTESIAN_POINT('',(15.569700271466,31.2663866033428,29.3360799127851));
#1364=CARTESIAN_POINT('',(15.7313031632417,31.1827070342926,29.300146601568));
#1365=CARTESIAN_POINT('',(15.8145748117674,31.1387834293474,29.2767187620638));
#1366=CARTESIAN_POINT('',(15.9782919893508,31.0509198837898,29.2215580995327));
#1367=CARTESIAN_POINT('',(16.0587370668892,31.0069799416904,29.1898239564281));
#1368=CARTESIAN_POINT('',(16.2166736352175,30.9193015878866,29.1191196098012));
#1369=CARTESIAN_POINT('',(16.2941598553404,30.8755636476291,29.0801371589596));
#1370=CARTESIAN_POINT('',(16.4459882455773,30.7885481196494,28.9960693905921));
#1371=CARTESIAN_POINT('',(16.5203302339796,30.7452705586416,28.9509837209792));
#1372=CARTESIAN_POINT('',(16.7239862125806,30.62501624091,28.8177525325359));
#1373=CARTESIAN_POINT('',(16.8499343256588,30.5486470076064,28.7239071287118));
#1374=CARTESIAN_POINT('',(17.0931935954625,30.3977952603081,28.5242616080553));
#1375=CARTESIAN_POINT('',(17.2104966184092,30.3233145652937,28.418450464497));
#1376=CARTESIAN_POINT('',(17.4380928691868,30.1758562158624,28.1977099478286));
#1377=CARTESIAN_POINT('',(17.5483602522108,30.1028847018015,28.0827500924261));
#1378=CARTESIAN_POINT('',(17.7625628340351,29.9585011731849,27.8463236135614));
#1379=CARTESIAN_POINT('',(17.866501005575,29.8870884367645,27.724860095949));
#1380=CARTESIAN_POINT('',(18.0685629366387,29.7458990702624,27.477570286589));
#1381=CARTESIAN_POINT('',(18.1667142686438,29.6761158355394,27.3517701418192));
#1382=CARTESIAN_POINT('',(18.358587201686,29.5375661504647,27.0962769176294));
#1383=CARTESIAN_POINT('',(18.4523081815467,29.4687998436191,26.9665832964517));
#1384=CARTESIAN_POINT('',(18.6360620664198,29.3320079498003,26.703935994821));
#1385=CARTESIAN_POINT('',(18.7260899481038,29.2639834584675,26.5709782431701));
#1386=CARTESIAN_POINT('',(18.9028392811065,29.1286001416,26.3025448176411));
#1387=CARTESIAN_POINT('',(18.9895605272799,29.0612413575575,26.1670689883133));
#1388=CARTESIAN_POINT('',(19.2456889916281,28.8597271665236,25.7571058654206));
#1389=CARTESIAN_POINT('',(19.4107599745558,28.7263591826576,25.479520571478));
#1390=CARTESIAN_POINT('',(19.7318678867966,28.4608360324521,24.9185263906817));
#1391=CARTESIAN_POINT('',(19.8879019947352,28.3286812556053,24.6351157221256));
#1392=CARTESIAN_POINT('',(20.1932508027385,28.0644240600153,24.0627757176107));
#1393=CARTESIAN_POINT('',(20.342532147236,27.9323245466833,23.7738273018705));
#1394=CARTESIAN_POINT('',(20.6346373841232,27.6685122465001,23.1930961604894));
#1395=CARTESIAN_POINT('',(20.7774697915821,27.5367991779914,22.9013178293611));
#1396=CARTESIAN_POINT('',(21.0576798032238,27.2733376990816,22.3154416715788));
#1397=CARTESIAN_POINT('',(21.1950608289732,27.1415893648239,22.0213454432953));
#1398=CARTESIAN_POINT('',(21.4651084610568,26.8777368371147,21.4311813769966));
#1399=CARTESIAN_POINT('',(21.5977753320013,26.745632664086,21.1351136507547));
#1400=CARTESIAN_POINT('',(21.811689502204,26.5287388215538,20.6487047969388));
#1401=CARTESIAN_POINT('',(21.8941857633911,26.4441108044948,20.4588391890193));
#1402=CARTESIAN_POINT('',(22.0575808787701,26.274573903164,20.0784855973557));
#1403=CARTESIAN_POINT('',(22.1384793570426,26.1896649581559,19.887997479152));
#1404=CARTESIAN_POINT('',(22.298761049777,26.0195389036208,19.506479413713));
#1405=CARTESIAN_POINT('',(22.378144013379,25.9343217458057,19.3154493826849));
#1406=CARTESIAN_POINT('',(22.5354634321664,25.76355773,18.9329190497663));
#1407=CARTESIAN_POINT('',(22.6133997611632,25.6780108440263,18.7414187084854));
#1408=CARTESIAN_POINT('',(22.7670931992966,25.5074483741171,18.3599760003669));
#1409=CARTESIAN_POINT('',(22.8428644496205,25.4224363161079,18.170037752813));
#1410=CARTESIAN_POINT('',(22.9930946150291,25.2520606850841,17.7898226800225));
#1411=CARTESIAN_POINT('',(23.0675536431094,25.1666971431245,17.599545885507));
#1412=CARTESIAN_POINT('',(23.2152001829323,24.9956097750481,17.2187081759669));
#1413=CARTESIAN_POINT('',(23.2883879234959,24.9098860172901,17.0281473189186));
#1414=CARTESIAN_POINT('',(23.4335253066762,24.7380729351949,16.6467913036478));
#1415=CARTESIAN_POINT('',(23.5054752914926,24.6519837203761,16.4559962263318));
#1416=CARTESIAN_POINT('',(23.5768367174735,24.5656927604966,16.2650726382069));
#1417=B_SPLINE_CURVE_WITH_KNOTS('',3,(#1307,#1308,#1309,#1310,#1311,#1312,#1313,#1314,#1315,
#1316,#1317,#1318,#1319,#1320,#1321,#1322,#1323,#1324,#1325,#1326,#1327,#1328,#1329,#1330,#1331,
#1332,#1333,#1334,#1335,#1336,#1337,#1338,#1339,#1340,#1341,#1342,#1343,#1344,#1345,#1346,#1347,
#1348,#1349,#1350,#1351,#1352,#1353,#1354,#1355,#1356,#1357,#1358,#1359,#1360,#1361,#1362,#1363,
#1364,#1365,#1366,#1367,#1368,#1369,#1370,#1371,#1372,#1373,#1374,#1375,#1376,#1377,#1378,#1379,
#1380,#1381,#1382,#1383,#1384,#1385,#1386,#1387,#1388,#1389,#1390,#1391,#1392,#1393,#1394,#1395,
#1396,#1397,#1398,#1399,#1400,#1401,#1402,#1403,#1404,#1405,#1406,#1407,#1408,#1409,#1410,#1411,
#1412,#1413,#1414,#1415,#1416),.UNSPECIFIED.,.F.,.F.,(4,2,2,2,2,2,2,2,2,2,2,2,2,2,2,2,2,2,2,2,2,
2,2,2,2,2,2,2,2,2,2,2,2,2,2,2,2,2,2,2,2,2,2,2,2,2,2,2,2,2,2,2,2,2,4),(0.,0.959614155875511,
1.91932417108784,2.87907098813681,3.8434064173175,4.80771099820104,5.77198397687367,
6.7364724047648,7.70099594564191,8.66566883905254,9.62789810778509,10.5900129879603,
11.5518878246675,12.1024685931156,12.6530683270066,13.2053826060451,13.7576507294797,
14.3157839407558,14.874209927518,15.4303567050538,15.9857060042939,16.2488048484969,
16.5118870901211,16.7745880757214,17.0372210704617,17.3028080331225,17.5683782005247,
17.8340330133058,18.099716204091,18.3903212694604,18.6809725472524,18.9721194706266,
19.2632831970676,19.7863019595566,20.3098066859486,20.8351352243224,21.3602150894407,
21.8825481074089,22.4049541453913,22.9280486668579,23.4511755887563,24.499158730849,
25.5474673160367,26.6004879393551,27.6520748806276,28.7029910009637,29.7538480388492,
30.4247728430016,31.0958536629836,31.767044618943,32.4382938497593,33.1026715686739,
33.7669917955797,34.4311911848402,35.095203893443),.UNSPECIFIED.);
#1418=EDGE_CURVE('E213',#571,#521,#1417,.T.);
#1419=ORIENTED_EDGE('',*,*,#1418,.F.);
#1420=ORIENTED_EDGE('',*,*,#623,.T.);
#1421=CARTESIAN_POINT('',(-23.576836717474,24.5656927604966,16.2650726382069));
#1422=CARTESIAN_POINT('',(-23.4737038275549,24.6903996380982,16.540988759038));
#1423=CARTESIAN_POINT('',(-23.3693463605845,24.8146833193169,16.8166398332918));
#1424=CARTESIAN_POINT('',(-23.1580412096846,25.0624629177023,17.3673394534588));
#1425=CARTESIAN_POINT('',(-23.0510932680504,25.1859587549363,17.6423879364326));
#1426=CARTESIAN_POINT('',(-22.8344825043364,25.4322011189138,18.1917653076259));
#1427=CARTESIAN_POINT('',(-22.724819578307,25.5549476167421,18.4660941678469));
#1428=CARTESIAN_POINT('',(-22.5020835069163,25.8003328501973,19.015203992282));
#1429=CARTESIAN_POINT('',(-22.3889965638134,25.9229682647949,19.2899808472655));
#1430=CARTESIAN_POINT('',(-22.1597108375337,26.1676125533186,19.8385022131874));
#1431=CARTESIAN_POINT('',(-22.0435121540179,26.2896214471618,20.1122467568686));
#1432=CARTESIAN_POINT('',(-21.8077418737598,26.5331099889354,20.65850503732));
#1433=CARTESIAN_POINT('',(-21.6881703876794,26.6545896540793,20.9310188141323));
#1434=CARTESIAN_POINT('',(-21.4452939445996,26.8971742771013,21.474632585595));
#1435=CARTESIAN_POINT('',(-21.3219881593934,27.0182791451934,21.7457322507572));
#1436=CARTESIAN_POINT('',(-21.0712423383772,27.260249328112,22.2861377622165));
#1437=CARTESIAN_POINT('',(-20.94380215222,27.3811146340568,22.5554435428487));
#1438=CARTESIAN_POINT('',(-20.684224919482,27.6228242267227,23.0918561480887));
#1439=CARTESIAN_POINT('',(-20.5520871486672,27.743668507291,23.3589626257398));
#1440=CARTESIAN_POINT('',(-20.2827537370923,27.9852785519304,23.8896676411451));
#1441=CARTESIAN_POINT('',(-20.1455717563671,28.1060437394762,24.1532733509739));
#1442=CARTESIAN_POINT('',(-19.8648891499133,28.3481384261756,24.676799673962));
#1443=CARTESIAN_POINT('',(-19.7213892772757,28.4694678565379,24.9367207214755));
#1444=CARTESIAN_POINT('',(-19.4267715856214,28.7131515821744,25.4516580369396));
#1445=CARTESIAN_POINT('',(-19.2756556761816,28.8355056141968,25.7066755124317));
#1446=CARTESIAN_POINT('',(-19.0305522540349,29.0292307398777,26.1023739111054));
#1447=CARTESIAN_POINT('',(-18.9397666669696,29.1000309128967,26.2453176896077));
#1448=CARTESIAN_POINT('',(-18.7545875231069,29.2423545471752,26.5285004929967));
#1449=CARTESIAN_POINT('',(-18.6601938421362,29.3138780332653,26.6687394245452));
#1450=CARTESIAN_POINT('',(-18.4669199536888,29.4580578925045,26.9462743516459));
#1451=CARTESIAN_POINT('',(-18.3680266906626,29.5307170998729,27.0835598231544));
#1452=CARTESIAN_POINT('',(-18.1652931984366,29.677173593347,27.3538044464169));
#1453=CARTESIAN_POINT('',(-18.0614533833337,29.7509707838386,27.4867639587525));
#1454=CARTESIAN_POINT('',(-17.8467530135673,29.9007683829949,27.7484650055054));
#1455=CARTESIAN_POINT('',(-17.7358296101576,29.9767838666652,27.8771467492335));
#1456=CARTESIAN_POINT('',(-17.5067003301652,30.1306098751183,28.1269528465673));
#1457=CARTESIAN_POINT('',(-17.388490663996,30.2084213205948,28.2480732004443));
#1458=CARTESIAN_POINT('',(-17.1439036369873,30.3657670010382,28.4793900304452));
#1459=CARTESIAN_POINT('',(-17.0175615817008,30.445292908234,28.589629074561));
#1460=CARTESIAN_POINT('',(-16.7548028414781,30.6064728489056,28.795534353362));
#1461=CARTESIAN_POINT('',(-16.6184008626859,30.688123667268,28.8912212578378));
#1462=CARTESIAN_POINT('',(-16.4091194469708,30.8097947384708,29.0171569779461));
#1463=CARTESIAN_POINT('',(-16.3405860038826,30.8491109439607,29.0553432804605));
#1464=CARTESIAN_POINT('',(-16.200951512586,30.9280635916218,29.1263522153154));
#1465=CARTESIAN_POINT('',(-16.1298506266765,30.9677000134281,29.1591751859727));
#1466=CARTESIAN_POINT('',(-15.9852749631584,31.0470709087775,29.2185867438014));
#1467=CARTESIAN_POINT('',(-15.9118037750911,31.0868051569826,29.2451842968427));
#1468=CARTESIAN_POINT('',(-15.7626498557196,31.1661817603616,29.2913802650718));
#1469=CARTESIAN_POINT('',(-15.6869677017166,31.205824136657,29.3109804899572));
#1470=CARTESIAN_POINT('',(-15.5329373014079,31.2851607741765,29.3426542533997));
#1471=CARTESIAN_POINT('',(-15.4545686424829,31.324850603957,29.3546406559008));
#1472=CARTESIAN_POINT('',(-15.296613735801,31.4034525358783,29.3702307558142));
#1473=CARTESIAN_POINT('',(-15.2170275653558,31.4423646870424,29.3738349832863));
#1474=CARTESIAN_POINT('',(-15.0573466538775,31.5190461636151,29.3725008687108));
#1475=CARTESIAN_POINT('',(-14.9772517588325,31.5568151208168,29.3675598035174));
#1476=CARTESIAN_POINT('',(-14.8173264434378,31.6308696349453,29.3493497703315));
#1477=CARTESIAN_POINT('',(-14.7374960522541,31.6671550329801,29.3360799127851));
#1478=CARTESIAN_POINT('',(-14.5713149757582,31.7413279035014,29.300146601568));
#1479=CARTESIAN_POINT('',(-14.4850550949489,31.7790463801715,29.2767187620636));
#1480=CARTESIAN_POINT('',(-14.3142846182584,31.8522635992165,29.2215580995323));
#1481=CARTESIAN_POINT('',(-14.2297743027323,31.8877619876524,29.1898239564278));
#1482=CARTESIAN_POINT('',(-14.0627527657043,31.956575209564,29.119119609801));
#1483=CARTESIAN_POINT('',(-13.9802451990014,31.9898862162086,29.0801371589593));
#1484=CARTESIAN_POINT('',(-13.817550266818,32.0543371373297,28.9960693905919));
#1485=CARTESIAN_POINT('',(-13.7373630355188,32.0854769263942,28.9509837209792));
#1486=CARTESIAN_POINT('',(-13.5163669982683,32.1697242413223,28.8177525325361));
#1487=CARTESIAN_POINT('',(-13.3781317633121,32.2205790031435,28.7239071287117));
#1488=CARTESIAN_POINT('',(-13.1085214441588,32.3167122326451,28.524261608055));
#1489=CARTESIAN_POINT('',(-12.9771528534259,32.3619854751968,28.4184504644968));
#1490=CARTESIAN_POINT('',(-12.7199613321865,32.447988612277,28.1977099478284));
#1491=CARTESIAN_POINT('',(-12.5941593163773,32.4887021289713,28.0827500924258));
#1492=CARTESIAN_POINT('',(-12.3477226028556,32.5661507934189,27.8463236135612));
#1493=CARTESIAN_POINT('',(-12.227085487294,32.6028878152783,27.724860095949));
#1494=CARTESIAN_POINT('',(-11.9907156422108,32.6728360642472,27.477570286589));
#1495=CARTESIAN_POINT('',(-11.874960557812,32.7060647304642,27.351770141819));
#1496=CARTESIAN_POINT('',(-11.6470072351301,32.769692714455,27.0962769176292));
#1497=CARTESIAN_POINT('',(-11.5348094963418,32.8000916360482,26.9665832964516));
#1498=CARTESIAN_POINT('',(-11.3132926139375,32.858467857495,26.7039359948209));
#1499=CARTESIAN_POINT('',(-11.2039774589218,32.8864419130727,26.57097824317));
#1500=CARTESIAN_POINT('',(-10.9879291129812,32.9402199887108,26.3025448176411));
#1501=CARTESIAN_POINT('',(-10.8811960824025,32.9660238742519,26.1670689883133));
#1502=CARTESIAN_POINT('',(-10.5639524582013,33.0406311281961,25.7571058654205));
#1503=CARTESIAN_POINT('',(-10.3567610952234,33.0865352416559,25.479520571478));
#1504=CARTESIAN_POINT('',(-9.94895922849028,33.1720365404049,24.9185263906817));
#1505=CARTESIAN_POINT('',(-9.74835078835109,33.2116317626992,24.6351157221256));
#1506=CARTESIAN_POINT('',(-9.3513643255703,33.2856014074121,24.0627757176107));
#1507=CARTESIAN_POINT('',(-9.15500937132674,33.3199515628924,23.7738273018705));
#1508=CARTESIAN_POINT('',(-8.76662797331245,33.3838443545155,23.1930961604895));
#1509=CARTESIAN_POINT('',(-8.57459600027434,33.4133934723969,22.9013178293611));
#1510=CARTESIAN_POINT('',(-8.19390543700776,33.4682049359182,22.3154416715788));
#1511=CARTESIAN_POINT('',(-8.00524477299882,33.4934700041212,22.0213454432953));
#1512=CARTESIAN_POINT('',(-7.63058461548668,33.540092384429,21.4311813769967));
#1513=CARTESIAN_POINT('',(-7.44458497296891,33.5614499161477,21.1351136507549));
#1514=CARTESIAN_POINT('',(-7.14163723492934,33.5934636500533,20.648704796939));
#1515=CARTESIAN_POINT('',(-7.02403680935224,33.6051971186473,20.4588391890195));
#1516=CARTESIAN_POINT('',(-6.78961233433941,33.6272400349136,20.0784855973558));
#1517=CARTESIAN_POINT('',(-6.67278847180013,33.6375491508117,19.8879974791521));
#1518=CARTESIAN_POINT('',(-6.43984456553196,33.6567905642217,19.5064794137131));
#1519=CARTESIAN_POINT('',(-6.3237246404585,33.6657226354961,19.315449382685));
#1520=CARTESIAN_POINT('',(-6.09212890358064,33.6822502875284,18.9329190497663));
#1521=CARTESIAN_POINT('',(-5.97665314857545,33.6898457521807,18.7414187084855));
#1522=CARTESIAN_POINT('',(-5.74747574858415,33.703664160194,18.3599760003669));
#1523=CARTESIAN_POINT('',(-5.63376804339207,33.7099003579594,18.170037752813));
#1524=CARTESIAN_POINT('',(-5.4068960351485,33.7211275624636,17.7898226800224));
#1525=CARTESIAN_POINT('',(-5.29373168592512,33.7261186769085,17.5995458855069));
#1526=CARTESIAN_POINT('',(-5.06791408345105,33.734882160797,17.2187081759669));
#1527=CARTESIAN_POINT('',(-4.9552607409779,33.7386547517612,17.0281473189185));
#1528=CARTESIAN_POINT('',(-4.73044018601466,33.7450040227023,16.6467913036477));
#1529=CARTESIAN_POINT('',(-4.6182728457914,33.7475810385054,16.4559962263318));
#1530=CARTESIAN_POINT('',(-4.50631473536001,33.7495721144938,16.2650726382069));
#1531=B_SPLINE_CURVE_WITH_KNOTS('',3,(#1421,#1422,#1423,#1424,#1425,#1426,#1427,#1428,#1429,
#1430,#1431,#1432,#1433,#1434,#1435,#1436,#1437,#1438,#1439,#1440,#1441,#1442,#1443,#1444,#1445,
#1446,#1447,#1448,#1449,#1450,#1451,#1452,#1453,#1454,#1455,#1456,#1457,#1458,#1459,#1460,#1461,
#1462,#1463,#1464,#1465,#1466,#1467,#1468,#1469,#1470,#1471,#1472,#1473,#1474,#1475,#1476,#1477,
#1478,#1479,#1480,#1481,#1482,#1483,#1484,#1485,#1486,#1487,#1488,#1489,#1490,#1491,#1492,#1493,
#1494,#1495,#1496,#1497,#1498,#1499,#1500,#1501,#1502,#1503,#1504,#1505,#1506,#1507,#1508,#1509,
#1510,#1511,#1512,#1513,#1514,#1515,#1516,#1517,#1518,#1519,#1520,#1521,#1522,#1523,#1524,#1525,
#1526,#1527,#1528,#1529,#1530),.UNSPECIFIED.,.F.,.F.,(4,2,2,2,2,2,2,2,2,2,2,2,2,2,2,2,2,2,2,2,2,
2,2,2,2,2,2,2,2,2,2,2,2,2,2,2,2,2,2,2,2,2,2,2,2,2,2,2,2,2,2,2,2,2,4),(0.,0.959614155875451,
1.91932417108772,2.87907098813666,3.84340641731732,4.80771099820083,5.77198397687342,
6.73647240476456,7.70099594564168,8.66566883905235,9.62789810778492,10.5900129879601,
11.5518878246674,12.1024685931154,12.6530683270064,13.2053826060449,13.7576507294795,
14.3157839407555,14.8742099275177,15.4303567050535,15.9857060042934,16.2488048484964,
16.5118870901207,16.7745880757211,17.0372210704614,17.3028080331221,17.5683782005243,
17.8340330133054,18.0997162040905,18.3903212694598,18.6809725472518,18.9721194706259,
19.2632831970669,19.7863019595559,20.309806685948,20.8351352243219,21.3602150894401,
21.8825481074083,22.4049541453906,22.9280486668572,23.4511755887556,24.4991587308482,
25.547467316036,26.6004879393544,27.6520748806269,28.7029910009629,29.7538480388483,
30.4247728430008,31.0958536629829,31.7670446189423,32.4382938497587,33.1026715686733,
33.7669917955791,34.4311911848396,35.0952038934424),.UNSPECIFIED.);
#1532=CARTESIAN_POINT('',(-23.576836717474,24.5656927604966,16.2650726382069));
#1533=VERTEX_POINT('',#1532);
#1534=EDGE_CURVE('E244',#1533,#620,#1531,.T.);
#1535=ORIENTED_EDGE('',*,*,#1534,.F.);
#1536=EDGE_CURVE('E141',#1533,#847,#127,.T.);
#1537=ORIENTED_EDGE('',*,*,#1536,.T.);
#1538=EDGE_LOOP('',(#849,#850,#963,#964,#1077,#1078,#1191,#1192,#1305,#1306,#1419,#1420,#1535,#1537));
#1539=FACE_BOUND('',#1538,.T.);
#1540=ORIENTED_EDGE('',*,*,#725,.F.);
#1541=EDGE_LOOP('',(#1540));
#1542=FACE_BOUND('',#1541,.T.);
#1543=ADVANCED_FACE('F184',(#1539,#1542),#734,.T.);
#1544=CARTESIAN_POINT('',(-29.196119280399,17.5193353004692,16.2650726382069));
#1545=CARTESIAN_POINT('',(-29.1652929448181,17.5594142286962,16.1788472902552));
#1546=CARTESIAN_POINT('',(-29.1322697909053,17.5966730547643,16.092150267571));
#1547=CARTESIAN_POINT('',(-29.0617261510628,17.6651486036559,15.9181115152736));
#1548=CARTESIAN_POINT('',(-29.0242019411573,17.696360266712,15.8307693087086));
#1549=CARTESIAN_POINT('',(-28.9040827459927,17.7807338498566,15.5668553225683));
#1550=CARTESIAN_POINT('',(-28.8144971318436,17.823890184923,15.3899744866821));
#1551=CARTESIAN_POINT('',(-28.6669902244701,17.8654444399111,15.1279647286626));
#1552=CARTESIAN_POINT('',(-28.6154434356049,17.8754267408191,15.0409016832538));
#1553=CARTESIAN_POINT('',(-28.5082742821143,17.8869910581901,14.8687696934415));
#1554=CARTESIAN_POINT('',(-28.452654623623,17.8885786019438,14.7836994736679));
#1555=CARTESIAN_POINT('',(-28.3379270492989,17.8828087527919,14.6166812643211));
#1556=CARTESIAN_POINT('',(-28.2788318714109,17.8754822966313,14.5347234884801));
#1557=CARTESIAN_POINT('',(-28.157538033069,17.8514419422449,14.3745637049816));
#1558=CARTESIAN_POINT('',(-28.0953401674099,17.8347304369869,14.2963607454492));
#1559=CARTESIAN_POINT('',(-27.9774740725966,17.7945858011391,14.1553613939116));
#1560=CARTESIAN_POINT('',(-27.9221145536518,17.7724251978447,14.0919431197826));
#1561=CARTESIAN_POINT('',(-27.8102141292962,17.7207778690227,13.9692748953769));
#1562=CARTESIAN_POINT('',(-27.7536734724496,17.6912926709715,13.9100240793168));
#1563=CARTESIAN_POINT('',(-27.6400819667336,17.6250306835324,13.7963342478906));
#1564=CARTESIAN_POINT('',(-27.5830313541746,17.5882571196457,13.7418931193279));
#1565=CARTESIAN_POINT('',(-27.4691097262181,17.507603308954,13.6383551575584));
#1566=CARTESIAN_POINT('',(-27.412238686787,17.4637240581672,13.5892575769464));
#1567=CARTESIAN_POINT('',(-27.3080649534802,17.3764896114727,13.5039379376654));
#1568=CARTESIAN_POINT('',(-27.2606323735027,17.3340859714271,13.4668960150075));
#1569=CARTESIAN_POINT('',(-27.1668256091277,17.2447629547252,13.397124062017));
#1570=CARTESIAN_POINT('',(-27.1204517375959,17.1978422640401,13.3643952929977));
#1571=CARTESIAN_POINT('',(-27.0291926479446,17.0999108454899,13.3033769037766));
#1572=CARTESIAN_POINT('',(-26.9843066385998,17.0489023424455,13.2750848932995));
#1573=CARTESIAN_POINT('',(-26.8963214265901,16.9432064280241,13.2229137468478));
#1574=CARTESIAN_POINT('',(-26.8532228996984,16.8885176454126,13.1990362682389));
#1575=CARTESIAN_POINT('',(-26.7269349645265,16.7194764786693,13.1338837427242));
#1576=CARTESIAN_POINT('',(-26.6468255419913,16.6002272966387,13.0991362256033));
#1577=CARTESIAN_POINT('',(-26.4963171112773,16.3524733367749,13.0457059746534));
#1578=CARTESIAN_POINT('',(-26.4259225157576,16.2239643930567,13.0270305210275));
#1579=CARTESIAN_POINT('',(-26.331175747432,16.0332511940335,13.0100924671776));
#1580=CARTESIAN_POINT('',(-26.3027900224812,15.9734423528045,13.0062521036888));
#1581=CARTESIAN_POINT('',(-26.2481130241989,15.8529788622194,13.0012106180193));
#1582=CARTESIAN_POINT('',(-26.2218157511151,15.7923272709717,13.0000016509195));
#1583=CARTESIAN_POINT('',(-26.1965003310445,15.7312607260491,12.9999999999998));
#1584=B_SPLINE_CURVE_WITH_KNOTS('',3,(#1544,#1545,#1546,#1547,#1548,#1549,#1550,#1551,#1552,
#1553,#1554,#1555,#1556,#1557,#1558,#1559,#1560,#1561,#1562,#1563,#1564,#1565,#1566,#1567,#1568,
#1569,#1570,#1571,#1572,#1573,#1574,#1575,#1576,#1577,#1578,#1579,#1580,#1581,#1582,#1583),
.UNSPECIFIED.,.F.,.F.,(4,2,2,2,2,2,2,2,2,2,2,2,2,2,2,2,2,2,2,4),(0.,0.299698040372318,
0.599645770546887,1.20498031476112,1.5096406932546,1.81410045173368,2.11750656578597,
2.42083535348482,2.68159295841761,2.94229623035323,3.2028843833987,3.46343604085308,
3.68403118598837,3.90469069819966,4.12523092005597,4.34585377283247,4.78744512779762,
5.2292364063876,5.4281070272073,5.62638394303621),.UNSPECIFIED.);
#1585=CARTESIAN_POINT('',(-26.1965003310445,15.7312607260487,12.9999999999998));
#1586=VERTEX_POINT('',#1585);
#1587=EDGE_CURVE('E29',#847,#1586,#1584,.T.);
#1588=ORIENTED_EDGE('',*,*,#1587,.F.);
#1589=ORIENTED_EDGE('',*,*,#1536,.F.);
#1590=CARTESIAN_POINT('',(-21.1661148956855,22.0391645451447,12.9999999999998));
#1591=CARTESIAN_POINT('',(-21.2514034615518,22.053675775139,12.9999995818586));
#1592=CARTESIAN_POINT('',(-21.3364214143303,22.0700033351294,13.002073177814));
#1593=CARTESIAN_POINT('',(-21.5055086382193,22.1064479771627,13.010813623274));
#1594=CARTESIAN_POINT('',(-21.5895765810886,22.1265698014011,13.017486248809));
#1595=CARTESIAN_POINT('',(-21.7568917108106,22.1709235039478,13.0359552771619));
#1596=CARTESIAN_POINT('',(-21.8401246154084,22.1951908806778,13.0477974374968));
#1597=CARTESIAN_POINT('',(-22.0042924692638,22.2477539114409,13.0770311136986));
#1598=CARTESIAN_POINT('',(-22.0852282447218,22.2760480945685,13.0944206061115));
#1599=CARTESIAN_POINT('',(-22.2447259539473,22.3368821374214,13.1352731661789));
#1600=CARTESIAN_POINT('',(-22.3232631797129,22.3694547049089,13.1587845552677));
#1601=CARTESIAN_POINT('',(-22.4764024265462,22.4384959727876,13.2120638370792));
#1602=CARTESIAN_POINT('',(-22.5510051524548,22.474963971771,13.2418306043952));
#1603=CARTESIAN_POINT('',(-22.6951033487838,22.5513345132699,13.3075877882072));
#1604=CARTESIAN_POINT('',(-22.7646192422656,22.5912217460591,13.3435511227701));
#1605=CARTESIAN_POINT('',(-22.8980498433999,22.6741231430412,13.4217135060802));
#1606=CARTESIAN_POINT('',(-22.9619655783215,22.7171367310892,13.4639114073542));
#1607=CARTESIAN_POINT('',(-23.0752608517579,22.7997518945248,13.5481801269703));
#1608=CARTESIAN_POINT('',(-23.1254379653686,22.8390303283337,13.5894992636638));
#1609=CARTESIAN_POINT('',(-23.2206946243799,22.9191201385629,13.6763591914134));
#1610=CARTESIAN_POINT('',(-23.2657725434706,22.9599319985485,13.7219013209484));
#1611=CARTESIAN_POINT('',(-23.350556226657,23.0426773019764,13.8168914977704));
#1612=CARTESIAN_POINT('',(-23.3902580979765,23.0846115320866,13.8663423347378));
#1613=CARTESIAN_POINT('',(-23.464085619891,23.1691473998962,13.9687276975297));
#1614=CARTESIAN_POINT('',(-23.4982090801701,23.2117492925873,14.0216635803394));
#1615=CARTESIAN_POINT('',(-23.5891539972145,23.3359610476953,14.1800128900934));
#1616=CARTESIAN_POINT('',(-23.6385278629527,23.4179408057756,14.289516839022));
#1617=CARTESIAN_POINT('',(-23.7168726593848,23.5801894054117,14.5165356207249));
#1618=CARTESIAN_POINT('',(-23.7458485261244,23.6604586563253,14.6340485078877));
#1619=CARTESIAN_POINT('',(-23.7866766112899,23.8261308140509,14.8877018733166));
#1620=CARTESIAN_POINT('',(-23.7962877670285,23.91112350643,15.0244673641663));
#1621=CARTESIAN_POINT('',(-23.7936646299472,24.0750213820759,15.3014973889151));
#1622=CARTESIAN_POINT('',(-23.7814049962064,24.153919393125,15.4417657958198));
#1623=CARTESIAN_POINT('',(-23.741190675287,24.2903607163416,15.6966901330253));
#1624=CARTESIAN_POINT('',(-23.71659217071,24.3491413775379,15.8112404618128));
#1625=CARTESIAN_POINT('',(-23.6554107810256,24.4613872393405,16.0391889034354));
#1626=CARTESIAN_POINT('',(-23.6188735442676,24.5148716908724,16.15258973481));
#1627=CARTESIAN_POINT('',(-23.576836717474,24.5656927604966,16.2650726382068));
#1628=B_SPLINE_CURVE_WITH_KNOTS('',3,(#1590,#1591,#1592,#1593,#1594,#1595,#1596,#1597,#1598,
#1599,#1600,#1601,#1602,#1603,#1604,#1605,#1606,#1607,#1608,#1609,#1610,#1611,#1612,#1613,#1614,
#1615,#1616,#1617,#1618,#1619,#1620,#1621,#1622,#1623,#1624,#1625,#1626,#1627),.UNSPECIFIED.,
.F.,.F.,(4,2,2,2,2,2,2,2,2,2,2,2,2,2,2,2,2,2,4),(0.,0.259555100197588,0.519436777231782,
0.781666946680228,1.04380157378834,1.30807155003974,1.57229402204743,1.83538972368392,
2.09843706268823,2.32597812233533,2.55359154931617,2.78136891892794,3.00923550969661,
3.4435621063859,3.87778356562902,4.35989598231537,4.84256736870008,5.2351577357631,
5.62626424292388),.UNSPECIFIED.);
#1629=CARTESIAN_POINT('',(-21.1661148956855,22.0391645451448,12.9999999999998));
#1630=VERTEX_POINT('',#1629);
#1631=EDGE_CURVE('E237',#1630,#1533,#1628,.T.);
#1632=ORIENTED_EDGE('',*,*,#1631,.F.);
#1633=EDGE_CURVE('E131',#1630,#1586,#73,.T.);
#1634=ORIENTED_EDGE('',*,*,#1633,.T.);
#1635=EDGE_LOOP('',(#1588,#1589,#1632,#1634));
#1636=FACE_BOUND('',#1635,.T.);
#1637=ADVANCED_FACE('F174',(#1636),#23,.T.);
#1638=CARTESIAN_POINT('',(30.5569827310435,0.,12.9999999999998));
#1639=DIRECTION('',(0.,0.,-1.));
#1640=DIRECTION('',(0.,-1.,0.));
#1641=AXIS2_PLACEMENT_3D('',#1638,#1639,#1640);
#1642=PLANE('',#1641);
#1643=CARTESIAN_POINT('',(-41.3680424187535,9.44198573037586,12.9999999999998));
#1644=DIRECTION('',(0.,0.,-1.));
#1645=DIRECTION('',(0.781831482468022,-0.623489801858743,0.));
#1646=AXIS2_PLACEMENT_3D('',#1643,#1644,#1645);
#1647=CIRCLE('',#1646,16.4234792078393);
#1648=EDGE_CURVE('E114',#1586,#64,#1647,.T.);
#1649=ORIENTED_EDGE('',*,*,#1648,.F.);
#1650=ORIENTED_EDGE('',*,*,#1633,.F.);
#1651=CARTESIAN_POINT('',(-18.410510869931,38.2298197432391,12.9999999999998));
#1652=DIRECTION('',(0.,0.,-1.));
#1653=DIRECTION('',(0.,-1.,0.));
#1654=AXIS2_PLACEMENT_3D('',#1651,#1652,#1653);
#1655=CIRCLE('',#1654,16.4234792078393);
#1656=EDGE_CURVE('E212',#575,#1630,#1655,.T.);
#1657=ORIENTED_EDGE('',*,*,#1656,.F.);
#1658=ORIENTED_EDGE('',*,*,#576,.F.);
#1659=CARTESIAN_POINT('',(18.4105108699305,38.2298197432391,12.9999999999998));
#1660=DIRECTION('',(0.,0.,-1.));
#1661=DIRECTION('',(-0.781831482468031,-0.623489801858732,0.));
#1662=AXIS2_PLACEMENT_3D('',#1659,#1660,#1661);
#1663=CIRCLE('',#1662,16.4234792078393);
#1664=EDGE_CURVE('E218',#476,#569,#1663,.T.);
#1665=ORIENTED_EDGE('',*,*,#1664,.F.);
#1666=ORIENTED_EDGE('',*,*,#477,.F.);
#1667=CARTESIAN_POINT('',(41.3680424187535,9.44198573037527,12.9999999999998));
#1668=DIRECTION('',(0.,0.,-1.));
#1669=DIRECTION('',(-0.974927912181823,0.222520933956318,0.));
#1670=AXIS2_PLACEMENT_3D('',#1667,#1668,#1669);
#1671=CIRCLE('',#1670,16.4234792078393);
#1672=EDGE_CURVE('E409',#377,#470,#1671,.T.);
#1673=ORIENTED_EDGE('',*,*,#1672,.F.);
#1674=ORIENTED_EDGE('',*,*,#378,.F.);
#1675=CARTESIAN_POINT('',(33.1745942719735,-26.4558561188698,12.9999999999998));
#1676=DIRECTION('',(0.,0.,-1.));
#1677=DIRECTION('',(-0.433883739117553,0.900968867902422,0.));
#1678=AXIS2_PLACEMENT_3D('',#1675,#1676,#1677);
#1679=CIRCLE('',#1678,16.4234792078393);
#1680=EDGE_CURVE('E396',#278,#371,#1679,.T.);
#1681=ORIENTED_EDGE('',*,*,#1680,.F.);
#1682=ORIENTED_EDGE('',*,*,#279,.F.);
#1683=CARTESIAN_POINT('',(-4.9960036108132E-13,-42.4318987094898,12.9999999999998));
#1684=DIRECTION('',(0.,0.,-1.));
#1685=DIRECTION('',(0.433883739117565,0.900968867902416,0.));
#1686=AXIS2_PLACEMENT_3D('',#1683,#1684,#1685);
#1687=CIRCLE('',#1686,16.4234792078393);
#1688=EDGE_CURVE('E458',#179,#272,#1687,.T.);
#1689=ORIENTED_EDGE('',*,*,#1688,.F.);
#1690=ORIENTED_EDGE('',*,*,#180,.F.);
#1691=CARTESIAN_POINT('',(-33.1745942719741,-26.4558561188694,12.9999999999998));
#1692=DIRECTION('',(0.,0.,-1.));
#1693=DIRECTION('',(0.974927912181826,0.222520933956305,0.));
#1694=AXIS2_PLACEMENT_3D('',#1691,#1692,#1693);
#1695=CIRCLE('',#1694,16.4234792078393);
#1696=EDGE_CURVE('E124',#75,#173,#1695,.T.);
#1697=ORIENTED_EDGE('',*,*,#1696,.F.);
#1698=ORIENTED_EDGE('',*,*,#76,.F.);
#1699=EDGE_LOOP('',(#1649,#1650,#1657,#1658,#1665,#1666,#1673,#1674,#1681,#1682,#1689,#1690,
#1697,#1698));
#1700=FACE_BOUND('',#1699,.T.);
#1701=CARTESIAN_POINT('',(0.,0.,12.9999999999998));
#1702=DIRECTION('',(0.,0.,1.));
#1703=DIRECTION('',(0.,1.,0.));
#1704=AXIS2_PLACEMENT_3D('',#1701,#1702,#1703);
#1705=CIRCLE('',#1704,16.25);
#1706=CARTESIAN_POINT('',(0.,16.25,12.9999999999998));
#1707=VERTEX_POINT('',#1706);
#1708=EDGE_CURVE('E139',#1707,#1707,#1705,.T.);
#1709=ORIENTED_EDGE('',*,*,#1708,.T.);
#1710=EDGE_LOOP('',(#1709));
#1711=FACE_BOUND('',#1710,.T.);
#1712=ADVANCED_FACE('F128',(#1700,#1711),#1642,.T.);
#1713=CARTESIAN_POINT('',(0.,0.,39.4436305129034));
#1714=DIRECTION('',(0.,0.,1.));
#1715=DIRECTION('',(0.,1.,0.));
#1716=AXIS2_PLACEMENT_3D('',#1713,#1714,#1715);
#1717=CYLINDRICAL_SURFACE('',#1716,16.25);
#1718=ORIENTED_EDGE('',*,*,#1708,.F.);
#1719=EDGE_LOOP('',(#1718));
#1720=FACE_BOUND('',#1719,.T.);
#1721=CARTESIAN_POINT('',(0.,0.,0.999999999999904));
#1722=DIRECTION('',(0.,0.,1.));
#1723=DIRECTION('',(0.,1.,0.));
#1724=AXIS2_PLACEMENT_3D('',#1721,#1722,#1723);
#1725=CIRCLE('',#1724,16.25);
#1726=CARTESIAN_POINT('',(0.,16.25,0.999999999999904));
#1727=VERTEX_POINT('',#1726);
#1728=EDGE_CURVE('E222',#1727,#1727,#1725,.T.);
#1729=ORIENTED_EDGE('',*,*,#1728,.T.);
#1730=EDGE_LOOP('',(#1729));
#1731=FACE_BOUND('',#1730,.T.);
#1732=ADVANCED_FACE('F191',(#1720,#1731),#1717,.T.);
#1733=CARTESIAN_POINT('',(0.,0.,0.));
#1734=DIRECTION('',(0.,0.,1.));
#1735=DIRECTION('',(0.,1.,0.));
#1736=AXIS2_PLACEMENT_3D('',#1733,#1734,#1735);
#1737=CONICAL_SURFACE('',#1736,15.25,0.785398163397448);
#1738=ORIENTED_EDGE('',*,*,#1728,.F.);
#1739=EDGE_LOOP('',(#1738));
#1740=FACE_BOUND('',#1739,.T.);
#1741=CARTESIAN_POINT('',(0.,0.,0.));
#1742=DIRECTION('',(0.,0.,1.));
#1743=DIRECTION('',(0.,1.,0.));
#1744=AXIS2_PLACEMENT_3D('',#1741,#1742,#1743);
#1745=CIRCLE('',#1744,15.25);
#1746=CARTESIAN_POINT('',(0.,15.25,0.));
#1747=VERTEX_POINT('',#1746);
#1748=EDGE_CURVE('E225',#1747,#1747,#1745,.T.);
#1749=ORIENTED_EDGE('',*,*,#1748,.T.);
#1750=EDGE_LOOP('',(#1749));
#1751=FACE_BOUND('',#1750,.T.);
#1752=ADVANCED_FACE('F521',(#1740,#1751),#1737,.T.);
#1753=CARTESIAN_POINT('',(5.,0.,0.));
#1754=DIRECTION('',(0.,0.,1.));
#1755=DIRECTION('',(0.,1.,0.));
#1756=AXIS2_PLACEMENT_3D('',#1753,#1754,#1755);
#1757=PLANE('',#1756);
#1758=ORIENTED_EDGE('',*,*,#1748,.F.);
#1759=EDGE_LOOP('',(#1758));
#1760=FACE_BOUND('',#1759,.T.);
#1761=CARTESIAN_POINT('',(0.,0.,0.));
#1762=DIRECTION('',(0.,0.,1.));
#1763=DIRECTION('',(0.,1.,0.));
#1764=AXIS2_PLACEMENT_3D('',#1761,#1762,#1763);
#1765=CIRCLE('',#1764,5.);
#1766=CARTESIAN_POINT('',(0.,5.,0.));
#1767=VERTEX_POINT('',#1766);
#1768=EDGE_CURVE('E229',#1767,#1767,#1765,.T.);
#1769=ORIENTED_EDGE('',*,*,#1768,.T.);
#1770=EDGE_LOOP('',(#1769));
#1771=FACE_BOUND('',#1770,.T.);
#1772=ADVANCED_FACE('F513',(#1760,#1771),#1757,.F.);
#1773=CARTESIAN_POINT('',(0.,0.,39.4436305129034));
#1774=DIRECTION('',(0.,0.,1.));
#1775=DIRECTION('',(0.,1.,0.));
#1776=AXIS2_PLACEMENT_3D('',#1773,#1774,#1775);
#1777=CYLINDRICAL_SURFACE('',#1776,5.);
#1778=ORIENTED_EDGE('',*,*,#1768,.F.);
#1779=EDGE_LOOP('',(#1778));
#1780=FACE_BOUND('',#1779,.T.);
#1781=CARTESIAN_POINT('',(0.,0.,21.));
#1782=DIRECTION('',(0.,0.,1.));
#1783=DIRECTION('',(0.,1.,0.));
#1784=AXIS2_PLACEMENT_3D('',#1781,#1782,#1783);
#1785=CIRCLE('',#1784,5.);
#1786=CARTESIAN_POINT('',(0.,5.,21.));
#1787=VERTEX_POINT('',#1786);
#1788=EDGE_CURVE('E234',#1787,#1787,#1785,.T.);
#1789=ORIENTED_EDGE('',*,*,#1788,.T.);
#1790=EDGE_LOOP('',(#1789));
#1791=FACE_BOUND('',#1790,.T.);
#1792=ADVANCED_FACE('F505',(#1780,#1791),#1777,.F.);
#1793=CARTESIAN_POINT('',(5.,0.,21.));
#1794=DIRECTION('',(0.,0.,-1.));
#1795=DIRECTION('',(0.,-1.,0.));
#1796=AXIS2_PLACEMENT_3D('',#1793,#1794,#1795);
#1797=PLANE('',#1796);
#1798=ORIENTED_EDGE('',*,*,#1788,.F.);
#1799=EDGE_LOOP('',(#1798));
#1800=FACE_BOUND('',#1799,.T.);
#1801=ADVANCED_FACE('F258',(#1800),#1797,.T.);
#1802=CARTESIAN_POINT('',(-31.4427437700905,28.2352424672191,12.9999999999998));
#1803=CARTESIAN_POINT('',(-23.8029538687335,33.8059226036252,29.5));
#1804=CARTESIAN_POINT('',(-17.5443641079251,10.1127230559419,12.9999999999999));
#1805=CARTESIAN_POINT('',(-17.9230460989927,25.3282346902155,29.4999999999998));
#1806=CARTESIAN_POINT('',(3.03228684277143,20.0219158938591,12.9999999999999));
#1807=CARTESIAN_POINT('',(-8.62757481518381,29.8046977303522,29.4999999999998));
#1808=CARTESIAN_POINT('',(-2.47097139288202,42.1873127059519,12.9999999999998));
#1809=CARTESIAN_POINT('',(-11.589635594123,39.6875466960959,29.5));
#1810=(BOUNDED_SURFACE() B_SPLINE_SURFACE(3,1,((#1802,#1803),(#1804,#1805),(#1806,#1807),(#1808,
#1809)),.UNSPECIFIED.,.F.,.F.,.F.) B_SPLINE_SURFACE_WITH_KNOTS((4,4),(2,2),(0.,1.),(0.,1.),
.UNSPECIFIED.) GEOMETRIC_REPRESENTATION_ITEM() RATIONAL_B_SPLINE_SURFACE(((1.,1.),
(0.469330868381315,0.437966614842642),(0.469330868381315,0.437966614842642),(1.,1.))) REPRESENTATION_ITEM('') SURFACE());
#1811=ORIENTED_EDGE('',*,*,#1631,.T.);
#1812=ORIENTED_EDGE('',*,*,#1534,.T.);
#1813=ORIENTED_EDGE('',*,*,#621,.T.);
#1814=ORIENTED_EDGE('',*,*,#1656,.T.);
#1815=EDGE_LOOP('',(#1811,#1812,#1813,#1814));
#1816=FACE_BOUND('',#1815,.T.);
#1817=ADVANCED_FACE('F250',(#1816),#1810,.F.);
#1818=CARTESIAN_POINT('',(2.47097139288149,42.1873127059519,12.9999999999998));
#1819=CARTESIAN_POINT('',(11.5896355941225,39.6875466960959,29.5));
#1820=CARTESIAN_POINT('',(-3.03228684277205,20.0219158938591,12.9999999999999));
#1821=CARTESIAN_POINT('',(8.62757481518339,29.8046977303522,29.4999999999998));
#1822=CARTESIAN_POINT('',(17.5443641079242,10.1127230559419,12.9999999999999));
#1823=CARTESIAN_POINT('',(17.9230460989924,25.3282346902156,29.4999999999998));
#1824=CARTESIAN_POINT('',(31.44274377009,28.2352424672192,12.9999999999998));
#1825=CARTESIAN_POINT('',(23.8029538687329,33.8059226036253,29.5));
#1826=(BOUNDED_SURFACE() B_SPLINE_SURFACE(3,1,((#1818,#1819),(#1820,#1821),(#1822,#1823),(#1824,
#1825)),.UNSPECIFIED.,.F.,.F.,.F.) B_SPLINE_SURFACE_WITH_KNOTS((4,4),(2,2),(0.,1.),(0.,1.),
.UNSPECIFIED.) GEOMETRIC_REPRESENTATION_ITEM() RATIONAL_B_SPLINE_SURFACE(((1.,1.),
(0.469330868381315,0.437966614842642),(0.469330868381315,0.437966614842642),(1.,1.))) REPRESENTATION_ITEM('') SURFACE());
#1827=ORIENTED_EDGE('',*,*,#572,.T.);
#1828=ORIENTED_EDGE('',*,*,#1418,.T.);
#1829=ORIENTED_EDGE('',*,*,#522,.T.);
#1830=ORIENTED_EDGE('',*,*,#1664,.T.);
#1831=EDGE_LOOP('',(#1827,#1828,#1829,#1830));
#1832=FACE_BOUND('',#1831,.T.);
#1833=ADVANCED_FACE('F257',(#1832),#1826,.F.);
#1834=CARTESIAN_POINT('',(34.5239946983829,24.3714760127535,12.9999999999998));
#1835=CARTESIAN_POINT('',(38.254993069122,15.6836386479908,29.5));
#1836=CARTESIAN_POINT('',(13.7631642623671,14.8541976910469,12.9999999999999));
#1837=CARTESIAN_POINT('',(28.6814559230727,11.8376154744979,29.4999999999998));
#1838=CARTESIAN_POINT('',(18.8451773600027,-7.4115565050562,12.9999999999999));
#1839=CARTESIAN_POINT('',(30.9772477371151,1.77909432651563,29.4999999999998));
#1840=CARTESIAN_POINT('',(41.6794315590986,-6.97854124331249,12.9999999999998));
#1841=CARTESIAN_POINT('',(41.2714335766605,2.467749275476,29.5));
#1842=(BOUNDED_SURFACE() B_SPLINE_SURFACE(3,1,((#1834,#1835),(#1836,#1837),(#1838,#1839),(#1840,
#1841)),.UNSPECIFIED.,.F.,.F.,.F.) B_SPLINE_SURFACE_WITH_KNOTS((4,4),(2,2),(0.,1.),(0.,1.),
.UNSPECIFIED.) GEOMETRIC_REPRESENTATION_ITEM() RATIONAL_B_SPLINE_SURFACE(((1.,1.),
(0.469330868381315,0.437966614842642),(0.469330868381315,0.437966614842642),(1.,1.))) REPRESENTATION_ITEM('') SURFACE());
#1843=ORIENTED_EDGE('',*,*,#473,.T.);
#1844=ORIENTED_EDGE('',*,*,#1304,.T.);
#1845=ORIENTED_EDGE('',*,*,#423,.T.);
#1846=ORIENTED_EDGE('',*,*,#1672,.T.);
#1847=EDGE_LOOP('',(#1843,#1844,#1845,#1846));
#1848=FACE_BOUND('',#1847,.T.);
#1849=ADVANCED_FACE('F422',(#1848),#1842,.F.);
#1850=CARTESIAN_POINT('',(40.5797458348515,-11.7965792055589,12.9999999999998));
#1851=CARTESIAN_POINT('',(36.1135605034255,-20.1303691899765,29.5));
#1852=CARTESIAN_POINT('',(20.1946719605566,-1.49903434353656,12.9999999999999));
#1853=CARTESIAN_POINT('',(27.1376157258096,-15.0434326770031,29.4999999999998));
#1854=CARTESIAN_POINT('',(5.955187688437,-19.3547828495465,12.9999999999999));
#1855=CARTESIAN_POINT('',(20.7049500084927,-23.1097403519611,29.4999999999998));
#1856=CARTESIAN_POINT('',(20.5306572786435,-36.9373410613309,12.9999999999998));
#1857=CARTESIAN_POINT('',(27.6616820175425,-30.7286895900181,29.5));
#1858=(BOUNDED_SURFACE() B_SPLINE_SURFACE(3,1,((#1850,#1851),(#1852,#1853),(#1854,#1855),(#1856,
#1857)),.UNSPECIFIED.,.F.,.F.,.F.) B_SPLINE_SURFACE_WITH_KNOTS((4,4),(2,2),(0.,1.),(0.,1.),
.UNSPECIFIED.) GEOMETRIC_REPRESENTATION_ITEM() RATIONAL_B_SPLINE_SURFACE(((1.,1.),
(0.469330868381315,0.437966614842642),(0.469330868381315,0.437966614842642),(1.,1.))) REPRESENTATION_ITEM('') SURFACE());
#1859=ORIENTED_EDGE('',*,*,#374,.T.);
#1860=ORIENTED_EDGE('',*,*,#1190,.T.);
#1861=ORIENTED_EDGE('',*,*,#324,.T.);
#1862=ORIENTED_EDGE('',*,*,#1680,.T.);
#1863=EDGE_LOOP('',(#1859,#1860,#1861,#1862));
#1864=FACE_BOUND('',#1863,.T.);
#1865=ADVANCED_FACE('F373',(#1864),#1858,.F.);
#1866=CARTESIAN_POINT('',(16.0781206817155,-39.0815696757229,12.9999999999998));
#1867=CARTESIAN_POINT('',(6.77788029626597,-40.7857984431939,29.5));
#1868=CARTESIAN_POINT('',(11.4191797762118,-16.723462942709,12.9999999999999));
#1869=CARTESIAN_POINT('',(5.15859738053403,-30.5964691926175,29.4999999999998));
#1870=CARTESIAN_POINT('',(-11.4191797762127,-16.7234629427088,12.9999999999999));
#1871=CARTESIAN_POINT('',(-5.15859738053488,-30.5964691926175,29.4999999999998));
#1872=CARTESIAN_POINT('',(-16.0781206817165,-39.0815696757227,12.9999999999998));
#1873=CARTESIAN_POINT('',(-6.77788029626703,-40.7857984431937,29.5));
#1874=(BOUNDED_SURFACE() B_SPLINE_SURFACE(3,1,((#1866,#1867),(#1868,#1869),(#1870,#1871),(#1872,
#1873)),.UNSPECIFIED.,.F.,.F.,.F.) B_SPLINE_SURFACE_WITH_KNOTS((4,4),(2,2),(0.,1.),(0.,1.),
.UNSPECIFIED.) GEOMETRIC_REPRESENTATION_ITEM() RATIONAL_B_SPLINE_SURFACE(((1.,1.),
(0.469330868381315,0.437966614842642),(0.469330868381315,0.437966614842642),(1.,1.))) REPRESENTATION_ITEM('') SURFACE());
#1875=ORIENTED_EDGE('',*,*,#275,.T.);
#1876=ORIENTED_EDGE('',*,*,#1076,.T.);
#1877=ORIENTED_EDGE('',*,*,#225,.T.);
#1878=ORIENTED_EDGE('',*,*,#1688,.T.);
#1879=EDGE_LOOP('',(#1875,#1876,#1877,#1878));
#1880=FACE_BOUND('',#1879,.T.);
#1881=ADVANCED_FACE('F357',(#1880),#1874,.F.);
#1882=CARTESIAN_POINT('',(-20.5306572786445,-36.9373410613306,12.9999999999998));
#1883=CARTESIAN_POINT('',(-27.6616820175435,-30.7286895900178,29.5));
#1884=CARTESIAN_POINT('',(-5.95518768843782,-19.3547828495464,12.9999999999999));
#1885=CARTESIAN_POINT('',(-20.7049500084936,-23.1097403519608,29.4999999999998));
#1886=CARTESIAN_POINT('',(-20.1946719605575,-1.4990343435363,12.9999999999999));
#1887=CARTESIAN_POINT('',(-27.1376157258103,-15.0434326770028,29.4999999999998));
#1888=CARTESIAN_POINT('',(-40.5797458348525,-11.7965792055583,12.9999999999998));
#1889=CARTESIAN_POINT('',(-36.1135605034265,-20.130369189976,29.5));
#1890=(BOUNDED_SURFACE() B_SPLINE_SURFACE(3,1,((#1882,#1883),(#1884,#1885),(#1886,#1887),(#1888,
#1889)),.UNSPECIFIED.,.F.,.F.,.F.) B_SPLINE_SURFACE_WITH_KNOTS((4,4),(2,2),(0.,1.),(0.,1.),
.UNSPECIFIED.) GEOMETRIC_REPRESENTATION_ITEM() RATIONAL_B_SPLINE_SURFACE(((1.,1.),
(0.469330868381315,0.437966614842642),(0.469330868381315,0.437966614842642),(1.,1.))) REPRESENTATION_ITEM('') SURFACE());
#1891=ORIENTED_EDGE('',*,*,#176,.T.);
#1892=ORIENTED_EDGE('',*,*,#962,.T.);
#1893=ORIENTED_EDGE('',*,*,#121,.T.);
#1894=ORIENTED_EDGE('',*,*,#1696,.T.);
#1895=EDGE_LOOP('',(#1891,#1892,#1893,#1894));
#1896=FACE_BOUND('',#1895,.T.);
#1897=ADVANCED_FACE('F351',(#1896),#1890,.F.);
#1898=CARTESIAN_POINT('',(-41.679431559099,-6.97854124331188,12.9999999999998));
#1899=CARTESIAN_POINT('',(-41.271433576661,2.46774927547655,29.5));
#1900=CARTESIAN_POINT('',(-18.8451773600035,-7.41155650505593,12.9999999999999));
#1901=CARTESIAN_POINT('',(-30.9772477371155,1.77909432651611,29.4999999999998));
#1902=CARTESIAN_POINT('',(-13.7631642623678,14.8541976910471,12.9999999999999));
#1903=CARTESIAN_POINT('',(-28.6814559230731,11.8376154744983,29.4999999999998));
#1904=CARTESIAN_POINT('',(-34.523994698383,24.371476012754,12.9999999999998));
#1905=CARTESIAN_POINT('',(-38.2549930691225,15.6836386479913,29.5));
#1906=(BOUNDED_SURFACE() B_SPLINE_SURFACE(3,1,((#1898,#1899),(#1900,#1901),(#1902,#1903),(#1904,
#1905)),.UNSPECIFIED.,.F.,.F.,.F.) B_SPLINE_SURFACE_WITH_KNOTS((4,4),(2,2),(0.,1.),(0.,1.),
.UNSPECIFIED.) GEOMETRIC_REPRESENTATION_ITEM() RATIONAL_B_SPLINE_SURFACE(((1.,1.),
(0.469330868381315,0.437966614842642),(0.469330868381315,0.437966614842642),(1.,1.))) REPRESENTATION_ITEM('') SURFACE());
#1907=ORIENTED_EDGE('',*,*,#67,.T.);
#1908=ORIENTED_EDGE('',*,*,#848,.T.);
#1909=ORIENTED_EDGE('',*,*,#1587,.T.);
#1910=ORIENTED_EDGE('',*,*,#1648,.T.);
#1911=EDGE_LOOP('',(#1907,#1908,#1909,#1910));
#1912=FACE_BOUND('',#1911,.T.);
#1913=ADVANCED_FACE('F115',(#1912),#1906,.F.);
#1914=CLOSED_SHELL('',(#132,#231,#330,#429,#528,#627,#649,#669,#689,#709,#729,#1543,#1637,#1712,
#1732,#1752,#1772,#1792,#1801,#1817,#1833,#1849,#1865,#1881,#1897,#1913));
#1915=MANIFOLD_SOLID_BREP('B1',#1914);
#1916=ADVANCED_BREP_SHAPE_REPRESENTATION('',(#18,#1915),#14);
#1917=SHAPE_DEFINITION_REPRESENTATION(#9,#1916);
ENDSEC;
END-ISO-10303-21;
